VERSION 5.8 ;
BUSBITCHARS "[]" ;
DIVIDERCHAR "/" ;
UNITS
    DATABASE MICRONS 1000 ;
END UNITS

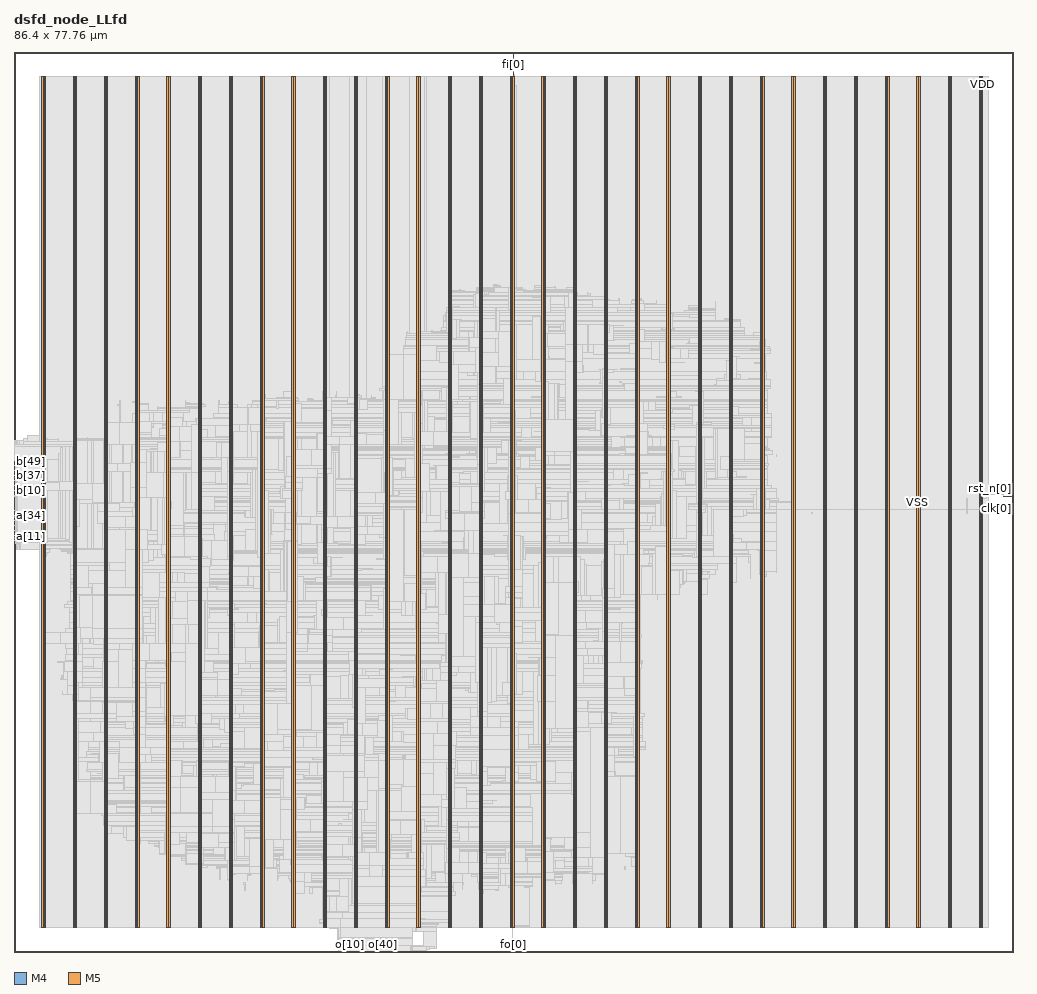
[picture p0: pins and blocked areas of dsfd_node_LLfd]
MACRO dsfd_node_LLfd
  FOREIGN dsfd_node_LLfd 0 0 ;
  CLASS BLOCK ;
  SIZE 86.4 BY 77.76 ;
  PIN a[0]
    DIRECTION INPUT ;
    USE SIGNAL ;
    PORT
      LAYER M4 ;
        RECT  0 35.376 0.084 35.4 ;
    END
  END a[0]
  PIN a[10]
    DIRECTION INPUT ;
    USE SIGNAL ;
    PORT
      LAYER M4 ;
        RECT  0 35.856 0.084 35.88 ;
    END
  END a[10]
  PIN a[11]
    DIRECTION INPUT ;
    USE SIGNAL ;
    PORT
      LAYER M4 ;
        RECT  0 35.904 0.084 35.928 ;
    END
  END a[11]
  PIN a[12]
    DIRECTION INPUT ;
    USE SIGNAL ;
    PORT
      LAYER M4 ;
        RECT  0 35.952 0.084 35.976 ;
    END
  END a[12]
  PIN a[13]
    DIRECTION INPUT ;
    USE SIGNAL ;
    PORT
      LAYER M4 ;
        RECT  0 36 0.084 36.024 ;
    END
  END a[13]
  PIN a[14]
    DIRECTION INPUT ;
    USE SIGNAL ;
    PORT
      LAYER M4 ;
        RECT  0 36.048 0.084 36.072 ;
    END
  END a[14]
  PIN a[15]
    DIRECTION INPUT ;
    USE SIGNAL ;
    PORT
      LAYER M4 ;
        RECT  0 36.096 0.084 36.12 ;
    END
  END a[15]
  PIN a[16]
    DIRECTION INPUT ;
    USE SIGNAL ;
    PORT
      LAYER M4 ;
        RECT  0 36.144 0.084 36.168 ;
    END
  END a[16]
  PIN a[17]
    DIRECTION INPUT ;
    USE SIGNAL ;
    PORT
      LAYER M4 ;
        RECT  0 36.192 0.084 36.216 ;
    END
  END a[17]
  PIN a[18]
    DIRECTION INPUT ;
    USE SIGNAL ;
    PORT
      LAYER M4 ;
        RECT  0 36.24 0.084 36.264 ;
    END
  END a[18]
  PIN a[19]
    DIRECTION INPUT ;
    USE SIGNAL ;
    PORT
      LAYER M4 ;
        RECT  0 36.288 0.084 36.312 ;
    END
  END a[19]
  PIN a[1]
    DIRECTION INPUT ;
    USE SIGNAL ;
    PORT
      LAYER M4 ;
        RECT  0 35.424 0.084 35.448 ;
    END
  END a[1]
  PIN a[20]
    DIRECTION INPUT ;
    USE SIGNAL ;
    PORT
      LAYER M4 ;
        RECT  0 36.336 0.084 36.36 ;
    END
  END a[20]
  PIN a[21]
    DIRECTION INPUT ;
    USE SIGNAL ;
    PORT
      LAYER M4 ;
        RECT  0 36.384 0.084 36.408 ;
    END
  END a[21]
  PIN a[22]
    DIRECTION INPUT ;
    USE SIGNAL ;
    PORT
      LAYER M4 ;
        RECT  0 36.432 0.084 36.456 ;
    END
  END a[22]
  PIN a[23]
    DIRECTION INPUT ;
    USE SIGNAL ;
    PORT
      LAYER M4 ;
        RECT  0 36.48 0.084 36.504 ;
    END
  END a[23]
  PIN a[24]
    DIRECTION INPUT ;
    USE SIGNAL ;
    PORT
      LAYER M4 ;
        RECT  0 36.528 0.084 36.552 ;
    END
  END a[24]
  PIN a[25]
    DIRECTION INPUT ;
    USE SIGNAL ;
    PORT
      LAYER M4 ;
        RECT  0 36.576 0.084 36.6 ;
    END
  END a[25]
  PIN a[26]
    DIRECTION INPUT ;
    USE SIGNAL ;
    PORT
      LAYER M4 ;
        RECT  0 36.624 0.084 36.648 ;
    END
  END a[26]
  PIN a[27]
    DIRECTION INPUT ;
    USE SIGNAL ;
    PORT
      LAYER M4 ;
        RECT  0 36.672 0.084 36.696 ;
    END
  END a[27]
  PIN a[28]
    DIRECTION INPUT ;
    USE SIGNAL ;
    PORT
      LAYER M4 ;
        RECT  0 36.72 0.084 36.744 ;
    END
  END a[28]
  PIN a[29]
    DIRECTION INPUT ;
    USE SIGNAL ;
    PORT
      LAYER M4 ;
        RECT  0 36.768 0.084 36.792 ;
    END
  END a[29]
  PIN a[2]
    DIRECTION INPUT ;
    USE SIGNAL ;
    PORT
      LAYER M4 ;
        RECT  0 35.472 0.084 35.496 ;
    END
  END a[2]
  PIN a[30]
    DIRECTION INPUT ;
    USE SIGNAL ;
    PORT
      LAYER M4 ;
        RECT  0 36.816 0.084 36.84 ;
    END
  END a[30]
  PIN a[31]
    DIRECTION INPUT ;
    USE SIGNAL ;
    PORT
      LAYER M4 ;
        RECT  0 36.864 0.084 36.888 ;
    END
  END a[31]
  PIN a[32]
    DIRECTION INPUT ;
    USE SIGNAL ;
    PORT
      LAYER M4 ;
        RECT  0 36.912 0.084 36.936 ;
    END
  END a[32]
  PIN a[33]
    DIRECTION INPUT ;
    USE SIGNAL ;
    PORT
      LAYER M4 ;
        RECT  0 36.96 0.084 36.984 ;
    END
  END a[33]
  PIN a[34]
    DIRECTION INPUT ;
    USE SIGNAL ;
    PORT
      LAYER M4 ;
        RECT  0 37.008 0.084 37.032 ;
    END
  END a[34]
  PIN a[35]
    DIRECTION INPUT ;
    USE SIGNAL ;
    PORT
      LAYER M4 ;
        RECT  0 37.056 0.084 37.08 ;
    END
  END a[35]
  PIN a[36]
    DIRECTION INPUT ;
    USE SIGNAL ;
    PORT
      LAYER M4 ;
        RECT  0 37.104 0.084 37.128 ;
    END
  END a[36]
  PIN a[37]
    DIRECTION INPUT ;
    USE SIGNAL ;
    PORT
      LAYER M4 ;
        RECT  0 37.152 0.084 37.176 ;
    END
  END a[37]
  PIN a[38]
    DIRECTION INPUT ;
    USE SIGNAL ;
    PORT
      LAYER M4 ;
        RECT  0 37.2 0.084 37.224 ;
    END
  END a[38]
  PIN a[39]
    DIRECTION INPUT ;
    USE SIGNAL ;
    PORT
      LAYER M4 ;
        RECT  0 37.248 0.084 37.272 ;
    END
  END a[39]
  PIN a[3]
    DIRECTION INPUT ;
    USE SIGNAL ;
    PORT
      LAYER M4 ;
        RECT  0 35.52 0.084 35.544 ;
    END
  END a[3]
  PIN a[40]
    DIRECTION INPUT ;
    USE SIGNAL ;
    PORT
      LAYER M4 ;
        RECT  0 37.296 0.084 37.32 ;
    END
  END a[40]
  PIN a[41]
    DIRECTION INPUT ;
    USE SIGNAL ;
    PORT
      LAYER M4 ;
        RECT  0 37.344 0.084 37.368 ;
    END
  END a[41]
  PIN a[42]
    DIRECTION INPUT ;
    USE SIGNAL ;
    PORT
      LAYER M4 ;
        RECT  0 37.392 0.084 37.416 ;
    END
  END a[42]
  PIN a[43]
    DIRECTION INPUT ;
    USE SIGNAL ;
    PORT
      LAYER M4 ;
        RECT  0 37.44 0.084 37.464 ;
    END
  END a[43]
  PIN a[44]
    DIRECTION INPUT ;
    USE SIGNAL ;
    PORT
      LAYER M4 ;
        RECT  0 37.488 0.084 37.512 ;
    END
  END a[44]
  PIN a[45]
    DIRECTION INPUT ;
    USE SIGNAL ;
    PORT
      LAYER M4 ;
        RECT  0 37.536 0.084 37.56 ;
    END
  END a[45]
  PIN a[46]
    DIRECTION INPUT ;
    USE SIGNAL ;
    PORT
      LAYER M4 ;
        RECT  0 37.584 0.084 37.608 ;
    END
  END a[46]
  PIN a[47]
    DIRECTION INPUT ;
    USE SIGNAL ;
    PORT
      LAYER M4 ;
        RECT  0 37.632 0.084 37.656 ;
    END
  END a[47]
  PIN a[48]
    DIRECTION INPUT ;
    USE SIGNAL ;
    PORT
      LAYER M4 ;
        RECT  0 37.68 0.084 37.704 ;
    END
  END a[48]
  PIN a[49]
    DIRECTION INPUT ;
    USE SIGNAL ;
    PORT
      LAYER M4 ;
        RECT  0 37.728 0.084 37.752 ;
    END
  END a[49]
  PIN a[4]
    DIRECTION INPUT ;
    USE SIGNAL ;
    PORT
      LAYER M4 ;
        RECT  0 35.568 0.084 35.592 ;
    END
  END a[4]
  PIN a[50]
    DIRECTION INPUT ;
    USE SIGNAL ;
    PORT
      LAYER M4 ;
        RECT  0 37.776 0.084 37.8 ;
    END
  END a[50]
  PIN a[51]
    DIRECTION INPUT ;
    USE SIGNAL ;
    PORT
      LAYER M4 ;
        RECT  0 37.824 0.084 37.848 ;
    END
  END a[51]
  PIN a[52]
    DIRECTION INPUT ;
    USE SIGNAL ;
    PORT
      LAYER M4 ;
        RECT  0 37.872 0.084 37.896 ;
    END
  END a[52]
  PIN a[53]
    DIRECTION INPUT ;
    USE SIGNAL ;
    PORT
      LAYER M4 ;
        RECT  0 37.92 0.084 37.944 ;
    END
  END a[53]
  PIN a[54]
    DIRECTION INPUT ;
    USE SIGNAL ;
    PORT
      LAYER M4 ;
        RECT  0 37.968 0.084 37.992 ;
    END
  END a[54]
  PIN a[55]
    DIRECTION INPUT ;
    USE SIGNAL ;
    PORT
      LAYER M4 ;
        RECT  0 38.016 0.084 38.04 ;
    END
  END a[55]
  PIN a[56]
    DIRECTION INPUT ;
    USE SIGNAL ;
    PORT
      LAYER M4 ;
        RECT  0 38.064 0.084 38.088 ;
    END
  END a[56]
  PIN a[57]
    DIRECTION INPUT ;
    USE SIGNAL ;
    PORT
      LAYER M4 ;
        RECT  0 38.112 0.084 38.136 ;
    END
  END a[57]
  PIN a[58]
    DIRECTION INPUT ;
    USE SIGNAL ;
    PORT
      LAYER M4 ;
        RECT  0 38.16 0.084 38.184 ;
    END
  END a[58]
  PIN a[59]
    DIRECTION INPUT ;
    USE SIGNAL ;
    PORT
      LAYER M4 ;
        RECT  0 38.208 0.084 38.232 ;
    END
  END a[59]
  PIN a[5]
    DIRECTION INPUT ;
    USE SIGNAL ;
    PORT
      LAYER M4 ;
        RECT  0 35.616 0.084 35.64 ;
    END
  END a[5]
  PIN a[60]
    DIRECTION INPUT ;
    USE SIGNAL ;
    PORT
      LAYER M4 ;
        RECT  0 38.256 0.084 38.28 ;
    END
  END a[60]
  PIN a[61]
    DIRECTION INPUT ;
    USE SIGNAL ;
    PORT
      LAYER M4 ;
        RECT  0 38.304 0.084 38.328 ;
    END
  END a[61]
  PIN a[62]
    DIRECTION INPUT ;
    USE SIGNAL ;
    PORT
      LAYER M4 ;
        RECT  0 38.352 0.084 38.376 ;
    END
  END a[62]
  PIN a[6]
    DIRECTION INPUT ;
    USE SIGNAL ;
    PORT
      LAYER M4 ;
        RECT  0 35.664 0.084 35.688 ;
    END
  END a[6]
  PIN a[7]
    DIRECTION INPUT ;
    USE SIGNAL ;
    PORT
      LAYER M4 ;
        RECT  0 35.712 0.084 35.736 ;
    END
  END a[7]
  PIN a[8]
    DIRECTION INPUT ;
    USE SIGNAL ;
    PORT
      LAYER M4 ;
        RECT  0 35.76 0.084 35.784 ;
    END
  END a[8]
  PIN a[9]
    DIRECTION INPUT ;
    USE SIGNAL ;
    PORT
      LAYER M4 ;
        RECT  0 35.808 0.084 35.832 ;
    END
  END a[9]
  PIN b[0]
    DIRECTION INPUT ;
    USE SIGNAL ;
    PORT
      LAYER M4 ;
        RECT  0 39.36 0.084 39.384 ;
    END
  END b[0]
  PIN b[10]
    DIRECTION INPUT ;
    USE SIGNAL ;
    PORT
      LAYER M4 ;
        RECT  0 39.84 0.084 39.864 ;
    END
  END b[10]
  PIN b[11]
    DIRECTION INPUT ;
    USE SIGNAL ;
    PORT
      LAYER M4 ;
        RECT  0 39.888 0.084 39.912 ;
    END
  END b[11]
  PIN b[12]
    DIRECTION INPUT ;
    USE SIGNAL ;
    PORT
      LAYER M4 ;
        RECT  0 39.936 0.084 39.96 ;
    END
  END b[12]
  PIN b[13]
    DIRECTION INPUT ;
    USE SIGNAL ;
    PORT
      LAYER M4 ;
        RECT  0 39.984 0.084 40.008 ;
    END
  END b[13]
  PIN b[14]
    DIRECTION INPUT ;
    USE SIGNAL ;
    PORT
      LAYER M4 ;
        RECT  0 40.032 0.084 40.056 ;
    END
  END b[14]
  PIN b[15]
    DIRECTION INPUT ;
    USE SIGNAL ;
    PORT
      LAYER M4 ;
        RECT  0 40.08 0.084 40.104 ;
    END
  END b[15]
  PIN b[16]
    DIRECTION INPUT ;
    USE SIGNAL ;
    PORT
      LAYER M4 ;
        RECT  0 40.128 0.084 40.152 ;
    END
  END b[16]
  PIN b[17]
    DIRECTION INPUT ;
    USE SIGNAL ;
    PORT
      LAYER M4 ;
        RECT  0 40.176 0.084 40.2 ;
    END
  END b[17]
  PIN b[18]
    DIRECTION INPUT ;
    USE SIGNAL ;
    PORT
      LAYER M4 ;
        RECT  0 40.224 0.084 40.248 ;
    END
  END b[18]
  PIN b[19]
    DIRECTION INPUT ;
    USE SIGNAL ;
    PORT
      LAYER M4 ;
        RECT  0 40.272 0.084 40.296 ;
    END
  END b[19]
  PIN b[1]
    DIRECTION INPUT ;
    USE SIGNAL ;
    PORT
      LAYER M4 ;
        RECT  0 39.408 0.084 39.432 ;
    END
  END b[1]
  PIN b[20]
    DIRECTION INPUT ;
    USE SIGNAL ;
    PORT
      LAYER M4 ;
        RECT  0 40.32 0.084 40.344 ;
    END
  END b[20]
  PIN b[21]
    DIRECTION INPUT ;
    USE SIGNAL ;
    PORT
      LAYER M4 ;
        RECT  0 40.368 0.084 40.392 ;
    END
  END b[21]
  PIN b[22]
    DIRECTION INPUT ;
    USE SIGNAL ;
    PORT
      LAYER M4 ;
        RECT  0 40.416 0.084 40.44 ;
    END
  END b[22]
  PIN b[23]
    DIRECTION INPUT ;
    USE SIGNAL ;
    PORT
      LAYER M4 ;
        RECT  0 40.464 0.084 40.488 ;
    END
  END b[23]
  PIN b[24]
    DIRECTION INPUT ;
    USE SIGNAL ;
    PORT
      LAYER M4 ;
        RECT  0 40.512 0.084 40.536 ;
    END
  END b[24]
  PIN b[25]
    DIRECTION INPUT ;
    USE SIGNAL ;
    PORT
      LAYER M4 ;
        RECT  0 40.56 0.084 40.584 ;
    END
  END b[25]
  PIN b[26]
    DIRECTION INPUT ;
    USE SIGNAL ;
    PORT
      LAYER M4 ;
        RECT  0 40.608 0.084 40.632 ;
    END
  END b[26]
  PIN b[27]
    DIRECTION INPUT ;
    USE SIGNAL ;
    PORT
      LAYER M4 ;
        RECT  0 40.656 0.084 40.68 ;
    END
  END b[27]
  PIN b[28]
    DIRECTION INPUT ;
    USE SIGNAL ;
    PORT
      LAYER M4 ;
        RECT  0 40.704 0.084 40.728 ;
    END
  END b[28]
  PIN b[29]
    DIRECTION INPUT ;
    USE SIGNAL ;
    PORT
      LAYER M4 ;
        RECT  0 40.752 0.084 40.776 ;
    END
  END b[29]
  PIN b[2]
    DIRECTION INPUT ;
    USE SIGNAL ;
    PORT
      LAYER M4 ;
        RECT  0 39.456 0.084 39.48 ;
    END
  END b[2]
  PIN b[30]
    DIRECTION INPUT ;
    USE SIGNAL ;
    PORT
      LAYER M4 ;
        RECT  0 40.8 0.084 40.824 ;
    END
  END b[30]
  PIN b[31]
    DIRECTION INPUT ;
    USE SIGNAL ;
    PORT
      LAYER M4 ;
        RECT  0 40.848 0.084 40.872 ;
    END
  END b[31]
  PIN b[32]
    DIRECTION INPUT ;
    USE SIGNAL ;
    PORT
      LAYER M4 ;
        RECT  0 40.896 0.084 40.92 ;
    END
  END b[32]
  PIN b[33]
    DIRECTION INPUT ;
    USE SIGNAL ;
    PORT
      LAYER M4 ;
        RECT  0 40.944 0.084 40.968 ;
    END
  END b[33]
  PIN b[34]
    DIRECTION INPUT ;
    USE SIGNAL ;
    PORT
      LAYER M4 ;
        RECT  0 40.992 0.084 41.016 ;
    END
  END b[34]
  PIN b[35]
    DIRECTION INPUT ;
    USE SIGNAL ;
    PORT
      LAYER M4 ;
        RECT  0 41.04 0.084 41.064 ;
    END
  END b[35]
  PIN b[36]
    DIRECTION INPUT ;
    USE SIGNAL ;
    PORT
      LAYER M4 ;
        RECT  0 41.088 0.084 41.112 ;
    END
  END b[36]
  PIN b[37]
    DIRECTION INPUT ;
    USE SIGNAL ;
    PORT
      LAYER M4 ;
        RECT  0 41.136 0.084 41.16 ;
    END
  END b[37]
  PIN b[38]
    DIRECTION INPUT ;
    USE SIGNAL ;
    PORT
      LAYER M4 ;
        RECT  0 41.184 0.084 41.208 ;
    END
  END b[38]
  PIN b[39]
    DIRECTION INPUT ;
    USE SIGNAL ;
    PORT
      LAYER M4 ;
        RECT  0 41.232 0.084 41.256 ;
    END
  END b[39]
  PIN b[3]
    DIRECTION INPUT ;
    USE SIGNAL ;
    PORT
      LAYER M4 ;
        RECT  0 39.504 0.084 39.528 ;
    END
  END b[3]
  PIN b[40]
    DIRECTION INPUT ;
    USE SIGNAL ;
    PORT
      LAYER M4 ;
        RECT  0 41.28 0.084 41.304 ;
    END
  END b[40]
  PIN b[41]
    DIRECTION INPUT ;
    USE SIGNAL ;
    PORT
      LAYER M4 ;
        RECT  0 41.328 0.084 41.352 ;
    END
  END b[41]
  PIN b[42]
    DIRECTION INPUT ;
    USE SIGNAL ;
    PORT
      LAYER M4 ;
        RECT  0 41.376 0.084 41.4 ;
    END
  END b[42]
  PIN b[43]
    DIRECTION INPUT ;
    USE SIGNAL ;
    PORT
      LAYER M4 ;
        RECT  0 41.424 0.084 41.448 ;
    END
  END b[43]
  PIN b[44]
    DIRECTION INPUT ;
    USE SIGNAL ;
    PORT
      LAYER M4 ;
        RECT  0 41.472 0.084 41.496 ;
    END
  END b[44]
  PIN b[45]
    DIRECTION INPUT ;
    USE SIGNAL ;
    PORT
      LAYER M4 ;
        RECT  0 41.52 0.084 41.544 ;
    END
  END b[45]
  PIN b[46]
    DIRECTION INPUT ;
    USE SIGNAL ;
    PORT
      LAYER M4 ;
        RECT  0 41.568 0.084 41.592 ;
    END
  END b[46]
  PIN b[47]
    DIRECTION INPUT ;
    USE SIGNAL ;
    PORT
      LAYER M4 ;
        RECT  0 41.616 0.084 41.64 ;
    END
  END b[47]
  PIN b[48]
    DIRECTION INPUT ;
    USE SIGNAL ;
    PORT
      LAYER M4 ;
        RECT  0 41.664 0.084 41.688 ;
    END
  END b[48]
  PIN b[49]
    DIRECTION INPUT ;
    USE SIGNAL ;
    PORT
      LAYER M4 ;
        RECT  0 41.712 0.084 41.736 ;
    END
  END b[49]
  PIN b[4]
    DIRECTION INPUT ;
    USE SIGNAL ;
    PORT
      LAYER M4 ;
        RECT  0 39.552 0.084 39.576 ;
    END
  END b[4]
  PIN b[50]
    DIRECTION INPUT ;
    USE SIGNAL ;
    PORT
      LAYER M4 ;
        RECT  0 41.76 0.084 41.784 ;
    END
  END b[50]
  PIN b[51]
    DIRECTION INPUT ;
    USE SIGNAL ;
    PORT
      LAYER M4 ;
        RECT  0 41.808 0.084 41.832 ;
    END
  END b[51]
  PIN b[52]
    DIRECTION INPUT ;
    USE SIGNAL ;
    PORT
      LAYER M4 ;
        RECT  0 41.856 0.084 41.88 ;
    END
  END b[52]
  PIN b[53]
    DIRECTION INPUT ;
    USE SIGNAL ;
    PORT
      LAYER M4 ;
        RECT  0 41.904 0.084 41.928 ;
    END
  END b[53]
  PIN b[54]
    DIRECTION INPUT ;
    USE SIGNAL ;
    PORT
      LAYER M4 ;
        RECT  0 41.952 0.084 41.976 ;
    END
  END b[54]
  PIN b[55]
    DIRECTION INPUT ;
    USE SIGNAL ;
    PORT
      LAYER M4 ;
        RECT  0 42 0.084 42.024 ;
    END
  END b[55]
  PIN b[56]
    DIRECTION INPUT ;
    USE SIGNAL ;
    PORT
      LAYER M4 ;
        RECT  0 42.048 0.084 42.072 ;
    END
  END b[56]
  PIN b[57]
    DIRECTION INPUT ;
    USE SIGNAL ;
    PORT
      LAYER M4 ;
        RECT  0 42.096 0.084 42.12 ;
    END
  END b[57]
  PIN b[58]
    DIRECTION INPUT ;
    USE SIGNAL ;
    PORT
      LAYER M4 ;
        RECT  0 42.144 0.084 42.168 ;
    END
  END b[58]
  PIN b[59]
    DIRECTION INPUT ;
    USE SIGNAL ;
    PORT
      LAYER M4 ;
        RECT  0 42.192 0.084 42.216 ;
    END
  END b[59]
  PIN b[5]
    DIRECTION INPUT ;
    USE SIGNAL ;
    PORT
      LAYER M4 ;
        RECT  0 39.6 0.084 39.624 ;
    END
  END b[5]
  PIN b[60]
    DIRECTION INPUT ;
    USE SIGNAL ;
    PORT
      LAYER M4 ;
        RECT  0 42.24 0.084 42.264 ;
    END
  END b[60]
  PIN b[61]
    DIRECTION INPUT ;
    USE SIGNAL ;
    PORT
      LAYER M4 ;
        RECT  0 42.288 0.084 42.312 ;
    END
  END b[61]
  PIN b[62]
    DIRECTION INPUT ;
    USE SIGNAL ;
    PORT
      LAYER M4 ;
        RECT  0 42.336 0.084 42.36 ;
    END
  END b[62]
  PIN b[6]
    DIRECTION INPUT ;
    USE SIGNAL ;
    PORT
      LAYER M4 ;
        RECT  0 39.648 0.084 39.672 ;
    END
  END b[6]
  PIN b[7]
    DIRECTION INPUT ;
    USE SIGNAL ;
    PORT
      LAYER M4 ;
        RECT  0 39.696 0.084 39.72 ;
    END
  END b[7]
  PIN b[8]
    DIRECTION INPUT ;
    USE SIGNAL ;
    PORT
      LAYER M4 ;
        RECT  0 39.744 0.084 39.768 ;
    END
  END b[8]
  PIN b[9]
    DIRECTION INPUT ;
    USE SIGNAL ;
    PORT
      LAYER M4 ;
        RECT  0 39.792 0.084 39.816 ;
    END
  END b[9]
  PIN clk[0]
    DIRECTION INPUT ;
    USE SIGNAL ;
    PORT
      LAYER M4 ;
        RECT  86.316 38.352 86.4 38.376 ;
    END
    PORT
      LAYER M4 ;
        RECT  86.281 38.208 86.321 38.376 ;
    END
    PORT
      LAYER M4 ;
        RECT  86.321 38.352 86.364 38.376 ;
    END
  END clk[0]
  PIN fi[0]
    DIRECTION INPUT ;
    USE SIGNAL ;
    PORT
      LAYER M5 ;
        RECT  43.152 77.676 43.176 77.76 ;
    END
    PORT
      LAYER M5 ;
        RECT  43.152 75.623 43.176 77.712 ;
    END
  END fi[0]
  PIN fo[0]
    DIRECTION OUTPUT ;
    USE SIGNAL ;
    PORT
      LAYER M5 ;
        RECT  43.152 0 43.176 0.084 ;
    END
    PORT
      LAYER M5 ;
        RECT  43.152 0.016 43.176 0.131 ;
    END
  END fo[0]
  PIN o[0]
    DIRECTION OUTPUT ;
    USE SIGNAL ;
    PORT
      LAYER M5 ;
        RECT  28.032 0 28.056 0.084 ;
    END
  END o[0]
  PIN o[10]
    DIRECTION OUTPUT ;
    USE SIGNAL ;
    PORT
      LAYER M5 ;
        RECT  28.992 0 29.016 0.084 ;
    END
  END o[10]
  PIN o[11]
    DIRECTION OUTPUT ;
    USE SIGNAL ;
    PORT
      LAYER M5 ;
        RECT  29.088 0 29.112 0.084 ;
    END
  END o[11]
  PIN o[12]
    DIRECTION OUTPUT ;
    USE SIGNAL ;
    PORT
      LAYER M5 ;
        RECT  29.184 0 29.208 0.084 ;
    END
  END o[12]
  PIN o[13]
    DIRECTION OUTPUT ;
    USE SIGNAL ;
    PORT
      LAYER M5 ;
        RECT  29.28 0 29.304 0.084 ;
    END
  END o[13]
  PIN o[14]
    DIRECTION OUTPUT ;
    USE SIGNAL ;
    PORT
      LAYER M5 ;
        RECT  29.376 0 29.4 0.084 ;
    END
  END o[14]
  PIN o[15]
    DIRECTION OUTPUT ;
    USE SIGNAL ;
    PORT
      LAYER M5 ;
        RECT  29.472 0 29.496 0.084 ;
    END
  END o[15]
  PIN o[16]
    DIRECTION OUTPUT ;
    USE SIGNAL ;
    PORT
      LAYER M5 ;
        RECT  29.568 0 29.592 0.084 ;
    END
  END o[16]
  PIN o[17]
    DIRECTION OUTPUT ;
    USE SIGNAL ;
    PORT
      LAYER M5 ;
        RECT  29.664 0 29.688 0.084 ;
    END
  END o[17]
  PIN o[18]
    DIRECTION OUTPUT ;
    USE SIGNAL ;
    PORT
      LAYER M5 ;
        RECT  29.76 0 29.784 0.084 ;
    END
  END o[18]
  PIN o[19]
    DIRECTION OUTPUT ;
    USE SIGNAL ;
    PORT
      LAYER M5 ;
        RECT  29.856 0 29.88 0.084 ;
    END
  END o[19]
  PIN o[1]
    DIRECTION OUTPUT ;
    USE SIGNAL ;
    PORT
      LAYER M5 ;
        RECT  28.128 0 28.152 0.084 ;
    END
  END o[1]
  PIN o[20]
    DIRECTION OUTPUT ;
    USE SIGNAL ;
    PORT
      LAYER M5 ;
        RECT  29.952 0 29.976 0.084 ;
    END
  END o[20]
  PIN o[21]
    DIRECTION OUTPUT ;
    USE SIGNAL ;
    PORT
      LAYER M5 ;
        RECT  30.048 0 30.072 0.084 ;
    END
  END o[21]
  PIN o[22]
    DIRECTION OUTPUT ;
    USE SIGNAL ;
    PORT
      LAYER M5 ;
        RECT  30.144 0 30.168 0.084 ;
    END
  END o[22]
  PIN o[23]
    DIRECTION OUTPUT ;
    USE SIGNAL ;
    PORT
      LAYER M5 ;
        RECT  30.24 0 30.264 0.084 ;
    END
  END o[23]
  PIN o[24]
    DIRECTION OUTPUT ;
    USE SIGNAL ;
    PORT
      LAYER M5 ;
        RECT  30.336 0 30.36 0.084 ;
    END
  END o[24]
  PIN o[25]
    DIRECTION OUTPUT ;
    USE SIGNAL ;
    PORT
      LAYER M5 ;
        RECT  30.432 0 30.456 0.084 ;
    END
  END o[25]
  PIN o[26]
    DIRECTION OUTPUT ;
    USE SIGNAL ;
    PORT
      LAYER M5 ;
        RECT  30.528 0 30.552 0.084 ;
    END
  END o[26]
  PIN o[27]
    DIRECTION OUTPUT ;
    USE SIGNAL ;
    PORT
      LAYER M5 ;
        RECT  30.624 0 30.648 0.084 ;
    END
  END o[27]
  PIN o[28]
    DIRECTION OUTPUT ;
    USE SIGNAL ;
    PORT
      LAYER M5 ;
        RECT  30.72 0 30.744 0.084 ;
    END
  END o[28]
  PIN o[29]
    DIRECTION OUTPUT ;
    USE SIGNAL ;
    PORT
      LAYER M5 ;
        RECT  30.816 0 30.84 0.084 ;
    END
  END o[29]
  PIN o[2]
    DIRECTION OUTPUT ;
    USE SIGNAL ;
    PORT
      LAYER M5 ;
        RECT  28.224 0 28.248 0.084 ;
    END
  END o[2]
  PIN o[30]
    DIRECTION OUTPUT ;
    USE SIGNAL ;
    PORT
      LAYER M5 ;
        RECT  30.912 0 30.936 0.084 ;
    END
  END o[30]
  PIN o[31]
    DIRECTION OUTPUT ;
    USE SIGNAL ;
    PORT
      LAYER M5 ;
        RECT  31.008 0 31.032 0.084 ;
    END
  END o[31]
  PIN o[32]
    DIRECTION OUTPUT ;
    USE SIGNAL ;
    PORT
      LAYER M5 ;
        RECT  31.104 0 31.128 0.084 ;
    END
  END o[32]
  PIN o[33]
    DIRECTION OUTPUT ;
    USE SIGNAL ;
    PORT
      LAYER M5 ;
        RECT  31.2 0 31.224 0.084 ;
    END
  END o[33]
  PIN o[34]
    DIRECTION OUTPUT ;
    USE SIGNAL ;
    PORT
      LAYER M5 ;
        RECT  31.296 0 31.32 0.084 ;
    END
  END o[34]
  PIN o[35]
    DIRECTION OUTPUT ;
    USE SIGNAL ;
    PORT
      LAYER M5 ;
        RECT  31.392 0 31.416 0.084 ;
    END
  END o[35]
  PIN o[36]
    DIRECTION OUTPUT ;
    USE SIGNAL ;
    PORT
      LAYER M5 ;
        RECT  31.488 0 31.512 0.084 ;
    END
  END o[36]
  PIN o[37]
    DIRECTION OUTPUT ;
    USE SIGNAL ;
    PORT
      LAYER M5 ;
        RECT  31.584 0 31.608 0.084 ;
    END
  END o[37]
  PIN o[38]
    DIRECTION OUTPUT ;
    USE SIGNAL ;
    PORT
      LAYER M5 ;
        RECT  31.68 0 31.704 0.084 ;
    END
  END o[38]
  PIN o[39]
    DIRECTION OUTPUT ;
    USE SIGNAL ;
    PORT
      LAYER M5 ;
        RECT  31.776 0 31.8 0.084 ;
    END
  END o[39]
  PIN o[3]
    DIRECTION OUTPUT ;
    USE SIGNAL ;
    PORT
      LAYER M5 ;
        RECT  28.32 0 28.344 0.084 ;
    END
  END o[3]
  PIN o[40]
    DIRECTION OUTPUT ;
    USE SIGNAL ;
    PORT
      LAYER M5 ;
        RECT  31.872 0 31.896 0.084 ;
    END
  END o[40]
  PIN o[41]
    DIRECTION OUTPUT ;
    USE SIGNAL ;
    PORT
      LAYER M5 ;
        RECT  31.968 0 31.992 0.084 ;
    END
  END o[41]
  PIN o[42]
    DIRECTION OUTPUT ;
    USE SIGNAL ;
    PORT
      LAYER M5 ;
        RECT  32.064 0 32.088 0.084 ;
    END
  END o[42]
  PIN o[43]
    DIRECTION OUTPUT ;
    USE SIGNAL ;
    PORT
      LAYER M5 ;
        RECT  32.16 0 32.184 0.084 ;
    END
  END o[43]
  PIN o[44]
    DIRECTION OUTPUT ;
    USE SIGNAL ;
    PORT
      LAYER M5 ;
        RECT  32.256 0 32.28 0.084 ;
    END
  END o[44]
  PIN o[45]
    DIRECTION OUTPUT ;
    USE SIGNAL ;
    PORT
      LAYER M5 ;
        RECT  32.352 0 32.376 0.084 ;
    END
  END o[45]
  PIN o[46]
    DIRECTION OUTPUT ;
    USE SIGNAL ;
    PORT
      LAYER M5 ;
        RECT  32.448 0 32.472 0.084 ;
    END
  END o[46]
  PIN o[47]
    DIRECTION OUTPUT ;
    USE SIGNAL ;
    PORT
      LAYER M5 ;
        RECT  32.544 0 32.568 0.084 ;
    END
  END o[47]
  PIN o[48]
    DIRECTION OUTPUT ;
    USE SIGNAL ;
    PORT
      LAYER M5 ;
        RECT  32.64 0 32.664 0.084 ;
    END
  END o[48]
  PIN o[49]
    DIRECTION OUTPUT ;
    USE SIGNAL ;
    PORT
      LAYER M5 ;
        RECT  32.736 0 32.76 0.084 ;
    END
  END o[49]
  PIN o[4]
    DIRECTION OUTPUT ;
    USE SIGNAL ;
    PORT
      LAYER M5 ;
        RECT  28.416 0 28.44 0.084 ;
    END
  END o[4]
  PIN o[50]
    DIRECTION OUTPUT ;
    USE SIGNAL ;
    PORT
      LAYER M5 ;
        RECT  32.832 0 32.856 0.084 ;
    END
  END o[50]
  PIN o[51]
    DIRECTION OUTPUT ;
    USE SIGNAL ;
    PORT
      LAYER M5 ;
        RECT  32.928 0 32.952 0.084 ;
    END
  END o[51]
  PIN o[52]
    DIRECTION OUTPUT ;
    USE SIGNAL ;
    PORT
      LAYER M5 ;
        RECT  33.024 0 33.048 0.084 ;
    END
  END o[52]
  PIN o[53]
    DIRECTION OUTPUT ;
    USE SIGNAL ;
    PORT
      LAYER M5 ;
        RECT  33.12 0 33.144 0.084 ;
    END
  END o[53]
  PIN o[54]
    DIRECTION OUTPUT ;
    USE SIGNAL ;
    PORT
      LAYER M5 ;
        RECT  33.216 0 33.24 0.084 ;
    END
  END o[54]
  PIN o[55]
    DIRECTION OUTPUT ;
    USE SIGNAL ;
    PORT
      LAYER M5 ;
        RECT  33.312 0 33.336 0.084 ;
    END
  END o[55]
  PIN o[56]
    DIRECTION OUTPUT ;
    USE SIGNAL ;
    PORT
      LAYER M5 ;
        RECT  33.408 0 33.432 0.084 ;
    END
  END o[56]
  PIN o[57]
    DIRECTION OUTPUT ;
    USE SIGNAL ;
    PORT
      LAYER M5 ;
        RECT  33.504 0 33.528 0.084 ;
    END
  END o[57]
  PIN o[58]
    DIRECTION OUTPUT ;
    USE SIGNAL ;
    PORT
      LAYER M5 ;
        RECT  33.6 0 33.624 0.084 ;
    END
  END o[58]
  PIN o[59]
    DIRECTION OUTPUT ;
    USE SIGNAL ;
    PORT
      LAYER M5 ;
        RECT  33.696 0 33.72 0.084 ;
    END
  END o[59]
  PIN o[5]
    DIRECTION OUTPUT ;
    USE SIGNAL ;
    PORT
      LAYER M5 ;
        RECT  28.512 0 28.536 0.084 ;
    END
  END o[5]
  PIN o[60]
    DIRECTION OUTPUT ;
    USE SIGNAL ;
    PORT
      LAYER M5 ;
        RECT  33.792 0 33.816 0.084 ;
    END
  END o[60]
  PIN o[61]
    DIRECTION OUTPUT ;
    USE SIGNAL ;
    PORT
      LAYER M5 ;
        RECT  33.888 0 33.912 0.084 ;
    END
  END o[61]
  PIN o[62]
    DIRECTION OUTPUT ;
    USE SIGNAL ;
    PORT
      LAYER M5 ;
        RECT  33.984 0 34.008 0.084 ;
    END
  END o[62]
  PIN o[63]
    DIRECTION OUTPUT ;
    USE SIGNAL ;
    PORT
      LAYER M5 ;
        RECT  34.08 0 34.104 0.084 ;
    END
  END o[63]
  PIN o[64]
    DIRECTION OUTPUT ;
    USE SIGNAL ;
    PORT
      LAYER M5 ;
        RECT  34.176 0 34.2 0.084 ;
    END
  END o[64]
  PIN o[65]
    DIRECTION OUTPUT ;
    USE SIGNAL ;
    PORT
      LAYER M5 ;
        RECT  34.272 0 34.296 0.084 ;
    END
  END o[65]
  PIN o[6]
    DIRECTION OUTPUT ;
    USE SIGNAL ;
    PORT
      LAYER M5 ;
        RECT  28.608 0 28.632 0.084 ;
    END
  END o[6]
  PIN o[7]
    DIRECTION OUTPUT ;
    USE SIGNAL ;
    PORT
      LAYER M5 ;
        RECT  28.704 0 28.728 0.084 ;
    END
  END o[7]
  PIN o[8]
    DIRECTION OUTPUT ;
    USE SIGNAL ;
    PORT
      LAYER M5 ;
        RECT  28.8 0 28.824 0.084 ;
    END
  END o[8]
  PIN o[9]
    DIRECTION OUTPUT ;
    USE SIGNAL ;
    PORT
      LAYER M5 ;
        RECT  28.896 0 28.92 0.084 ;
    END
  END o[9]
  PIN rst_n[0]
    DIRECTION INPUT ;
    USE SIGNAL ;
    PORT
      LAYER M4 ;
        RECT  86.316 39.36 86.4 39.384 ;
    END
    PORT
      LAYER M4 ;
        RECT  85.453 39.36 86.364 39.384 ;
    END
  END rst_n[0]
  PIN VDD
    DIRECTION INOUT ;
    USE POWER ;
    PORT
      LAYER M5 ;
        RECT  83.592 2.151 83.712 75.609 ;
        RECT  80.892 2.151 81.012 75.609 ;
        RECT  78.192 2.151 78.312 75.609 ;
        RECT  75.492 2.151 75.612 75.609 ;
        RECT  72.792 2.151 72.912 75.609 ;
        RECT  70.092 2.151 70.212 75.609 ;
        RECT  67.392 2.151 67.512 75.609 ;
        RECT  64.692 2.151 64.812 75.609 ;
        RECT  61.992 2.151 62.112 75.609 ;
        RECT  59.292 2.151 59.412 75.609 ;
        RECT  56.592 2.151 56.712 75.609 ;
        RECT  53.892 2.151 54.012 75.609 ;
        RECT  51.192 2.151 51.312 75.609 ;
        RECT  48.492 2.151 48.612 75.609 ;
        RECT  45.792 2.151 45.912 75.609 ;
        RECT  43.092 2.151 43.212 75.609 ;
        RECT  40.392 2.151 40.512 75.609 ;
        RECT  37.692 2.151 37.812 75.609 ;
        RECT  34.992 2.151 35.112 75.609 ;
        RECT  32.292 2.151 32.412 75.609 ;
        RECT  29.592 2.151 29.712 75.609 ;
        RECT  26.892 2.151 27.012 75.609 ;
        RECT  24.192 2.151 24.312 75.609 ;
        RECT  21.492 2.151 21.612 75.609 ;
        RECT  18.792 2.151 18.912 75.609 ;
        RECT  16.092 2.151 16.212 75.609 ;
        RECT  13.392 2.151 13.512 75.609 ;
        RECT  10.692 2.151 10.812 75.609 ;
        RECT  7.992 2.151 8.112 75.609 ;
        RECT  5.292 2.151 5.412 75.609 ;
        RECT  2.592 2.151 2.712 75.609 ;
    END
  END VDD
  PIN VSS
    DIRECTION INOUT ;
    USE GROUND ;
    PORT
      LAYER M5 ;
        RECT  83.4 2.137 83.52 75.623 ;
        RECT  80.7 2.137 80.82 75.623 ;
        RECT  78 2.137 78.12 75.623 ;
        RECT  75.3 2.137 75.42 75.623 ;
        RECT  72.6 2.137 72.72 75.623 ;
        RECT  69.9 2.137 70.02 75.623 ;
        RECT  67.2 2.137 67.32 75.623 ;
        RECT  64.5 2.137 64.62 75.623 ;
        RECT  61.8 2.137 61.92 75.623 ;
        RECT  59.1 2.137 59.22 75.623 ;
        RECT  56.4 2.137 56.52 75.623 ;
        RECT  53.7 2.137 53.82 75.623 ;
        RECT  51 2.137 51.12 75.623 ;
        RECT  48.3 2.137 48.42 75.623 ;
        RECT  45.6 2.137 45.72 75.623 ;
        RECT  42.9 2.137 43.02 75.623 ;
        RECT  40.2 2.137 40.32 75.623 ;
        RECT  37.5 2.137 37.62 75.623 ;
        RECT  34.8 2.137 34.92 75.623 ;
        RECT  32.1 2.137 32.22 75.623 ;
        RECT  29.4 2.137 29.52 75.623 ;
        RECT  26.7 2.137 26.82 75.623 ;
        RECT  24 2.137 24.12 75.623 ;
        RECT  21.3 2.137 21.42 75.623 ;
        RECT  18.6 2.137 18.72 75.623 ;
        RECT  15.9 2.137 16.02 75.623 ;
        RECT  13.2 2.137 13.32 75.623 ;
        RECT  10.5 2.137 10.62 75.623 ;
        RECT  7.8 2.137 7.92 75.623 ;
        RECT  5.1 2.137 5.22 75.623 ;
        RECT  2.4 2.137 2.52 75.623 ;
    END
  END VSS
  # OT_OBS_CLOSED layer=M5 d_um=1.536 added=240
  OBS
    LAYER RVTN ;
     RECT  2.16 2.16 84.24 2.295 ;
     RECT  2.16 2.565 84.24 2.835 ;
     RECT  2.16 3.105 84.24 3.375 ;
     RECT  2.16 3.645 84.24 3.915 ;
     RECT  2.16 4.185 84.24 4.455 ;
     RECT  2.16 4.725 84.24 4.995 ;
     RECT  2.16 5.265 84.24 5.535 ;
     RECT  2.16 5.805 84.24 6.075 ;
     RECT  2.16 6.345 84.24 6.615 ;
     RECT  2.16 6.885 84.24 7.155 ;
     RECT  2.16 7.425 84.24 7.695 ;
     RECT  2.16 7.965 84.24 8.235 ;
     RECT  2.16 8.505 84.24 8.775 ;
     RECT  2.16 9.045 84.24 9.315 ;
     RECT  2.16 9.585 84.24 9.855 ;
     RECT  2.16 10.125 84.24 10.395 ;
     RECT  2.16 10.665 84.24 10.935 ;
     RECT  2.16 11.205 84.24 11.475 ;
     RECT  2.16 11.745 84.24 12.015 ;
     RECT  2.16 12.285 84.24 12.555 ;
     RECT  2.16 12.825 84.24 13.095 ;
     RECT  2.16 13.365 84.24 13.635 ;
     RECT  2.16 13.905 84.24 14.175 ;
     RECT  2.16 14.445 84.24 14.715 ;
     RECT  2.16 14.985 84.24 15.255 ;
     RECT  2.16 15.525 84.24 15.795 ;
     RECT  2.16 16.065 84.24 16.335 ;
     RECT  2.16 16.605 84.24 16.875 ;
     RECT  2.16 17.145 84.24 17.415 ;
     RECT  2.16 17.685 84.24 17.955 ;
     RECT  2.16 18.225 84.24 18.495 ;
     RECT  2.16 18.765 84.24 19.035 ;
     RECT  2.16 19.305 84.24 19.575 ;
     RECT  2.16 19.845 84.24 20.115 ;
     RECT  2.16 20.385 84.24 20.655 ;
     RECT  2.16 20.925 84.24 21.195 ;
     RECT  2.16 21.465 84.24 21.735 ;
     RECT  2.16 22.005 84.24 22.275 ;
     RECT  2.16 22.545 84.24 22.815 ;
     RECT  2.16 23.085 84.24 23.355 ;
     RECT  2.16 23.625 84.24 23.895 ;
     RECT  2.16 24.165 84.24 24.435 ;
     RECT  2.16 24.705 84.24 24.975 ;
     RECT  2.16 25.245 84.24 25.515 ;
     RECT  2.16 25.785 84.24 26.055 ;
     RECT  2.16 26.325 84.24 26.595 ;
     RECT  2.16 26.865 84.24 27.135 ;
     RECT  2.16 27.405 84.24 27.675 ;
     RECT  2.16 27.945 84.24 28.215 ;
     RECT  2.16 28.485 84.24 28.755 ;
     RECT  2.16 29.025 84.24 29.295 ;
     RECT  2.16 29.565 84.24 29.835 ;
     RECT  2.16 30.105 84.24 30.375 ;
     RECT  2.16 30.645 84.24 30.915 ;
     RECT  2.16 31.185 84.24 31.455 ;
     RECT  2.16 31.725 84.24 31.995 ;
     RECT  2.16 32.265 84.24 32.535 ;
     RECT  2.16 32.805 84.24 33.075 ;
     RECT  2.16 33.345 84.24 33.615 ;
     RECT  2.16 33.885 84.24 34.155 ;
     RECT  2.16 34.425 84.24 34.695 ;
     RECT  2.16 34.965 84.24 35.235 ;
     RECT  2.16 35.505 84.24 35.775 ;
     RECT  2.16 36.045 84.24 36.315 ;
     RECT  2.16 36.585 84.24 36.855 ;
     RECT  2.16 37.125 84.24 37.395 ;
     RECT  2.16 37.665 84.24 37.935 ;
     RECT  2.16 38.205 84.24 38.475 ;
     RECT  2.16 38.745 84.24 39.015 ;
     RECT  2.16 39.285 84.24 39.555 ;
     RECT  2.16 39.825 84.24 40.095 ;
     RECT  2.16 40.365 84.24 40.635 ;
     RECT  2.16 40.905 84.24 41.175 ;
     RECT  2.16 41.445 84.24 41.715 ;
     RECT  2.16 41.985 84.24 42.255 ;
     RECT  2.16 42.525 84.24 42.795 ;
     RECT  2.16 43.065 84.24 43.335 ;
     RECT  2.16 43.605 84.24 43.875 ;
     RECT  2.16 44.145 84.24 44.415 ;
     RECT  2.16 44.685 84.24 44.955 ;
     RECT  2.16 45.225 84.24 45.495 ;
     RECT  2.16 45.765 84.24 46.035 ;
     RECT  2.16 46.305 84.24 46.575 ;
     RECT  2.16 46.845 84.24 47.115 ;
     RECT  2.16 47.385 84.24 47.655 ;
     RECT  2.16 47.925 84.24 48.195 ;
     RECT  2.16 48.465 84.24 48.735 ;
     RECT  2.16 49.005 84.24 49.275 ;
     RECT  2.16 49.545 84.24 49.815 ;
     RECT  2.16 50.085 84.24 50.355 ;
     RECT  2.16 50.625 84.24 50.895 ;
     RECT  2.16 51.165 84.24 51.435 ;
     RECT  2.16 51.705 84.24 51.975 ;
     RECT  2.16 52.245 84.24 52.515 ;
     RECT  2.16 52.785 84.24 53.055 ;
     RECT  2.16 53.325 84.24 53.595 ;
     RECT  2.16 53.865 84.24 54.135 ;
     RECT  2.16 54.405 84.24 54.675 ;
     RECT  2.16 54.945 84.24 55.215 ;
     RECT  2.16 55.485 84.24 55.755 ;
     RECT  2.16 56.025 84.24 56.295 ;
     RECT  2.16 56.565 84.24 56.835 ;
     RECT  2.16 57.105 84.24 57.375 ;
     RECT  2.16 57.645 84.24 57.915 ;
     RECT  2.16 58.185 84.24 58.455 ;
     RECT  2.16 58.725 84.24 58.995 ;
     RECT  2.16 59.265 84.24 59.535 ;
     RECT  2.16 59.805 84.24 60.075 ;
     RECT  2.16 60.345 84.24 60.615 ;
     RECT  2.16 60.885 84.24 61.155 ;
     RECT  2.16 61.425 84.24 61.695 ;
     RECT  2.16 61.965 84.24 62.235 ;
     RECT  2.16 62.505 84.24 62.775 ;
     RECT  2.16 63.045 84.24 63.315 ;
     RECT  2.16 63.585 84.24 63.855 ;
     RECT  2.16 64.125 84.24 64.395 ;
     RECT  2.16 64.665 84.24 64.935 ;
     RECT  2.16 65.205 84.24 65.475 ;
     RECT  2.16 65.745 84.24 66.015 ;
     RECT  2.16 66.285 84.24 66.555 ;
     RECT  2.16 66.825 84.24 67.095 ;
     RECT  2.16 67.365 84.24 67.635 ;
     RECT  2.16 67.905 84.24 68.175 ;
     RECT  2.16 68.445 84.24 68.715 ;
     RECT  2.16 68.985 84.24 69.255 ;
     RECT  2.16 69.525 84.24 69.795 ;
     RECT  2.16 70.065 84.24 70.335 ;
     RECT  2.16 70.605 84.24 70.875 ;
     RECT  2.16 71.145 84.24 71.415 ;
     RECT  2.16 71.685 84.24 71.955 ;
     RECT  2.16 72.225 84.24 72.495 ;
     RECT  2.16 72.765 84.24 73.035 ;
     RECT  2.16 73.305 84.24 73.575 ;
     RECT  2.16 73.845 84.24 74.115 ;
     RECT  2.16 74.385 84.24 74.655 ;
     RECT  2.16 74.925 84.24 75.195 ;
     RECT  2.16 75.465 84.24 75.6 ;
    LAYER RVTP ;
     RECT  2.16 2.295 84.24 2.565 ;
     RECT  2.16 2.835 84.24 3.105 ;
     RECT  2.16 3.375 84.24 3.645 ;
     RECT  2.16 3.915 84.24 4.185 ;
     RECT  2.16 4.455 84.24 4.725 ;
     RECT  2.16 4.995 84.24 5.265 ;
     RECT  2.16 5.535 84.24 5.805 ;
     RECT  2.16 6.075 84.24 6.345 ;
     RECT  2.16 6.615 84.24 6.885 ;
     RECT  2.16 7.155 84.24 7.425 ;
     RECT  2.16 7.695 84.24 7.965 ;
     RECT  2.16 8.235 84.24 8.505 ;
     RECT  2.16 8.775 84.24 9.045 ;
     RECT  2.16 9.315 84.24 9.585 ;
     RECT  2.16 9.855 84.24 10.125 ;
     RECT  2.16 10.395 84.24 10.665 ;
     RECT  2.16 10.935 84.24 11.205 ;
     RECT  2.16 11.475 84.24 11.745 ;
     RECT  2.16 12.015 84.24 12.285 ;
     RECT  2.16 12.555 84.24 12.825 ;
     RECT  2.16 13.095 84.24 13.365 ;
     RECT  2.16 13.635 84.24 13.905 ;
     RECT  2.16 14.175 84.24 14.445 ;
     RECT  2.16 14.715 84.24 14.985 ;
     RECT  2.16 15.255 84.24 15.525 ;
     RECT  2.16 15.795 84.24 16.065 ;
     RECT  2.16 16.335 84.24 16.605 ;
     RECT  2.16 16.875 84.24 17.145 ;
     RECT  2.16 17.415 84.24 17.685 ;
     RECT  2.16 17.955 84.24 18.225 ;
     RECT  2.16 18.495 84.24 18.765 ;
     RECT  2.16 19.035 84.24 19.305 ;
     RECT  2.16 19.575 84.24 19.845 ;
     RECT  2.16 20.115 84.24 20.385 ;
     RECT  2.16 20.655 84.24 20.925 ;
     RECT  2.16 21.195 84.24 21.465 ;
     RECT  2.16 21.735 84.24 22.005 ;
     RECT  2.16 22.275 84.24 22.545 ;
     RECT  2.16 22.815 84.24 23.085 ;
     RECT  2.16 23.355 84.24 23.625 ;
     RECT  2.16 23.895 84.24 24.165 ;
     RECT  2.16 24.435 84.24 24.705 ;
     RECT  2.16 24.975 84.24 25.245 ;
     RECT  2.16 25.515 84.24 25.785 ;
     RECT  2.16 26.055 84.24 26.325 ;
     RECT  2.16 26.595 84.24 26.865 ;
     RECT  2.16 27.135 84.24 27.405 ;
     RECT  2.16 27.675 84.24 27.945 ;
     RECT  2.16 28.215 84.24 28.485 ;
     RECT  2.16 28.755 84.24 29.025 ;
     RECT  2.16 29.295 84.24 29.565 ;
     RECT  2.16 29.835 84.24 30.105 ;
     RECT  2.16 30.375 84.24 30.645 ;
     RECT  2.16 30.915 84.24 31.185 ;
     RECT  2.16 31.455 84.24 31.725 ;
     RECT  2.16 31.995 84.24 32.265 ;
     RECT  2.16 32.535 84.24 32.805 ;
     RECT  2.16 33.075 84.24 33.345 ;
     RECT  2.16 33.615 84.24 33.885 ;
     RECT  2.16 34.155 84.24 34.425 ;
     RECT  2.16 34.695 84.24 34.965 ;
     RECT  2.16 35.235 84.24 35.505 ;
     RECT  2.16 35.775 84.24 36.045 ;
     RECT  2.16 36.315 84.24 36.585 ;
     RECT  2.16 36.855 84.24 37.125 ;
     RECT  2.16 37.395 84.24 37.665 ;
     RECT  2.16 37.935 84.24 38.205 ;
     RECT  2.16 38.475 84.24 38.745 ;
     RECT  2.16 39.015 84.24 39.285 ;
     RECT  2.16 39.555 84.24 39.825 ;
     RECT  2.16 40.095 84.24 40.365 ;
     RECT  2.16 40.635 84.24 40.905 ;
     RECT  2.16 41.175 84.24 41.445 ;
     RECT  2.16 41.715 84.24 41.985 ;
     RECT  2.16 42.255 84.24 42.525 ;
     RECT  2.16 42.795 84.24 43.065 ;
     RECT  2.16 43.335 84.24 43.605 ;
     RECT  2.16 43.875 84.24 44.145 ;
     RECT  2.16 44.415 84.24 44.685 ;
     RECT  2.16 44.955 84.24 45.225 ;
     RECT  2.16 45.495 84.24 45.765 ;
     RECT  2.16 46.035 84.24 46.305 ;
     RECT  2.16 46.575 84.24 46.845 ;
     RECT  2.16 47.115 84.24 47.385 ;
     RECT  2.16 47.655 84.24 47.925 ;
     RECT  2.16 48.195 84.24 48.465 ;
     RECT  2.16 48.735 84.24 49.005 ;
     RECT  2.16 49.275 84.24 49.545 ;
     RECT  2.16 49.815 84.24 50.085 ;
     RECT  2.16 50.355 84.24 50.625 ;
     RECT  2.16 50.895 84.24 51.165 ;
     RECT  2.16 51.435 84.24 51.705 ;
     RECT  2.16 51.975 84.24 52.245 ;
     RECT  2.16 52.515 84.24 52.785 ;
     RECT  2.16 53.055 84.24 53.325 ;
     RECT  2.16 53.595 84.24 53.865 ;
     RECT  2.16 54.135 84.24 54.405 ;
     RECT  2.16 54.675 84.24 54.945 ;
     RECT  2.16 55.215 84.24 55.485 ;
     RECT  2.16 55.755 84.24 56.025 ;
     RECT  2.16 56.295 84.24 56.565 ;
     RECT  2.16 56.835 84.24 57.105 ;
     RECT  2.16 57.375 84.24 57.645 ;
     RECT  2.16 57.915 84.24 58.185 ;
     RECT  2.16 58.455 84.24 58.725 ;
     RECT  2.16 58.995 84.24 59.265 ;
     RECT  2.16 59.535 84.24 59.805 ;
     RECT  2.16 60.075 84.24 60.345 ;
     RECT  2.16 60.615 84.24 60.885 ;
     RECT  2.16 61.155 84.24 61.425 ;
     RECT  2.16 61.695 84.24 61.965 ;
     RECT  2.16 62.235 84.24 62.505 ;
     RECT  2.16 62.775 84.24 63.045 ;
     RECT  2.16 63.315 84.24 63.585 ;
     RECT  2.16 63.855 84.24 64.125 ;
     RECT  2.16 64.395 84.24 64.665 ;
     RECT  2.16 64.935 84.24 65.205 ;
     RECT  2.16 65.475 84.24 65.745 ;
     RECT  2.16 66.015 84.24 66.285 ;
     RECT  2.16 66.555 84.24 66.825 ;
     RECT  2.16 67.095 84.24 67.365 ;
     RECT  2.16 67.635 84.24 67.905 ;
     RECT  2.16 68.175 84.24 68.445 ;
     RECT  2.16 68.715 84.24 68.985 ;
     RECT  2.16 69.255 84.24 69.525 ;
     RECT  2.16 69.795 84.24 70.065 ;
     RECT  2.16 70.335 84.24 70.605 ;
     RECT  2.16 70.875 84.24 71.145 ;
     RECT  2.16 71.415 84.24 71.685 ;
     RECT  2.16 71.955 84.24 72.225 ;
     RECT  2.16 72.495 84.24 72.765 ;
     RECT  2.16 73.035 84.24 73.305 ;
     RECT  2.16 73.575 84.24 73.845 ;
     RECT  2.16 74.115 84.24 74.385 ;
     RECT  2.16 74.655 84.24 74.925 ;
     RECT  2.16 75.195 84.24 75.465 ;
    LAYER M1 ;
     RECT  2.16 2.151 84.24 75.609 ;
    LAYER M2 ;
     RECT  0.067 41.886 0.103 41.904 ;
     RECT  0.103 39.681 0.139 39.699 ;
     RECT  0.103 41.346 0.139 41.904 ;
     RECT  0.139 35.28 0.175 35.802 ;
     RECT  0.139 38.016 0.175 38.16 ;
     RECT  0.139 39.681 0.175 42.624 ;
     RECT  0.175 39.681 0.211 42.786 ;
     RECT  0.211 39.096 0.239 42.786 ;
     RECT  0.175 35.01 0.247 35.802 ;
     RECT  0.239 39.096 0.247 41.436 ;
     RECT  0.067 44.154 0.247 44.172 ;
     RECT  0.175 36.936 0.283 38.16 ;
     RECT  0.247 39.024 0.283 41.436 ;
     RECT  0.247 43.812 0.283 44.172 ;
     RECT  0.283 36.936 0.455 41.436 ;
     RECT  0.247 34.74 0.463 35.802 ;
     RECT  0.239 42.228 0.499 42.786 ;
     RECT  0.283 43.542 0.499 44.172 ;
     RECT  0.463 34.74 0.535 36.108 ;
     RECT  0.455 36.936 0.535 38.034 ;
     RECT  0.535 34.74 0.599 38.034 ;
     RECT  0.499 42.228 0.823 44.172 ;
     RECT  0.823 42.228 1.147 44.37 ;
     RECT  0.599 34.74 2.16 36.954 ;
     RECT  0.599 38.016 2.16 38.034 ;
     RECT  0.455 38.79 2.16 41.436 ;
     RECT  1.147 42.228 2.16 44.64 ;
     RECT  2.16 2.151 27.283 75.609 ;
     RECT  27.283 1.998 28.967 75.609 ;
     RECT  28.967 2.106 29.003 75.609 ;
     RECT  29.003 2.151 30.451 75.609 ;
     RECT  30.451 2.106 31.811 75.609 ;
     RECT  32.071 1.152 32.279 1.17 ;
     RECT  33.583 0.531 33.907 0.549 ;
     RECT  31.811 2.151 34.195 75.609 ;
     RECT  33.907 0.306 35.411 0.549 ;
     RECT  34.195 2.034 35.447 75.609 ;
     RECT  35.411 0.306 35.519 0.324 ;
     RECT  35.447 2.106 35.663 75.609 ;
     RECT  35.663 2.151 84.24 75.609 ;
     RECT  84.24 39.528 85.487 39.546 ;
    LAYER M3 ;
     RECT  30.78 0.091 30.798 0.139 ;
     RECT  35.604 0.091 35.622 0.139 ;
     RECT  35.352 0.139 35.622 0.187 ;
     RECT  33.48 0.091 33.498 0.283 ;
     RECT  35.352 0.187 35.91 0.283 ;
     RECT  28.548 0.091 28.566 0.523 ;
     RECT  33.48 0.283 33.93 0.523 ;
     RECT  27.936 0.523 28.602 0.571 ;
     RECT  29.736 0.523 30.042 0.571 ;
     RECT  33.48 0.523 34.038 0.619 ;
     RECT  33.48 0.619 34.182 1.099 ;
     RECT  32.076 0.139 32.526 1.175 ;
     RECT  27.936 0.571 30.042 1.723 ;
     RECT  30.78 0.139 31.014 1.723 ;
     RECT  32.256 1.175 32.526 1.723 ;
     RECT  33.48 1.099 34.29 1.723 ;
     RECT  32.256 1.723 34.29 1.771 ;
     RECT  35.352 0.283 36.522 1.771 ;
     RECT  27.936 1.723 31.05 1.993 ;
     RECT  32.256 1.771 36.522 2.101 ;
     RECT  27.288 1.993 31.05 2.143 ;
     RECT  43.056 0.091 43.074 2.143 ;
     RECT  26.715 2.143 31.05 2.191 ;
     RECT  31.788 2.101 36.522 2.191 ;
     RECT  42.915 2.143 43.074 2.191 ;
     RECT  42.915 2.191 43.794 2.227 ;
     RECT  42.915 2.227 44.514 2.291 ;
     RECT  26.715 2.191 36.522 2.371 ;
     RECT  42.915 2.291 43.197 2.371 ;
     RECT  2.415 2.143 2.505 2.413 ;
     RECT  5.115 2.143 5.205 2.413 ;
     RECT  7.815 2.143 7.905 2.413 ;
     RECT  10.515 2.143 10.605 2.413 ;
     RECT  13.215 2.143 13.305 2.413 ;
     RECT  15.915 2.143 16.005 2.413 ;
     RECT  18.615 2.143 18.705 2.413 ;
     RECT  21.315 2.143 21.405 2.413 ;
     RECT  24.015 2.143 24.105 2.413 ;
     RECT  37.515 2.143 37.605 2.413 ;
     RECT  40.215 2.143 40.305 2.413 ;
     RECT  45.615 2.143 45.705 2.413 ;
     RECT  48.315 2.143 48.405 2.413 ;
     RECT  51.015 2.143 51.105 2.413 ;
     RECT  53.715 2.143 53.805 2.413 ;
     RECT  56.415 2.143 56.505 2.413 ;
     RECT  59.115 2.143 59.205 2.413 ;
     RECT  61.815 2.143 61.905 2.413 ;
     RECT  64.515 2.143 64.605 2.413 ;
     RECT  67.215 2.143 67.305 2.413 ;
     RECT  69.915 2.143 70.005 2.413 ;
     RECT  72.615 2.143 72.705 2.413 ;
     RECT  75.315 2.143 75.405 2.413 ;
     RECT  78.015 2.143 78.105 2.413 ;
     RECT  80.715 2.143 80.805 2.413 ;
     RECT  83.415 2.143 83.505 2.413 ;
     RECT  26.715 2.371 36.666 2.461 ;
     RECT  42.912 2.371 43.197 2.525 ;
     RECT  26.388 2.461 36.666 2.569 ;
     RECT  37.515 2.413 37.797 2.569 ;
     RECT  26.388 2.569 37.797 2.795 ;
     RECT  26.64 2.795 37.797 3.479 ;
     RECT  26.64 3.479 26.997 4.801 ;
     RECT  27.828 3.479 37.797 4.801 ;
     RECT  26.64 4.801 37.797 4.891 ;
     RECT  24.015 2.413 24.297 5.071 ;
     RECT  40.215 2.413 40.497 5.071 ;
     RECT  26.64 4.891 38.178 5.225 ;
     RECT  24.015 5.071 24.678 5.269 ;
     RECT  40.215 5.071 40.59 5.431 ;
     RECT  41.58 5.341 41.886 5.431 ;
     RECT  25.56 5.071 25.83 5.575 ;
     RECT  26.64 5.225 37.962 5.575 ;
     RECT  42.915 2.525 43.197 5.575 ;
     RECT  44.496 2.291 44.514 5.611 ;
     RECT  24.015 5.269 24.75 5.701 ;
     RECT  25.56 5.575 37.962 5.701 ;
     RECT  44.064 5.611 44.514 5.701 ;
     RECT  40.104 5.431 41.886 5.737 ;
     RECT  42.732 5.575 43.197 5.737 ;
     RECT  40.104 5.737 43.254 5.773 ;
     RECT  44.064 5.701 44.802 5.773 ;
     RECT  19.944 5.341 19.962 5.845 ;
     RECT  38.736 5.431 38.754 5.845 ;
     RECT  46.764 5.809 46.782 5.881 ;
     RECT  48.315 2.413 48.597 5.881 ;
     RECT  24.015 5.701 37.962 5.971 ;
     RECT  19.872 5.845 19.962 5.999 ;
     RECT  23.904 5.971 37.962 5.999 ;
     RECT  38.736 5.845 38.862 6.035 ;
     RECT  37.26 5.999 37.962 6.043 ;
     RECT  38.736 6.035 38.79 6.043 ;
     RECT  40.104 5.773 44.802 6.043 ;
     RECT  40.068 6.043 44.802 6.079 ;
     RECT  50.004 5.881 50.022 6.115 ;
     RECT  18.615 2.413 18.897 6.151 ;
     RECT  23.904 5.999 36.45 6.151 ;
     RECT  45.615 2.413 45.897 6.151 ;
     RECT  46.764 5.881 47.322 6.151 ;
     RECT  49.968 6.115 50.022 6.151 ;
     RECT  22.752 6.151 22.77 6.385 ;
     RECT  23.832 6.151 36.45 6.385 ;
     RECT  40.068 6.079 44.838 6.421 ;
     RECT  45.615 6.151 47.394 6.421 ;
     RECT  40.068 6.421 47.43 6.511 ;
     RECT  39.636 6.511 47.43 6.547 ;
     RECT  20.16 6.151 20.178 6.619 ;
     RECT  22.752 6.385 22.878 6.619 ;
     RECT  23.688 6.385 36.45 6.619 ;
     RECT  49.968 6.151 50.274 6.655 ;
     RECT  51.015 2.413 51.297 6.655 ;
     RECT  39.564 6.547 47.43 6.683 ;
     RECT  18.576 6.151 18.897 6.691 ;
     RECT  20.16 6.619 20.43 6.691 ;
     RECT  49.968 6.655 51.297 6.781 ;
     RECT  49.896 6.781 51.297 6.808 ;
     RECT  22.752 6.619 36.45 6.809 ;
     RECT  49.608 6.808 51.297 6.809 ;
     RECT  23.688 6.809 36.45 6.845 ;
     RECT  23.976 6.845 36.45 6.889 ;
     RECT  37.26 6.043 38.79 6.889 ;
     RECT  39.564 6.683 44.622 6.889 ;
     RECT  20.16 6.691 20.502 6.925 ;
     RECT  48.24 5.881 48.597 6.925 ;
     RECT  49.608 6.809 50.022 6.925 ;
     RECT  45.615 6.683 47.43 6.961 ;
     RECT  48.24 6.925 50.022 6.961 ;
     RECT  45.615 6.961 50.022 7.187 ;
     RECT  17.784 6.241 17.802 7.231 ;
     RECT  21.315 2.413 21.597 7.231 ;
     RECT  22.752 6.809 22.914 7.231 ;
     RECT  15.915 2.413 16.197 7.321 ;
     RECT  17.496 7.231 17.802 7.321 ;
     RECT  18.576 6.691 19.098 7.321 ;
     RECT  52.776 7.087 52.794 7.349 ;
     RECT  47.52 7.187 50.022 7.385 ;
     RECT  53.715 2.413 53.997 7.393 ;
     RECT  17.496 7.321 19.098 7.429 ;
     RECT  19.98 6.925 20.502 7.429 ;
     RECT  21.315 7.231 22.914 7.429 ;
     RECT  15.915 7.321 16.686 7.501 ;
     RECT  17.496 7.429 22.914 7.501 ;
     RECT  15.915 7.501 22.914 7.591 ;
     RECT  23.976 6.889 44.622 7.591 ;
     RECT  45.615 7.187 46.782 7.771 ;
     RECT  47.52 7.385 48.597 7.799 ;
     RECT  14.796 7.591 22.914 7.933 ;
     RECT  45.432 7.771 46.782 7.933 ;
     RECT  47.52 7.799 47.574 7.933 ;
     RECT  23.904 7.591 44.622 8.005 ;
     RECT  14.472 7.933 22.914 8.041 ;
     RECT  23.652 8.005 44.622 8.155 ;
     RECT  45.432 7.933 47.574 8.155 ;
     RECT  53.352 7.393 53.997 8.203 ;
     RECT  13.215 2.413 13.497 8.275 ;
     RECT  14.436 8.041 22.914 8.275 ;
     RECT  53.28 8.203 53.997 8.275 ;
     RECT  13.215 8.275 22.914 8.311 ;
     RECT  23.652 8.155 47.574 8.311 ;
     RECT  13.215 8.311 47.574 8.401 ;
     RECT  12.564 8.401 47.574 8.545 ;
     RECT  48.315 7.799 48.597 8.545 ;
     RECT  12.564 8.545 48.597 8.779 ;
     RECT  12.564 8.779 48.798 8.813 ;
     RECT  51.015 6.809 51.297 8.851 ;
     RECT  48.315 8.813 48.798 8.941 ;
     RECT  49.608 7.385 50.022 8.941 ;
     RECT  48.315 8.941 50.022 8.977 ;
     RECT  12.564 8.813 47.538 9.067 ;
     RECT  12.492 9.067 47.538 9.085 ;
     RECT  48.315 8.977 50.058 9.085 ;
     RECT  51.015 8.851 51.426 9.085 ;
     RECT  52.848 8.275 53.997 9.163 ;
     RECT  12.168 9.085 47.538 9.239 ;
     RECT  52.38 9.163 53.997 9.239 ;
     RECT  10.515 2.413 10.797 9.355 ;
     RECT  12.168 9.239 44.802 9.355 ;
     RECT  10.515 9.355 10.926 9.391 ;
     RECT  11.916 9.355 44.802 9.391 ;
     RECT  11.664 9.391 44.802 9.581 ;
     RECT  10.476 9.391 10.926 9.643 ;
     RECT  11.664 9.581 38.502 9.643 ;
     RECT  9.72 9.643 9.738 9.661 ;
     RECT  10.476 9.643 38.502 9.661 ;
     RECT  9.72 9.661 38.502 9.883 ;
     RECT  45.615 9.239 47.538 9.931 ;
     RECT  48.315 9.085 51.426 9.931 ;
     RECT  7.815 2.413 8.097 10.219 ;
     RECT  9.432 9.883 38.502 10.319 ;
     RECT  9.432 10.319 38.394 10.355 ;
     RECT  7.815 10.219 8.37 10.471 ;
     RECT  9.432 10.355 38.322 10.471 ;
     RECT  7.815 10.471 38.322 10.939 ;
     RECT  7.704 10.939 38.322 11.281 ;
     RECT  39.24 9.581 44.802 11.281 ;
     RECT  7.704 11.281 44.802 11.821 ;
     RECT  6.768 11.941 6.786 11.981 ;
     RECT  7.524 11.821 44.802 12.091 ;
     RECT  53.1 9.239 53.997 12.361 ;
     RECT  52.38 12.361 53.997 12.413 ;
     RECT  6.84 12.091 44.802 12.479 ;
     RECT  6.84 12.479 44.622 12.587 ;
     RECT  6.84 12.587 14.346 12.845 ;
     RECT  6.84 12.845 14.274 12.901 ;
     RECT  6.804 12.901 14.274 13.027 ;
     RECT  6.408 13.027 14.274 13.085 ;
     RECT  15.156 12.587 44.622 13.567 ;
     RECT  6.48 13.085 14.274 13.711 ;
     RECT  15.084 13.567 44.622 13.711 ;
     RECT  45.615 9.931 51.426 13.711 ;
     RECT  6.48 13.711 14.31 13.945 ;
     RECT  15.084 13.711 51.426 13.945 ;
     RECT  5.115 2.413 5.397 14.251 ;
     RECT  5.115 14.251 5.706 14.477 ;
     RECT  6.48 13.945 51.426 14.521 ;
     RECT  6.336 14.521 51.426 14.675 ;
     RECT  5.115 14.477 5.562 14.813 ;
     RECT  6.624 14.675 51.426 15.025 ;
     RECT  6.624 15.025 51.75 15.115 ;
     RECT  52.668 12.413 53.997 15.115 ;
     RECT  6.624 15.115 53.997 15.287 ;
     RECT  6.624 15.287 25.506 15.601 ;
     RECT  6.3 15.601 25.506 15.755 ;
     RECT  5.115 14.813 5.397 16.405 ;
     RECT  6.336 15.755 25.506 16.411 ;
     RECT  26.244 15.287 53.997 16.411 ;
     RECT  5.115 16.405 5.49 16.501 ;
     RECT  6.336 16.411 53.997 16.501 ;
     RECT  5.115 16.501 53.997 16.835 ;
     RECT  6.228 16.835 53.997 17.077 ;
     RECT  6.228 17.077 54.054 17.339 ;
     RECT  6.444 17.339 54.054 17.455 ;
     RECT  6.444 17.455 54.558 17.645 ;
     RECT  17.136 17.645 54.558 17.753 ;
     RECT  22.32 17.753 54.558 18.149 ;
     RECT  6.444 17.645 16.362 18.391 ;
     RECT  17.136 17.753 21.597 18.391 ;
     RECT  6.444 18.391 21.597 18.535 ;
     RECT  22.32 18.149 54.27 18.535 ;
     RECT  5.115 16.835 5.397 18.571 ;
     RECT  6.444 18.535 54.27 18.571 ;
     RECT  5.115 18.571 54.27 18.725 ;
     RECT  5.115 18.725 5.634 18.833 ;
     RECT  6.588 18.725 54.27 19.381 ;
     RECT  6.588 19.381 54.342 19.643 ;
     RECT  6.588 19.643 54.306 19.813 ;
     RECT  5.115 18.833 5.526 20.149 ;
     RECT  6.3 19.813 54.306 20.149 ;
     RECT  5.115 20.149 54.306 20.389 ;
     RECT  5.115 20.389 54.45 20.579 ;
     RECT  5.115 20.579 54.306 20.615 ;
     RECT  5.115 20.615 54.09 20.621 ;
     RECT  5.115 20.621 19.098 21.397 ;
     RECT  19.872 20.621 54.09 21.397 ;
     RECT  5.115 21.397 54.09 21.691 ;
     RECT  5.076 21.691 54.09 21.965 ;
     RECT  4.212 22.219 4.23 22.469 ;
     RECT  5.076 21.965 32.922 22.549 ;
     RECT  5.004 22.549 32.922 22.711 ;
     RECT  33.804 21.965 54.09 22.819 ;
     RECT  4.68 22.711 32.922 23.017 ;
     RECT  33.804 22.819 54.126 23.017 ;
     RECT  4.68 23.017 54.126 23.045 ;
     RECT  4.896 23.045 54.126 23.279 ;
     RECT  3.996 23.521 4.158 23.597 ;
     RECT  4.896 23.279 35.334 23.693 ;
     RECT  4.14 23.597 4.158 23.927 ;
     RECT  4.896 23.693 35.262 24.205 ;
     RECT  4.356 24.205 35.262 24.269 ;
     RECT  4.68 24.269 35.262 24.475 ;
     RECT  36.144 23.279 54.126 24.475 ;
     RECT  4.68 24.475 54.198 24.943 ;
     RECT  3.78 25.045 3.798 25.051 ;
     RECT  4.68 24.943 54.342 25.051 ;
     RECT  3.78 25.051 54.342 25.085 ;
     RECT  4.464 25.085 54.342 25.169 ;
     RECT  4.464 25.169 54.198 25.205 ;
     RECT  4.464 25.205 54.126 25.709 ;
     RECT  4.5 25.709 54.126 26.249 ;
     RECT  4.5 26.249 54.09 26.669 ;
     RECT  4.644 26.669 54.09 27.175 ;
     RECT  4.644 27.175 54.234 27.329 ;
     RECT  3.6 27.307 3.618 27.365 ;
     RECT  4.644 27.329 54.09 27.595 ;
     RECT  4.464 27.595 54.09 27.965 ;
     RECT  4.788 27.965 54.09 28.481 ;
     RECT  4.788 28.481 20.214 29.335 ;
     RECT  20.952 28.481 54.09 29.335 ;
     RECT  4.788 29.335 54.09 29.731 ;
     RECT  4.356 29.731 54.09 30.065 ;
     RECT  4.644 30.065 54.09 30.299 ;
     RECT  4.896 30.299 54.09 30.407 ;
     RECT  49.788 30.407 54.09 30.847 ;
     RECT  55.62 30.415 55.638 30.847 ;
     RECT  49.788 30.847 54.522 30.883 ;
     RECT  55.44 30.847 55.638 30.883 ;
     RECT  56.415 2.413 56.697 30.883 ;
     RECT  59.115 2.413 59.397 30.919 ;
     RECT  4.896 30.407 49.05 31.153 ;
     RECT  49.788 30.883 56.697 31.153 ;
     RECT  57.456 30.859 57.474 31.153 ;
     RECT  4.896 31.153 57.474 31.495 ;
     RECT  4.896 31.495 57.546 31.723 ;
     RECT  4.896 31.723 57.834 31.801 ;
     RECT  4.896 31.801 57.906 31.927 ;
     RECT  61.815 2.413 62.097 31.927 ;
     RECT  4.896 31.927 57.978 32.011 ;
     RECT  4.896 32.011 58.266 32.161 ;
     RECT  59.115 30.919 59.922 32.161 ;
     RECT  4.896 32.161 59.922 32.233 ;
     RECT  64.515 2.413 64.797 32.431 ;
     RECT  64.515 32.431 65.034 32.575 ;
     RECT  4.896 32.233 60.066 32.611 ;
     RECT  64.44 32.575 65.034 32.845 ;
     RECT  65.844 32.809 65.862 32.845 ;
     RECT  4.896 32.611 60.606 33.043 ;
     RECT  4.896 33.043 60.678 33.079 ;
     RECT  4.896 33.079 60.75 33.389 ;
     RECT  54.72 33.389 60.75 33.413 ;
     RECT  54.792 33.413 60.75 33.539 ;
     RECT  54.936 33.539 60.75 33.547 ;
     RECT  61.815 31.927 62.442 33.547 ;
     RECT  63.612 32.269 63.63 33.691 ;
     RECT  54.936 33.547 62.442 34.159 ;
     RECT  63.432 33.691 63.63 34.159 ;
     RECT  2.415 2.413 2.697 34.195 ;
     RECT  54.936 34.159 63.63 34.349 ;
     RECT  4.896 33.389 53.997 34.393 ;
     RECT  2.415 34.195 2.79 34.465 ;
     RECT  4.644 34.393 53.997 34.465 ;
     RECT  54.936 34.349 63.45 34.465 ;
     RECT  2.415 34.465 2.898 34.501 ;
     RECT  4.608 34.465 53.997 34.501 ;
     RECT  4.608 34.501 54.054 34.591 ;
     RECT  4.104 34.591 54.054 34.699 ;
     RECT  54.828 34.465 63.45 34.699 ;
     RECT  64.44 32.845 65.862 34.699 ;
     RECT  4.104 34.699 63.45 34.735 ;
     RECT  2.415 34.501 3.042 34.771 ;
     RECT  2.415 34.771 3.114 34.861 ;
     RECT  3.924 34.735 63.45 34.861 ;
     RECT  0.252 34.735 0.27 35.005 ;
     RECT  0.18 35.005 0.27 35.041 ;
     RECT  2.415 34.861 63.45 35.159 ;
     RECT  0.18 35.041 0.486 35.167 ;
     RECT  2.415 35.159 17.334 35.167 ;
     RECT  0.18 35.167 0.522 35.239 ;
     RECT  0.18 35.239 0.558 35.275 ;
     RECT  18.108 35.159 63.45 35.323 ;
     RECT  18.108 35.323 63.486 35.437 ;
     RECT  64.224 34.699 65.862 35.437 ;
     RECT  18.108 35.437 65.862 35.501 ;
     RECT  2.376 35.167 17.334 35.509 ;
     RECT  2.34 35.509 17.334 35.581 ;
     RECT  2.304 35.581 17.334 36.113 ;
     RECT  0.144 35.275 0.558 36.173 ;
     RECT  18.18 35.501 65.862 36.311 ;
     RECT  2.304 36.113 17.262 36.625 ;
     RECT  18.252 36.311 65.862 37.085 ;
     RECT  2.232 36.625 17.262 37.093 ;
     RECT  18.252 37.085 53.997 37.093 ;
     RECT  0.18 36.173 0.558 37.147 ;
     RECT  0.144 37.147 0.558 37.597 ;
     RECT  67.215 2.413 67.497 37.705 ;
     RECT  67.176 37.705 67.497 37.859 ;
     RECT  2.232 37.093 53.997 37.903 ;
     RECT  54.72 37.085 65.862 37.903 ;
     RECT  2.232 37.903 65.862 37.967 ;
     RECT  68.94 37.867 68.958 38.003 ;
     RECT  86.292 38.203 86.31 38.381 ;
     RECT  0.144 37.597 0.594 38.429 ;
     RECT  2.304 37.967 65.862 38.471 ;
     RECT  0.18 38.429 0.594 38.683 ;
     RECT  2.34 38.471 65.862 38.821 ;
     RECT  67.215 37.859 67.497 38.821 ;
     RECT  2.34 38.821 67.497 38.939 ;
     RECT  2.34 38.939 66.078 38.975 ;
     RECT  49.356 38.975 66.078 39.209 ;
     RECT  82.332 37.867 82.35 39.209 ;
     RECT  83.415 2.413 83.697 39.217 ;
     RECT  0.18 38.683 0.63 39.317 ;
     RECT  2.34 38.975 48.597 39.355 ;
     RECT  83.415 39.217 84.042 39.479 ;
     RECT  85.464 39.355 85.482 39.551 ;
     RECT  0.18 39.317 0.522 39.595 ;
     RECT  0.108 39.595 0.522 39.704 ;
     RECT  2.304 39.355 48.597 39.757 ;
     RECT  49.356 39.209 65.862 39.757 ;
     RECT  2.304 39.757 65.862 40.019 ;
     RECT  54.936 40.019 65.466 40.289 ;
     RECT  2.304 40.019 54.126 40.369 ;
     RECT  2.268 40.369 54.126 40.801 ;
     RECT  54.936 40.289 65.142 40.801 ;
     RECT  2.268 40.801 65.142 40.865 ;
     RECT  0.144 39.704 0.522 41.323 ;
     RECT  0.144 41.323 0.594 41.341 ;
     RECT  2.268 40.865 51.822 41.419 ;
     RECT  0.108 41.341 0.846 41.659 ;
     RECT  1.728 41.419 51.822 41.683 ;
     RECT  52.704 40.865 65.142 41.683 ;
     RECT  1.728 41.683 65.142 41.783 ;
     RECT  0.108 41.659 0.918 41.881 ;
     RECT  0.072 41.881 0.918 41.899 ;
     RECT  1.728 41.783 43.794 41.899 ;
     RECT  44.532 41.783 65.142 42.061 ;
     RECT  44.532 42.061 65.214 42.179 ;
     RECT  0.072 41.899 43.794 42.593 ;
     RECT  17.82 42.593 43.794 42.871 ;
     RECT  44.532 42.179 65.142 42.871 ;
     RECT  65.88 42.799 65.898 42.989 ;
     RECT  17.82 42.871 65.142 42.997 ;
     RECT  17.82 42.997 65.502 43.295 ;
     RECT  17.82 43.295 65.25 43.411 ;
     RECT  17.784 43.411 65.25 43.529 ;
     RECT  17.784 43.529 65.142 43.601 ;
     RECT  52.38 43.601 65.142 43.673 ;
     RECT  0.072 42.593 17.046 43.681 ;
     RECT  17.784 43.601 51.642 43.681 ;
     RECT  0.072 43.681 51.642 43.835 ;
     RECT  0.828 43.835 51.642 44.105 ;
     RECT  4.572 44.105 51.642 44.141 ;
     RECT  0.072 43.835 0.09 44.177 ;
     RECT  2.34 44.105 3.834 44.249 ;
     RECT  5.115 44.141 51.642 44.249 ;
     RECT  3.816 44.249 3.834 44.339 ;
     RECT  5.115 44.249 14.274 44.339 ;
     RECT  0.828 44.105 1.17 44.375 ;
     RECT  2.34 44.249 2.862 44.375 ;
     RECT  5.115 44.339 5.49 44.375 ;
     RECT  7.668 44.339 14.274 44.375 ;
     RECT  7.776 44.375 8.097 44.381 ;
     RECT  6.336 44.339 6.354 44.411 ;
     RECT  8.856 44.375 14.274 44.411 ;
     RECT  15.048 44.249 51.642 44.411 ;
     RECT  9.144 44.411 14.274 44.447 ;
     RECT  17.424 44.411 51.642 44.483 ;
     RECT  52.74 43.673 55.134 44.491 ;
     RECT  55.872 43.673 65.142 44.491 ;
     RECT  17.424 44.483 43.83 44.519 ;
     RECT  44.748 44.483 51.642 44.581 ;
     RECT  52.38 44.491 65.43 44.581 ;
     RECT  12.6 44.447 14.274 44.609 ;
     RECT  1.152 44.375 1.17 44.645 ;
     RECT  9.144 44.447 11.862 44.717 ;
     RECT  2.34 44.375 2.697 44.789 ;
     RECT  9.144 44.717 9.522 44.879 ;
     RECT  20.196 44.519 43.83 44.879 ;
     RECT  9.144 44.879 9.414 44.909 ;
     RECT  15.408 44.411 16.686 45.149 ;
     RECT  15.408 45.149 16.506 45.185 ;
     RECT  12.6 44.609 14.094 45.221 ;
     RECT  10.26 44.717 11.862 45.301 ;
     RECT  20.34 44.879 43.83 45.301 ;
     RECT  44.748 44.581 65.43 45.301 ;
     RECT  12.852 45.221 14.094 45.355 ;
     RECT  15.408 45.185 16.197 45.355 ;
     RECT  10.26 45.301 12.078 45.419 ;
     RECT  12.852 45.355 16.197 45.455 ;
     RECT  20.34 45.301 65.43 45.455 ;
     RECT  12.852 45.455 14.85 45.563 ;
     RECT  17.424 44.519 19.458 45.661 ;
     RECT  20.34 45.455 62.91 45.661 ;
     RECT  17.424 45.661 62.91 45.841 ;
     RECT  17.352 45.841 62.91 46.075 ;
     RECT  15.66 45.455 16.197 46.109 ;
     RECT  17.208 46.075 62.91 46.201 ;
     RECT  63.72 45.455 65.43 46.201 ;
     RECT  10.26 45.419 10.797 46.499 ;
     RECT  17.208 46.201 65.43 46.499 ;
     RECT  10.515 46.499 10.797 46.651 ;
     RECT  11.736 45.419 12.078 46.651 ;
     RECT  12.852 45.563 14.67 46.651 ;
     RECT  10.515 46.651 15.138 46.769 ;
     RECT  12.384 46.769 15.138 46.921 ;
     RECT  15.915 46.109 16.197 46.921 ;
     RECT  12.384 46.921 16.197 47.039 ;
     RECT  13.215 47.039 16.197 47.075 ;
     RECT  17.64 46.499 65.142 47.075 ;
     RECT  12.384 47.039 12.402 47.111 ;
     RECT  14.832 47.075 16.197 47.119 ;
     RECT  9.144 44.909 9.162 47.191 ;
     RECT  8.928 47.191 9.162 47.309 ;
     RECT  14.832 47.119 16.506 47.309 ;
     RECT  17.64 47.075 19.278 47.309 ;
     RECT  20.16 47.075 65.142 47.309 ;
     RECT  10.515 46.769 11.61 47.357 ;
     RECT  14.832 47.309 16.362 47.381 ;
     RECT  14.832 47.381 16.197 47.417 ;
     RECT  17.64 47.309 17.73 47.417 ;
     RECT  14.832 47.417 15.138 47.453 ;
     RECT  10.515 47.357 10.797 47.461 ;
     RECT  10.26 47.461 10.797 47.579 ;
     RECT  18.54 47.309 18.897 47.579 ;
     RECT  20.592 47.309 65.142 47.579 ;
     RECT  9.144 47.309 9.162 47.615 ;
     RECT  14.832 47.453 14.85 47.615 ;
     RECT  17.712 47.417 17.73 47.615 ;
     RECT  25.344 47.579 65.142 47.651 ;
     RECT  20.592 47.579 24.606 47.687 ;
     RECT  25.344 47.651 25.902 47.723 ;
     RECT  26.676 47.651 65.142 47.741 ;
     RECT  21.276 47.687 24.606 47.849 ;
     RECT  25.344 47.723 25.83 47.849 ;
     RECT  26.676 47.741 31.194 47.849 ;
     RECT  22.68 47.849 24.462 47.885 ;
     RECT  26.676 47.849 27.882 47.885 ;
     RECT  30.852 47.849 31.194 47.885 ;
     RECT  28.872 47.849 30.006 47.891 ;
     RECT  27.792 47.885 27.882 48.119 ;
     RECT  29.415 47.891 30.006 48.119 ;
     RECT  30.852 47.885 30.87 48.119 ;
     RECT  29.415 48.119 29.862 48.155 ;
     RECT  21.315 47.849 21.762 48.191 ;
     RECT  27.864 48.119 27.882 48.389 ;
     RECT  23.292 47.885 24.297 48.425 ;
     RECT  26.676 47.885 26.997 48.425 ;
     RECT  31.968 47.741 65.142 48.541 ;
     RECT  31.608 48.541 65.142 48.695 ;
     RECT  31.824 48.695 65.142 48.703 ;
     RECT  31.824 48.703 65.322 48.839 ;
     RECT  32.076 48.839 65.322 48.929 ;
     RECT  32.115 48.929 65.322 49.505 ;
     RECT  32.115 49.505 64.998 50.189 ;
     RECT  32.115 50.189 64.89 51.269 ;
     RECT  58.284 51.269 64.89 51.709 ;
     RECT  58.284 51.709 64.926 51.745 ;
     RECT  58.284 51.745 65.394 52.007 ;
     RECT  58.284 52.007 65.322 52.169 ;
     RECT  33.624 51.269 57.546 52.177 ;
     RECT  58.284 52.169 65.25 52.177 ;
     RECT  33.624 52.177 65.25 52.349 ;
     RECT  33.624 52.349 64.962 52.439 ;
     RECT  33.84 52.439 64.962 52.889 ;
     RECT  33.84 52.889 64.797 53.051 ;
     RECT  33.948 53.051 64.797 53.249 ;
     RECT  33.948 53.249 63.09 53.429 ;
     RECT  33.948 53.429 34.002 53.519 ;
     RECT  63.864 53.249 64.797 53.519 ;
     RECT  33.984 53.519 34.002 53.591 ;
     RECT  34.74 53.429 63.09 53.627 ;
     RECT  34.74 53.627 35.097 53.663 ;
     RECT  36.108 53.627 36.126 53.663 ;
     RECT  36.864 53.627 63.09 53.663 ;
     RECT  36.936 53.663 63.09 53.933 ;
     RECT  37.08 53.933 63.09 53.969 ;
     RECT  37.08 53.969 62.73 54.509 ;
     RECT  37.116 54.509 62.73 54.599 ;
     RECT  61.38 54.599 62.73 54.671 ;
     RECT  61.38 54.671 62.097 54.743 ;
     RECT  37.116 54.599 60.642 54.977 ;
     RECT  37.224 54.977 60.642 55.013 ;
     RECT  37.26 55.013 60.642 55.247 ;
     RECT  37.26 55.247 56.754 55.277 ;
     RECT  57.564 55.247 60.642 55.283 ;
     RECT  37.404 55.277 56.754 55.445 ;
     RECT  57.96 55.283 60.642 55.445 ;
     RECT  58.248 55.445 60.642 55.481 ;
     RECT  58.248 55.481 60.606 55.589 ;
     RECT  37.404 55.445 56.697 55.715 ;
     RECT  58.248 55.589 59.397 55.715 ;
     RECT  58.284 55.715 59.397 55.823 ;
     RECT  37.515 55.715 56.697 55.949 ;
     RECT  53.316 55.949 55.494 56.045 ;
     RECT  60.588 55.589 60.606 56.219 ;
     RECT  55.476 56.045 55.494 56.255 ;
     RECT  37.515 55.949 52.29 56.327 ;
     RECT  53.316 56.045 54.414 56.327 ;
     RECT  37.515 56.327 51.462 56.363 ;
     RECT  53.424 56.327 54.234 56.399 ;
     RECT  52.272 56.327 52.29 56.489 ;
     RECT  53.715 56.399 54.234 56.489 ;
     RECT  37.515 56.363 51.297 56.633 ;
     RECT  37.515 56.633 49.806 56.759 ;
     RECT  49.536 56.759 49.806 56.867 ;
     RECT  37.515 56.759 48.654 56.939 ;
     RECT  49.536 56.867 49.554 56.939 ;
     RECT  37.515 56.939 48.597 57.029 ;
     RECT  37.515 57.029 39.114 57.101 ;
     RECT  37.515 57.101 38.934 57.137 ;
     RECT  38.52 57.137 38.934 57.173 ;
     RECT  39.924 57.029 48.597 57.173 ;
     RECT  38.52 57.173 38.538 57.209 ;
     RECT  39.924 57.173 44.19 57.209 ;
     RECT  45 57.173 48.597 57.209 ;
     RECT  39.924 57.209 43.974 57.335 ;
     RECT  39.924 57.335 43.938 57.407 ;
     RECT  45 57.209 46.746 57.407 ;
     RECT  47.772 57.209 48.597 57.407 ;
     RECT  41.4 57.407 43.434 57.443 ;
     RECT  41.4 57.443 41.994 57.479 ;
     RECT  46.728 57.407 46.746 57.479 ;
     RECT  41.472 57.479 41.994 57.569 ;
     RECT  45 57.407 45.897 57.569 ;
     RECT  41.472 57.569 41.814 57.677 ;
     RECT  41.508 57.677 41.526 57.713 ;
     RECT  42.915 57.443 43.434 74.849 ;
     RECT  2.415 44.789 2.697 75.347 ;
     RECT  5.115 44.375 5.397 75.347 ;
     RECT  7.815 44.381 8.097 75.347 ;
     RECT  10.515 47.579 10.797 75.347 ;
     RECT  13.215 47.075 13.497 75.347 ;
     RECT  15.915 47.417 16.197 75.347 ;
     RECT  18.615 47.579 18.897 75.347 ;
     RECT  21.315 48.191 21.597 75.347 ;
     RECT  24.015 48.425 24.297 75.347 ;
     RECT  26.715 48.425 26.997 75.347 ;
     RECT  29.415 48.155 29.697 75.347 ;
     RECT  32.115 51.269 32.397 75.347 ;
     RECT  34.815 53.663 35.097 75.347 ;
     RECT  37.515 57.137 37.797 75.347 ;
     RECT  40.215 57.407 40.497 75.347 ;
     RECT  45.615 57.569 45.897 75.347 ;
     RECT  48.315 57.407 48.597 75.347 ;
     RECT  51.015 56.633 51.297 75.347 ;
     RECT  53.715 56.489 53.997 75.347 ;
     RECT  56.415 55.949 56.697 75.347 ;
     RECT  59.115 55.823 59.397 75.347 ;
     RECT  61.815 54.743 62.097 75.347 ;
     RECT  64.515 53.519 64.797 75.347 ;
     RECT  67.215 38.939 67.497 75.347 ;
     RECT  69.915 2.413 70.197 75.347 ;
     RECT  72.615 2.413 72.897 75.347 ;
     RECT  75.315 2.413 75.597 75.347 ;
     RECT  78.015 2.413 78.297 75.347 ;
     RECT  80.715 2.413 80.997 75.347 ;
     RECT  83.415 39.479 83.697 75.347 ;
     RECT  42.915 74.849 43.254 75.389 ;
     RECT  2.415 75.347 2.505 75.617 ;
     RECT  5.115 75.347 5.205 75.617 ;
     RECT  7.815 75.347 7.905 75.617 ;
     RECT  10.515 75.347 10.605 75.617 ;
     RECT  13.215 75.347 13.305 75.617 ;
     RECT  15.915 75.347 16.005 75.617 ;
     RECT  18.615 75.347 18.705 75.617 ;
     RECT  21.315 75.347 21.405 75.617 ;
     RECT  24.015 75.347 24.105 75.617 ;
     RECT  26.715 75.347 26.805 75.617 ;
     RECT  29.415 75.347 29.505 75.617 ;
     RECT  32.115 75.347 32.205 75.617 ;
     RECT  34.815 75.347 34.905 75.617 ;
     RECT  37.515 75.347 37.605 75.617 ;
     RECT  40.215 75.347 40.305 75.617 ;
     RECT  42.915 75.389 43.146 75.617 ;
     RECT  45.615 75.347 45.705 75.617 ;
     RECT  48.315 75.347 48.405 75.617 ;
     RECT  51.015 75.347 51.105 75.617 ;
     RECT  53.715 75.347 53.805 75.617 ;
     RECT  56.415 75.347 56.505 75.617 ;
     RECT  59.115 75.347 59.205 75.617 ;
     RECT  61.815 75.347 61.905 75.617 ;
     RECT  64.515 75.347 64.605 75.617 ;
     RECT  67.215 75.347 67.305 75.617 ;
     RECT  69.915 75.347 70.005 75.617 ;
     RECT  72.615 75.347 72.705 75.617 ;
     RECT  75.315 75.347 75.405 75.617 ;
     RECT  78.015 75.347 78.105 75.617 ;
     RECT  80.715 75.347 80.805 75.617 ;
     RECT  83.415 75.347 83.505 75.617 ;
     RECT  43.128 75.617 43.146 75.821 ;
    LAYER M4 ;
     RECT  0.06 35.376 0.133 38.376 ;
     RECT  0.06 39.36 0.133 42.36 ;
     RECT  0.133 35.376 0.173 42.36 ;
     RECT  0.173 35.424 0.313 42.36 ;
     RECT  0.313 35.424 2.408 42.504 ;
     RECT  2.408 2.148 2.512 75.612 ;
     RECT  2.512 2.418 2.704 75.342 ;
     RECT  2.704 35.424 2.873 42.552 ;
     RECT  2.873 35.712 3.805 42.552 ;
     RECT  2.704 27.312 3.973 27.336 ;
     RECT  3.805 35.712 3.985 43.032 ;
     RECT  3.985 35.712 4.201 43.608 ;
     RECT  3.985 23.568 4.316 23.592 ;
     RECT  3.769 25.056 4.316 25.08 ;
     RECT  3.973 26.64 4.453 27.624 ;
     RECT  4.201 35.712 4.453 43.656 ;
     RECT  4.453 26.64 4.489 27.96 ;
     RECT  4.201 22.224 4.645 22.248 ;
     RECT  4.316 23.568 4.645 25.08 ;
     RECT  4.453 35.664 4.777 43.656 ;
     RECT  4.645 22.224 5.065 25.08 ;
     RECT  4.777 35.376 5.065 43.656 ;
     RECT  5.065 21.696 5.108 25.08 ;
     RECT  4.489 26.208 5.108 27.96 ;
     RECT  4.777 29.76 5.108 29.784 ;
     RECT  5.065 34.896 5.108 43.656 ;
     RECT  5.108 2.148 5.212 75.612 ;
     RECT  5.212 2.418 5.404 75.342 ;
     RECT  5.404 16.416 5.555 16.44 ;
     RECT  5.404 22.752 5.603 28.056 ;
     RECT  5.404 20.16 5.617 21.72 ;
     RECT  5.617 20.16 5.681 20.568 ;
     RECT  5.603 22.752 5.681 25.704 ;
     RECT  5.681 22.8 5.717 25.704 ;
     RECT  5.404 29.76 5.753 29.784 ;
     RECT  5.717 22.8 5.891 23.592 ;
     RECT  5.717 24.672 5.891 25.704 ;
     RECT  5.891 22.8 5.932 23.352 ;
     RECT  5.617 21.696 5.969 21.72 ;
     RECT  5.404 33.408 6.38 44.184 ;
     RECT  5.603 26.688 6.505 28.056 ;
     RECT  5.404 30.816 6.505 31.56 ;
     RECT  5.404 14.256 6.565 14.808 ;
     RECT  5.681 20.16 6.613 20.184 ;
     RECT  6.505 26.688 6.617 28.968 ;
     RECT  6.565 14.256 6.645 14.856 ;
     RECT  6.645 14.832 6.653 14.856 ;
     RECT  6.505 30.816 6.709 31.896 ;
     RECT  6.38 32.88 6.709 44.184 ;
     RECT  6.565 11.952 6.797 11.976 ;
     RECT  5.891 24.672 6.829 25.464 ;
     RECT  6.617 26.688 6.829 27.96 ;
     RECT  6.709 30.816 6.833 44.184 ;
     RECT  5.932 22.8 6.865 22.824 ;
     RECT  5.404 18.24 6.901 18.264 ;
     RECT  6.865 22.56 6.937 22.824 ;
     RECT  6.901 18.24 6.973 18.936 ;
     RECT  6.833 30.816 6.973 30.84 ;
     RECT  6.613 19.92 7.081 20.184 ;
     RECT  6.937 21.696 7.081 22.824 ;
     RECT  6.685 17.088 7.34 17.112 ;
     RECT  7.34 16.416 7.381 17.112 ;
     RECT  6.973 18.192 7.381 18.936 ;
     RECT  6.617 28.944 7.621 28.968 ;
     RECT  7.225 15.408 7.669 15.432 ;
     RECT  7.381 16.416 7.669 18.936 ;
     RECT  6.829 24.528 7.729 25.464 ;
     RECT  6.829 26.592 7.729 27.96 ;
     RECT  7.621 28.944 7.729 29.352 ;
     RECT  6.833 31.872 7.765 44.184 ;
     RECT  7.693 10.944 7.808 10.968 ;
     RECT  6.397 13.056 7.808 13.08 ;
     RECT  7.669 14.784 7.808 18.936 ;
     RECT  7.081 19.92 7.808 22.824 ;
     RECT  7.729 24.528 7.808 29.352 ;
     RECT  6.973 30.336 7.808 30.84 ;
     RECT  7.765 31.872 7.808 44.376 ;
     RECT  7.808 2.148 7.912 75.612 ;
     RECT  7.912 2.418 8.104 75.342 ;
     RECT  8.104 21.984 8.165 29.352 ;
     RECT  8.104 30.336 8.273 44.376 ;
     RECT  8.104 10.224 8.381 10.968 ;
     RECT  8.273 33.264 8.417 44.376 ;
     RECT  8.104 11.952 8.885 12.744 ;
     RECT  8.104 15.024 9.029 17.112 ;
     RECT  9.029 16.368 9.097 17.112 ;
     RECT  8.104 18.192 9.097 18.216 ;
     RECT  8.165 28.512 9.109 29.352 ;
     RECT  8.273 30.336 9.109 32.232 ;
     RECT  9.097 16.368 9.137 18.216 ;
     RECT  9.109 28.512 9.157 32.232 ;
     RECT  8.165 26.112 9.245 27.384 ;
     RECT  8.417 33.408 9.385 44.376 ;
     RECT  9.109 45.744 9.385 45.768 ;
     RECT  8.381 10.224 9.421 10.872 ;
     RECT  9.157 28.464 9.421 32.232 ;
     RECT  9.385 33.408 9.421 45.768 ;
     RECT  8.104 19.92 9.452 20.952 ;
     RECT  8.165 21.984 9.452 24.504 ;
     RECT  8.104 13.968 9.493 13.992 ;
     RECT  9.029 15.024 9.493 15.24 ;
     RECT  9.452 19.92 9.497 24.504 ;
     RECT  9.493 13.968 9.533 15.24 ;
     RECT  9.497 19.92 9.637 24.12 ;
     RECT  9.421 9.888 9.692 10.872 ;
     RECT  9.421 28.464 10.172 45.768 ;
     RECT  9.245 26.592 10.213 27.24 ;
     RECT  10.172 28.272 10.213 45.768 ;
     RECT  10.213 26.592 10.261 45.768 ;
     RECT  9.637 19.344 10.309 24.12 ;
     RECT  9.692 9.648 10.508 10.872 ;
     RECT  8.885 11.952 10.508 11.976 ;
     RECT  9.533 14.208 10.508 15.24 ;
     RECT  9.137 16.368 10.508 17.64 ;
     RECT  10.309 18.816 10.508 24.12 ;
     RECT  10.261 26.208 10.508 45.768 ;
     RECT  10.508 2.148 10.612 75.612 ;
     RECT  10.612 2.418 10.804 75.342 ;
     RECT  10.804 31.392 10.829 43.368 ;
     RECT  10.804 15.216 10.865 15.24 ;
     RECT  10.829 33.648 10.865 43.368 ;
     RECT  10.804 11.952 10.931 14.232 ;
     RECT  10.804 9.36 10.937 9.912 ;
     RECT  10.804 30.048 10.973 30.072 ;
     RECT  10.865 33.648 11.123 35.448 ;
     RECT  10.804 24.48 11.161 29.016 ;
     RECT  10.804 19.776 11.411 23.256 ;
     RECT  11.161 24.48 11.449 27.336 ;
     RECT  11.123 33.696 11.621 35.448 ;
     RECT  10.804 47.328 11.621 47.352 ;
     RECT  11.161 28.368 11.797 29.016 ;
     RECT  10.865 36.432 11.833 43.368 ;
     RECT  10.931 11.952 11.837 12.552 ;
     RECT  10.804 16.368 11.843 17.688 ;
     RECT  10.829 31.392 11.869 32.328 ;
     RECT  11.833 36.432 11.873 43.464 ;
     RECT  10.804 44.88 11.873 45.864 ;
     RECT  11.621 33.792 12.017 35.448 ;
     RECT  11.873 40.848 12.017 43.464 ;
     RECT  11.449 25.056 12.193 27.336 ;
     RECT  11.797 28.368 12.193 29.784 ;
     RECT  12.017 34.08 12.373 35.448 ;
     RECT  11.873 36.432 12.373 39.768 ;
     RECT  12.017 41.136 12.38 43.464 ;
     RECT  10.937 9.648 12.481 9.672 ;
     RECT  12.193 25.056 12.517 29.784 ;
     RECT  11.869 31.392 12.517 32.472 ;
     RECT  12.481 9.072 12.553 9.672 ;
     RECT  11.411 21.12 12.625 22.824 ;
     RECT  12.373 34.08 12.841 39.768 ;
     RECT  12.841 34.08 12.985 40.056 ;
     RECT  12.38 41.136 12.985 44.04 ;
     RECT  12.553 8.496 13.045 9.672 ;
     RECT  11.411 19.776 13.045 19.944 ;
     RECT  12.625 21.12 13.045 23.16 ;
     RECT  13.045 8.496 13.057 10.344 ;
     RECT  12.517 25.056 13.093 32.76 ;
     RECT  13.057 8.496 13.208 10.392 ;
     RECT  11.837 11.952 13.208 11.976 ;
     RECT  12.661 13.104 13.208 13.128 ;
     RECT  10.931 14.208 13.208 14.232 ;
     RECT  11.843 16.368 13.208 16.584 ;
     RECT  13.045 19.776 13.208 23.16 ;
     RECT  13.093 24.72 13.208 32.76 ;
     RECT  12.985 34.08 13.208 44.04 ;
     RECT  11.873 45.696 13.208 45.864 ;
     RECT  13.208 2.148 13.312 75.612 ;
     RECT  13.312 2.418 13.504 75.342 ;
     RECT  13.504 24.144 13.715 32.76 ;
     RECT  13.504 19.584 13.781 23.16 ;
     RECT  13.504 10.32 13.859 11.448 ;
     RECT  13.781 20.928 14.033 23.16 ;
     RECT  13.715 30.24 14.147 32.76 ;
     RECT  13.504 34.08 14.177 35.784 ;
     RECT  13.504 42.768 14.291 44.376 ;
     RECT  14.291 42.768 14.357 44.136 ;
     RECT  13.859 10.32 14.387 11.208 ;
     RECT  13.504 12.816 14.387 12.84 ;
     RECT  13.504 14.256 14.435 16.536 ;
     RECT  13.781 19.584 14.533 19.8 ;
     RECT  14.435 15.408 14.537 16.536 ;
     RECT  13.504 45.36 14.537 46.152 ;
     RECT  13.504 18.192 14.629 18.216 ;
     RECT  13.504 36.864 14.645 41.4 ;
     RECT  14.177 35.712 14.684 35.784 ;
     RECT  14.645 36.864 14.684 37.032 ;
     RECT  14.629 17.616 14.716 18.216 ;
     RECT  14.147 31.92 14.717 32.76 ;
     RECT  14.684 35.712 14.771 37.032 ;
     RECT  13.504 8.448 14.785 9.336 ;
     RECT  13.715 24.144 14.785 28.872 ;
     RECT  14.147 30.24 14.785 30.648 ;
     RECT  14.645 38.16 14.789 41.4 ;
     RECT  14.533 19.392 14.821 19.8 ;
     RECT  14.033 20.928 14.821 22.776 ;
     RECT  14.821 19.392 14.825 22.776 ;
     RECT  14.785 24.144 14.825 30.648 ;
     RECT  14.785 7.632 14.893 9.336 ;
     RECT  14.387 10.32 14.893 10.488 ;
     RECT  14.893 7.632 14.933 10.488 ;
     RECT  14.789 38.208 14.933 41.4 ;
     RECT  14.537 45.36 14.933 45.864 ;
     RECT  14.177 34.08 15.253 34.2 ;
     RECT  14.933 38.256 15.297 41.4 ;
     RECT  14.435 14.256 15.469 14.28 ;
     RECT  14.537 15.408 15.469 16.104 ;
     RECT  14.825 24.336 15.685 30.648 ;
     RECT  15.469 14.256 15.793 16.104 ;
     RECT  14.933 45.408 15.793 45.864 ;
     RECT  15.685 24.336 15.829 30.744 ;
     RECT  14.716 18.192 15.865 18.216 ;
     RECT  14.825 19.392 15.865 22.248 ;
     RECT  14.933 7.632 15.908 8.472 ;
     RECT  14.933 9.504 15.908 10.488 ;
     RECT  15.073 11.952 15.908 12.024 ;
     RECT  15.793 14.256 15.908 16.584 ;
     RECT  15.865 18.192 15.908 22.248 ;
     RECT  15.829 24.144 15.908 30.744 ;
     RECT  14.717 31.92 15.908 32.664 ;
     RECT  15.253 33.936 15.908 34.2 ;
     RECT  14.771 35.712 15.908 35.784 ;
     RECT  14.771 36.768 15.908 37.032 ;
     RECT  15.297 38.256 15.908 41.496 ;
     RECT  14.357 43.296 15.908 44.136 ;
     RECT  15.793 45.408 15.908 46.104 ;
     RECT  15.908 2.148 16.012 75.612 ;
     RECT  16.012 2.418 16.204 75.342 ;
     RECT  16.204 33.36 16.265 35.736 ;
     RECT  16.204 7.632 16.365 8.472 ;
     RECT  16.204 17.664 16.409 18.504 ;
     RECT  16.204 24.144 16.481 32.088 ;
     RECT  16.481 26.208 16.553 32.088 ;
     RECT  16.553 26.208 16.733 30.408 ;
     RECT  16.733 28.944 16.739 30.408 ;
     RECT  16.553 31.536 16.883 32.088 ;
     RECT  16.739 28.944 16.913 29.784 ;
     RECT  16.265 33.36 17.027 35.544 ;
     RECT  16.204 19.776 17.093 20.616 ;
     RECT  16.204 11.952 17.123 15.336 ;
     RECT  16.204 9.504 17.209 10.872 ;
     RECT  16.365 8.4 17.233 8.472 ;
     RECT  17.209 9.504 17.233 10.776 ;
     RECT  17.123 12.24 17.237 15.336 ;
     RECT  16.481 24.144 17.273 25.128 ;
     RECT  16.204 38.112 17.345 39.336 ;
     RECT  16.204 40.56 17.377 41.496 ;
     RECT  17.237 12.24 17.381 12.456 ;
     RECT  16.204 21.984 17.449 22.248 ;
     RECT  17.237 13.824 17.459 15.336 ;
     RECT  16.204 42.72 17.489 44.136 ;
     RECT  16.883 31.536 17.521 31.56 ;
     RECT  17.521 31.296 17.561 31.56 ;
     RECT  17.449 21.984 17.605 22.776 ;
     RECT  17.273 24.144 17.605 24.216 ;
     RECT  16.733 26.208 17.701 27.624 ;
     RECT  17.093 19.776 17.773 20.184 ;
     RECT  16.409 17.664 17.845 17.688 ;
     RECT  17.377 40.464 17.953 41.496 ;
     RECT  17.489 42.72 17.953 44.04 ;
     RECT  17.773 19.248 18.169 20.184 ;
     RECT  17.233 8.4 18.229 10.776 ;
     RECT  17.027 33.936 18.421 35.544 ;
     RECT  16.913 29.616 18.457 29.64 ;
     RECT  17.953 40.464 18.457 44.04 ;
     RECT  18.229 7.92 18.469 10.776 ;
     RECT  17.459 14.112 18.493 15.336 ;
     RECT  16.204 16.56 18.493 16.584 ;
     RECT  18.565 32.736 18.601 32.76 ;
     RECT  18.421 33.936 18.601 35.736 ;
     RECT  18.469 6.24 18.608 10.776 ;
     RECT  17.381 12.24 18.608 12.264 ;
     RECT  18.493 14.112 18.608 16.584 ;
     RECT  17.845 17.664 18.608 18.024 ;
     RECT  18.169 19.008 18.608 20.184 ;
     RECT  17.605 21.984 18.608 24.216 ;
     RECT  17.701 25.728 18.608 27.624 ;
     RECT  18.457 29.04 18.608 29.64 ;
     RECT  17.561 31.296 18.608 31.32 ;
     RECT  18.601 32.736 18.608 35.736 ;
     RECT  16.204 36.912 18.608 36.936 ;
     RECT  17.345 38.112 18.608 38.136 ;
     RECT  17.345 39.312 18.608 39.336 ;
     RECT  18.457 40.464 18.608 44.136 ;
     RECT  16.204 45.504 18.608 46.104 ;
     RECT  18.608 2.148 18.712 75.612 ;
     RECT  18.712 2.418 18.904 75.342 ;
     RECT  18.904 33.84 18.929 35.976 ;
     RECT  18.904 40.464 19.001 45 ;
     RECT  18.904 29.616 19.037 30.12 ;
     RECT  18.904 26.256 19.043 28.44 ;
     RECT  18.904 7.92 19.081 16.056 ;
     RECT  19.081 11.952 19.187 16.056 ;
     RECT  19.081 7.92 19.217 10.872 ;
     RECT  19.187 11.952 19.217 13.08 ;
     RECT  18.904 23.952 19.361 24.936 ;
     RECT  19.037 29.616 19.361 29.64 ;
     RECT  18.904 20.16 19.469 20.616 ;
     RECT  19.187 14.16 19.649 14.52 ;
     RECT  18.904 22.128 19.685 22.776 ;
     RECT  19.649 14.352 19.865 14.52 ;
     RECT  19.187 15.936 19.897 16.056 ;
     RECT  18.904 17.616 19.897 19.032 ;
     RECT  18.904 38.112 19.897 38.184 ;
     RECT  19.217 8.256 19.937 10.872 ;
     RECT  18.929 34.656 20.005 35.976 ;
     RECT  19.897 37.632 20.041 38.184 ;
     RECT  19.217 11.952 20.045 11.976 ;
     RECT  18.904 46.032 20.149 46.056 ;
     RECT  18.904 47.04 20.149 47.064 ;
     RECT  19.001 40.464 20.185 41.4 ;
     RECT  19.001 42.72 20.197 45 ;
     RECT  20.149 46.032 20.197 47.064 ;
     RECT  18.904 31.68 20.204 32.76 ;
     RECT  20.204 31.68 20.291 33.288 ;
     RECT  20.329 6.816 20.341 6.84 ;
     RECT  19.937 8.256 20.341 9.816 ;
     RECT  18.904 39.168 20.401 39.384 ;
     RECT  20.185 40.416 20.401 41.4 ;
     RECT  19.361 24.912 20.437 24.936 ;
     RECT  20.041 37.584 20.437 38.184 ;
     RECT  20.401 39.168 20.437 41.4 ;
     RECT  19.865 14.496 20.473 14.52 ;
     RECT  20.197 42.72 20.509 47.064 ;
     RECT  20.437 37.584 20.581 41.4 ;
     RECT  20.473 14.496 20.617 14.664 ;
     RECT  20.617 14.496 20.653 14.712 ;
     RECT  20.653 14.496 20.725 14.808 ;
     RECT  19.897 15.936 20.725 16.296 ;
     RECT  20.291 31.68 20.725 32.472 ;
     RECT  20.005 34.656 20.869 36.504 ;
     RECT  20.581 37.584 20.869 41.688 ;
     RECT  20.869 34.656 21.013 41.688 ;
     RECT  20.509 42.72 21.013 47.304 ;
     RECT  21.013 34.656 21.049 47.304 ;
     RECT  19.043 26.256 21.157 27.624 ;
     RECT  21.157 26.256 21.193 27.72 ;
     RECT  19.217 13.056 21.265 13.08 ;
     RECT  20.341 6.816 21.308 9.816 ;
     RECT  19.937 10.848 21.308 10.872 ;
     RECT  21.265 12.336 21.308 13.08 ;
     RECT  20.725 14.496 21.308 16.296 ;
     RECT  19.897 17.616 21.308 19.368 ;
     RECT  19.469 20.592 21.308 20.616 ;
     RECT  19.685 22.128 21.308 22.2 ;
     RECT  20.041 23.28 21.308 23.304 ;
     RECT  20.437 24.48 21.308 25.128 ;
     RECT  21.193 26.256 21.308 28.2 ;
     RECT  20.725 31.392 21.308 32.472 ;
     RECT  21.049 34.08 21.308 47.304 ;
     RECT  21.308 2.148 21.412 75.612 ;
     RECT  21.412 2.418 21.604 75.342 ;
     RECT  21.604 41.664 21.665 44.472 ;
     RECT  21.604 30.096 21.773 30.12 ;
     RECT  21.604 45.84 21.809 46.008 ;
     RECT  21.604 31.152 21.953 33.048 ;
     RECT  21.604 34.416 21.953 39.864 ;
     RECT  21.953 34.416 21.989 39.816 ;
     RECT  21.953 31.152 22.025 32.952 ;
     RECT  22.025 31.152 22.097 32.904 ;
     RECT  21.989 34.416 22.169 38.232 ;
     RECT  22.169 36.048 22.205 38.232 ;
     RECT  21.604 11.952 22.313 12.36 ;
     RECT  22.205 36.048 22.313 36.072 ;
     RECT  21.604 7.344 22.421 10.152 ;
     RECT  22.205 37.056 22.421 38.232 ;
     RECT  21.604 22.56 22.493 22.776 ;
     RECT  21.604 16.032 22.7 19.032 ;
     RECT  21.604 20.496 22.7 21.432 ;
     RECT  21.604 47.136 22.705 47.688 ;
     RECT  22.421 7.344 22.709 7.992 ;
     RECT  21.604 26.784 22.741 28.248 ;
     RECT  22.7 16.032 22.787 21.432 ;
     RECT  22.787 16.032 22.789 20.184 ;
     RECT  22.705 46.944 22.817 47.688 ;
     RECT  21.665 41.664 22.885 44.376 ;
     RECT  22.741 26.784 22.921 28.728 ;
     RECT  21.989 39.6 22.957 39.816 ;
     RECT  22.957 39.6 22.993 39.912 ;
     RECT  21.604 14.064 23.029 14.952 ;
     RECT  22.097 31.152 23.065 32.808 ;
     RECT  22.169 34.416 23.065 34.776 ;
     RECT  22.421 9.072 23.245 10.152 ;
     RECT  23.065 31.152 23.245 34.776 ;
     RECT  22.885 41.616 23.245 44.376 ;
     RECT  21.809 45.84 23.245 45.864 ;
     RECT  23.245 9.072 23.317 10.344 ;
     RECT  23.317 9.072 23.353 10.92 ;
     RECT  22.313 11.952 23.353 11.976 ;
     RECT  23.245 31.152 23.365 35.544 ;
     RECT  22.421 37.056 23.365 37.944 ;
     RECT  22.993 39.216 23.413 40.248 ;
     RECT  23.245 41.616 23.413 45.864 ;
     RECT  23.353 9.072 23.42 11.976 ;
     RECT  23.365 31.152 23.509 37.944 ;
     RECT  23.42 9.072 23.605 12.216 ;
     RECT  23.029 13.296 23.605 14.952 ;
     RECT  23.317 24.336 23.713 24.36 ;
     RECT  22.789 15.936 23.749 20.184 ;
     RECT  22.787 21.408 23.749 21.432 ;
     RECT  22.849 6.816 24.008 6.84 ;
     RECT  22.709 7.968 24.008 7.992 ;
     RECT  23.605 9.072 24.008 14.952 ;
     RECT  23.749 15.936 24.008 21.432 ;
     RECT  22.493 22.752 24.008 22.776 ;
     RECT  23.713 24.336 24.008 25.128 ;
     RECT  22.921 26.784 24.008 29.016 ;
     RECT  23.509 30.24 24.008 37.944 ;
     RECT  23.413 39.216 24.008 45.864 ;
     RECT  22.817 47.28 24.008 47.688 ;
     RECT  24.008 2.148 24.112 75.612 ;
     RECT  24.112 2.418 24.304 75.342 ;
     RECT  24.304 9.072 24.401 11.064 ;
     RECT  24.304 16.8 24.473 21.96 ;
     RECT  24.304 30.336 24.515 33 ;
     RECT  24.304 34.08 24.515 44.328 ;
     RECT  24.401 9.072 24.617 9.384 ;
     RECT  24.515 35.184 24.797 44.328 ;
     RECT  24.304 45.792 24.797 47.352 ;
     RECT  24.304 14.928 24.977 15.336 ;
     RECT  24.473 16.8 25.043 21.048 ;
     RECT  24.515 30.336 25.049 32.472 ;
     RECT  24.401 10.368 25.085 11.064 ;
     RECT  24.304 12.336 25.085 13.32 ;
     RECT  24.977 14.928 25.121 15.288 ;
     RECT  24.304 5.088 25.139 6.84 ;
     RECT  25.049 30.336 25.157 31.944 ;
     RECT  25.085 12.48 25.193 13.32 ;
     RECT  25.043 18.912 25.193 21.048 ;
     RECT  25.085 10.464 25.297 11.064 ;
     RECT  25.193 12.864 25.297 13.32 ;
     RECT  24.304 25.968 25.34 25.992 ;
     RECT  24.304 27.36 25.34 27.912 ;
     RECT  25.34 25.968 25.373 27.912 ;
     RECT  25.373 26.64 25.427 27.912 ;
     RECT  25.121 14.928 25.445 15 ;
     RECT  24.304 23.952 25.513 23.976 ;
     RECT  24.304 7.968 25.553 7.992 ;
     RECT  25.427 26.784 25.553 27.912 ;
     RECT  25.513 23.328 25.621 23.976 ;
     RECT  25.139 6.048 25.661 6.84 ;
     RECT  25.297 10.464 25.667 11.448 ;
     RECT  25.193 18.912 25.715 20.568 ;
     RECT  25.043 16.8 25.82 17.928 ;
     RECT  24.304 28.944 25.837 28.968 ;
     RECT  24.515 34.08 25.873 34.104 ;
     RECT  25.553 27.888 25.945 27.912 ;
     RECT  25.837 28.944 25.945 29.112 ;
     RECT  25.157 31.92 26.089 31.944 ;
     RECT  25.945 27.888 26.125 29.112 ;
     RECT  25.157 30.336 26.125 30.36 ;
     RECT  24.797 35.328 26.125 44.328 ;
     RECT  25.873 33.6 26.197 34.104 ;
     RECT  26.125 35.328 26.197 44.76 ;
     RECT  25.445 14.928 26.581 14.952 ;
     RECT  25.297 12.864 26.593 13.512 ;
     RECT  26.581 14.736 26.593 14.952 ;
     RECT  26.557 8.256 26.665 8.28 ;
     RECT  25.661 6.048 26.708 6.072 ;
     RECT  26.665 7.92 26.708 8.28 ;
     RECT  24.617 9.36 26.708 9.384 ;
     RECT  25.667 10.464 26.708 10.488 ;
     RECT  26.593 12.864 26.708 14.952 ;
     RECT  25.82 16.656 26.708 17.928 ;
     RECT  25.715 18.912 26.708 19.8 ;
     RECT  26.341 21.072 26.708 21.096 ;
     RECT  25.621 22.56 26.708 23.976 ;
     RECT  25.553 26.784 26.708 26.808 ;
     RECT  26.125 27.888 26.708 30.36 ;
     RECT  26.089 31.92 26.708 32.328 ;
     RECT  26.197 33.6 26.708 44.76 ;
     RECT  24.797 45.792 26.708 46.92 ;
     RECT  26.708 2.148 26.812 75.612 ;
     RECT  26.812 2.418 27.004 75.342 ;
     RECT  27.004 35.28 27.065 44.568 ;
     RECT  27.004 25.968 27.101 30.456 ;
     RECT  27.004 32.304 27.101 34.152 ;
     RECT  27.101 32.448 27.353 34.152 ;
     RECT  27.004 2.784 27.389 3.336 ;
     RECT  27.004 13.056 27.389 15.576 ;
     RECT  27.353 32.448 27.395 34.104 ;
     RECT  27.395 33.312 27.425 34.104 ;
     RECT  27.004 45.6 27.469 47.88 ;
     RECT  27.389 13.056 27.497 15.528 ;
     RECT  27.469 45.6 27.497 46.2 ;
     RECT  27.101 25.968 27.539 28.872 ;
     RECT  27.065 35.28 27.641 43.128 ;
     RECT  27.641 36.576 27.749 43.128 ;
     RECT  27.641 35.28 27.965 35.352 ;
     RECT  27.925 0.528 27.997 0.552 ;
     RECT  27.997 0.528 28.069 1.176 ;
     RECT  27.004 10.944 28.069 10.968 ;
     RECT  27.749 40.896 28.069 43.128 ;
     RECT  27.065 44.16 28.069 44.568 ;
     RECT  27.004 5.328 28.105 6.312 ;
     RECT  28.069 40.896 28.115 44.568 ;
     RECT  27.004 19.776 28.141 19.8 ;
     RECT  28.069 0.528 28.163 1.224 ;
     RECT  27.389 2.88 28.177 3.336 ;
     RECT  27.004 21.936 28.177 23.832 ;
     RECT  27.004 16.656 28.211 18.792 ;
     RECT  28.069 10.944 28.325 11.064 ;
     RECT  27.425 34.08 28.361 34.104 ;
     RECT  28.163 0.528 28.493 1.128 ;
     RECT  28.177 2.88 28.501 3.432 ;
     RECT  27.497 15.504 28.501 15.528 ;
     RECT  28.211 18.768 28.501 18.792 ;
     RECT  28.141 19.776 28.501 19.848 ;
     RECT  28.493 0.096 28.577 1.128 ;
     RECT  28.501 15.504 28.645 15.576 ;
     RECT  28.501 18.768 28.789 19.848 ;
     RECT  27.469 47.616 28.825 47.88 ;
     RECT  28.577 0.144 28.835 1.128 ;
     RECT  27.004 8.256 28.861 9.96 ;
     RECT  28.429 11.424 28.861 11.448 ;
     RECT  27.497 13.056 28.861 14.28 ;
     RECT  28.501 2.256 28.885 3.432 ;
     RECT  28.105 4.8 28.885 6.312 ;
     RECT  28.861 13.056 28.933 14.424 ;
     RECT  27.539 25.968 28.94 25.992 ;
     RECT  28.177 21.936 28.941 23.88 ;
     RECT  28.861 7.968 29.041 9.96 ;
     RECT  27.997 35.184 29.041 35.256 ;
     RECT  27.749 36.576 29.041 39.912 ;
     RECT  28.115 40.896 29.113 44.184 ;
     RECT  27.497 45.6 29.113 45.912 ;
     RECT  28.885 2.256 29.149 6.312 ;
     RECT  29.149 1.728 29.221 6.312 ;
     RECT  29.041 7.92 29.221 9.96 ;
     RECT  28.941 21.936 29.257 23.976 ;
     RECT  29.221 1.728 29.269 9.96 ;
     RECT  28.861 11.424 29.269 11.976 ;
     RECT  28.933 13.056 29.269 14.472 ;
     RECT  29.269 1.728 29.408 10.152 ;
     RECT  29.269 11.424 29.408 14.472 ;
     RECT  28.645 15.456 29.408 15.576 ;
     RECT  28.211 16.656 29.408 17.64 ;
     RECT  28.789 18.768 29.408 20.088 ;
     RECT  29.257 21.12 29.408 23.976 ;
     RECT  28.94 25.152 29.408 25.992 ;
     RECT  27.539 27.264 29.408 28.872 ;
     RECT  27.101 30.336 29.408 30.456 ;
     RECT  29.293 31.68 29.408 31.704 ;
     RECT  28.861 33.024 29.408 33.048 ;
     RECT  29.041 35.184 29.408 39.912 ;
     RECT  29.113 40.896 29.408 45.912 ;
     RECT  28.825 47.376 29.408 47.88 ;
     RECT  29.408 1.728 29.512 75.612 ;
     RECT  29.512 1.728 29.704 75.342 ;
     RECT  29.704 31.392 29.765 31.752 ;
     RECT  29.704 46.896 29.873 47.88 ;
     RECT  28.835 0.144 29.941 0.648 ;
     RECT  29.704 1.728 29.941 10.248 ;
     RECT  29.704 27.648 30.017 27.912 ;
     RECT  29.704 32.928 30.017 33.096 ;
     RECT  29.941 0.144 30.025 10.248 ;
     RECT  30.025 0.144 30.083 0.552 ;
     RECT  30.025 1.728 30.089 10.248 ;
     RECT  29.704 17.088 30.125 24.504 ;
     RECT  29.704 11.232 30.275 15.48 ;
     RECT  30.089 1.728 30.305 9.048 ;
     RECT  30.305 1.728 30.323 7.464 ;
     RECT  30.125 17.088 30.341 20.568 ;
     RECT  30.125 22.464 30.377 24.504 ;
     RECT  29.704 29.088 30.377 30.36 ;
     RECT  29.704 35.232 30.377 37.704 ;
     RECT  30.083 0.144 30.421 0.168 ;
     RECT  29.704 43.872 30.449 44.76 ;
     RECT  30.377 22.464 30.457 23.88 ;
     RECT  29.873 46.896 30.557 47.736 ;
     RECT  30.377 36.096 30.563 37.704 ;
     RECT  29.704 25.776 30.769 25.8 ;
     RECT  30.377 30.336 30.769 30.36 ;
     RECT  29.765 31.68 30.769 31.752 ;
     RECT  30.769 25.68 30.809 25.8 ;
     RECT  30.769 30.336 30.845 31.752 ;
     RECT  30.017 27.84 30.953 27.912 ;
     RECT  30.377 29.088 30.953 29.112 ;
     RECT  30.017 33.072 30.953 33.096 ;
     RECT  30.563 36.24 30.953 37.704 ;
     RECT  30.341 17.088 31.097 20.088 ;
     RECT  30.421 0.096 31.237 0.168 ;
     RECT  30.305 8.448 31.309 9.048 ;
     RECT  30.089 10.224 31.309 10.248 ;
     RECT  31.309 8.448 31.345 10.248 ;
     RECT  30.275 11.232 31.345 15.048 ;
     RECT  31.097 18.576 31.453 20.088 ;
     RECT  31.345 8.448 31.484 15.048 ;
     RECT  31.097 17.088 31.525 17.112 ;
     RECT  30.845 30.336 31.525 30.84 ;
     RECT  30.457 22.464 31.532 22.872 ;
     RECT  30.457 23.856 31.532 23.88 ;
     RECT  31.532 22.464 31.561 23.88 ;
     RECT  31.561 22.464 31.573 24.408 ;
     RECT  30.953 36.24 31.597 36.264 ;
     RECT  29.704 38.784 31.741 42.6 ;
     RECT  30.323 1.728 31.765 2.28 ;
     RECT  30.323 3.456 31.765 6.984 ;
     RECT  31.765 1.728 31.849 6.984 ;
     RECT  30.953 37.44 31.885 37.704 ;
     RECT  31.741 38.784 31.885 42.744 ;
     RECT  31.345 33.936 31.921 33.96 ;
     RECT  31.597 35.856 31.921 36.264 ;
     RECT  30.769 46.176 31.921 46.2 ;
     RECT  30.557 47.712 31.921 47.736 ;
     RECT  31.237 0.096 31.957 0.216 ;
     RECT  31.525 29.616 31.957 30.84 ;
     RECT  30.449 43.872 31.957 44.712 ;
     RECT  31.921 46.176 31.957 47.736 ;
     RECT  31.885 37.44 32.029 42.744 ;
     RECT  31.849 1.728 32.108 7.464 ;
     RECT  31.484 8.448 32.108 15.096 ;
     RECT  31.525 16.512 32.108 17.112 ;
     RECT  31.453 18.576 32.108 20.424 ;
     RECT  31.573 22.176 32.108 24.408 ;
     RECT  30.809 25.68 32.108 25.752 ;
     RECT  30.953 27.888 32.108 27.912 ;
     RECT  31.957 29.616 32.108 31.416 ;
     RECT  31.921 33.936 32.108 36.264 ;
     RECT  32.029 37.44 32.108 42.792 ;
     RECT  31.957 43.872 32.108 47.736 ;
     RECT  32.108 1.728 32.212 75.612 ;
     RECT  32.212 1.728 32.404 75.342 ;
     RECT  31.957 0.096 32.533 0.6 ;
     RECT  32.404 48.768 32.537 48.984 ;
     RECT  32.404 9.696 32.627 14.952 ;
     RECT  32.627 10.128 32.645 14.952 ;
     RECT  32.645 11.616 32.668 14.952 ;
     RECT  32.668 14.064 32.681 14.952 ;
     RECT  32.404 18.192 32.681 20.424 ;
     RECT  32.404 24.384 32.681 24.408 ;
     RECT  32.404 39.456 32.717 42.744 ;
     RECT  32.537 48.96 32.717 48.984 ;
     RECT  32.717 39.456 32.825 41.592 ;
     RECT  32.404 21.648 32.969 21.672 ;
     RECT  32.825 39.456 33.185 39.864 ;
     RECT  32.404 43.872 33.257 47.736 ;
     RECT  32.645 10.128 33.293 10.632 ;
     RECT  33.185 39.504 33.329 39.864 ;
     RECT  32.681 18.192 33.437 19.08 ;
     RECT  32.404 33.936 33.437 34.92 ;
     RECT  32.825 40.848 33.437 41.592 ;
     RECT  33.293 10.128 33.443 10.152 ;
     RECT  32.404 29.616 33.469 30.36 ;
     RECT  32.404 37.584 33.469 38.424 ;
     RECT  33.257 43.872 33.473 46.632 ;
     RECT  32.681 14.352 33.596 14.952 ;
     RECT  32.404 17.04 33.596 17.064 ;
     RECT  33.437 18.192 33.613 19.032 ;
     RECT  33.596 14.352 33.637 15.48 ;
     RECT  33.596 16.56 33.637 17.064 ;
     RECT  33.613 18.096 33.653 19.032 ;
     RECT  33.257 47.664 33.683 47.736 ;
     RECT  33.596 51.6 33.683 51.624 ;
     RECT  33.637 14.352 33.757 17.064 ;
     RECT  33.437 41.04 33.793 41.592 ;
     RECT  32.717 42.624 33.793 42.648 ;
     RECT  33.757 14.304 33.797 17.064 ;
     RECT  33.469 29.04 33.829 30.456 ;
     RECT  32.681 20.16 33.865 20.424 ;
     RECT  32.404 1.728 33.901 8.52 ;
     RECT  32.533 0.096 33.973 0.648 ;
     RECT  33.901 1.728 33.973 8.568 ;
     RECT  33.865 20.16 34.009 21.048 ;
     RECT  32.404 32.496 34.076 32.52 ;
     RECT  33.973 0.096 34.162 8.568 ;
     RECT  32.668 11.616 34.213 12.552 ;
     RECT  34.162 0.096 34.301 8.616 ;
     RECT  33.829 29.04 34.405 30.6 ;
     RECT  33.473 44.448 34.441 46.632 ;
     RECT  34.301 0.096 34.451 0.6 ;
     RECT  34.297 10.368 34.549 10.392 ;
     RECT  34.213 11.376 34.549 12.552 ;
     RECT  33.577 23.808 34.549 23.832 ;
     RECT  33.793 41.04 34.621 42.648 ;
     RECT  34.441 44.352 34.621 46.632 ;
     RECT  34.549 22.944 34.657 23.832 ;
     RECT  33.433 25.632 34.657 25.656 ;
     RECT  34.301 1.776 34.729 8.616 ;
     RECT  32.404 27.888 34.729 27.912 ;
     RECT  34.405 29.04 34.729 30.696 ;
     RECT  34.729 1.776 34.805 9 ;
     RECT  34.805 2.148 34.808 9 ;
     RECT  34.549 10.368 34.808 12.552 ;
     RECT  33.797 14.304 34.808 14.712 ;
     RECT  33.797 15.84 34.808 17.064 ;
     RECT  33.653 18.096 34.808 18.792 ;
     RECT  34.009 20.112 34.808 21.048 ;
     RECT  34.657 22.896 34.808 23.832 ;
     RECT  34.657 25.056 34.808 25.656 ;
     RECT  32.404 26.688 34.808 26.712 ;
     RECT  34.729 27.888 34.808 30.696 ;
     RECT  34.076 31.872 34.808 32.52 ;
     RECT  33.437 34.896 34.808 34.92 ;
     RECT  33.469 37.008 34.808 38.424 ;
     RECT  33.329 39.6 34.808 39.864 ;
     RECT  34.621 41.04 34.808 46.632 ;
     RECT  33.683 47.664 34.808 47.688 ;
     RECT  34.808 2.148 34.912 75.612 ;
     RECT  34.912 2.418 35.104 75.342 ;
     RECT  35.104 5.184 35.201 11.448 ;
     RECT  35.104 14.208 35.201 17.16 ;
     RECT  35.104 41.04 35.201 41.16 ;
     RECT  35.201 5.664 35.219 11.448 ;
     RECT  35.104 34.176 35.245 35.352 ;
     RECT  35.104 42.192 35.267 42.552 ;
     RECT  35.104 19.92 35.273 23.16 ;
     RECT  35.104 43.536 35.309 48.504 ;
     RECT  35.201 41.04 35.345 41.064 ;
     RECT  35.201 14.208 35.381 16.968 ;
     RECT  35.245 34.176 35.381 34.632 ;
     RECT  35.219 10.368 35.453 11.448 ;
     RECT  35.309 43.536 35.453 47.688 ;
     RECT  35.104 2.88 35.561 2.904 ;
     RECT  35.273 19.92 35.561 22.632 ;
     RECT  34.451 0.096 35.633 0.456 ;
     RECT  35.219 5.664 35.633 9.288 ;
     RECT  35.104 29.616 35.644 31.32 ;
     RECT  35.453 10.368 35.669 10.872 ;
     RECT  35.104 37.104 35.669 39.864 ;
     RECT  35.453 44.928 35.741 47.688 ;
     RECT  35.741 47.616 35.849 47.688 ;
     RECT  35.267 42.192 35.891 42.216 ;
     RECT  35.633 0.192 35.921 0.456 ;
     RECT  35.669 37.68 35.957 39.864 ;
     RECT  35.633 6.336 36.029 9.288 ;
     RECT  35.381 15.408 36.065 16.968 ;
     RECT  36.065 15.84 36.188 16.968 ;
     RECT  35.104 18.144 36.188 18.84 ;
     RECT  35.381 14.208 36.229 14.424 ;
     RECT  35.453 43.536 36.268 43.8 ;
     RECT  36.229 13.584 36.275 14.424 ;
     RECT  36.188 15.84 36.275 18.84 ;
     RECT  35.741 44.928 36.317 46.248 ;
     RECT  35.921 0.288 36.353 0.456 ;
     RECT  35.644 29.856 36.421 31.32 ;
     RECT  35.104 32.304 36.421 32.808 ;
     RECT  36.385 40.944 36.421 40.968 ;
     RECT  36.205 42 36.421 42.024 ;
     RECT  35.561 20.928 36.469 22.632 ;
     RECT  36.421 40.848 36.493 42.024 ;
     RECT  36.275 18.24 36.524 18.84 ;
     RECT  35.561 19.92 36.524 19.944 ;
     RECT  36.353 0.288 36.533 0.312 ;
     RECT  36.268 43.536 36.533 43.56 ;
     RECT  35.104 51.072 36.533 52.44 ;
     RECT  36.524 18.24 36.565 19.944 ;
     RECT  36.469 20.928 36.565 23.448 ;
     RECT  35.104 26.736 36.668 26.76 ;
     RECT  36.493 28.416 36.668 28.44 ;
     RECT  35.669 10.848 36.709 10.872 ;
     RECT  35.104 12.528 36.709 12.552 ;
     RECT  36.668 26.736 36.709 28.44 ;
     RECT  36.421 29.856 36.709 32.808 ;
     RECT  35.849 47.664 36.745 47.688 ;
     RECT  36.533 51.072 36.745 51.912 ;
     RECT  36.745 24.96 36.805 24.984 ;
     RECT  36.313 36.432 36.853 36.456 ;
     RECT  35.957 37.68 36.853 39.816 ;
     RECT  36.709 10.848 36.917 12.552 ;
     RECT  36.275 13.584 36.917 13.944 ;
     RECT  36.805 24.624 36.961 24.984 ;
     RECT  36.745 47.664 36.961 48.456 ;
     RECT  36.029 6.96 37.237 9.288 ;
     RECT  36.961 24.624 37.249 25.656 ;
     RECT  36.709 26.736 37.249 32.808 ;
     RECT  37.237 6.816 37.333 9.288 ;
     RECT  36.917 10.848 37.333 13.944 ;
     RECT  36.275 15.84 37.357 16.968 ;
     RECT  36.961 47.664 37.357 48.792 ;
     RECT  36.097 53.568 37.357 53.592 ;
     RECT  37.249 54.672 37.357 55.272 ;
     RECT  37.249 24.624 37.393 32.808 ;
     RECT  35.381 34.176 37.393 34.2 ;
     RECT  36.317 44.928 37.393 46.008 ;
     RECT  37.357 47.088 37.393 48.792 ;
     RECT  37.333 6.816 37.465 13.944 ;
     RECT  37.465 6.816 37.508 14.184 ;
     RECT  37.357 15.216 37.508 16.968 ;
     RECT  36.565 18.24 37.508 23.448 ;
     RECT  37.393 24.624 37.508 34.2 ;
     RECT  37.033 35.424 37.508 35.448 ;
     RECT  36.853 36.432 37.508 39.816 ;
     RECT  36.493 40.8 37.508 42.024 ;
     RECT  37.249 43.008 37.508 43.08 ;
     RECT  37.393 44.928 37.508 48.792 ;
     RECT  36.745 50.928 37.508 51.912 ;
     RECT  37.357 53.568 37.508 55.272 ;
     RECT  37.508 2.148 37.612 75.612 ;
     RECT  37.612 2.418 37.804 75.342 ;
     RECT  37.804 37.392 37.829 41.448 ;
     RECT  37.804 44.928 37.865 48.792 ;
     RECT  37.865 44.928 37.901 48.264 ;
     RECT  37.804 52.992 37.901 55.8 ;
     RECT  37.804 27.36 37.937 27.384 ;
     RECT  37.804 50.4 37.955 51.912 ;
     RECT  37.804 12.384 38.045 16.536 ;
     RECT  37.804 23.856 38.189 26.136 ;
     RECT  37.804 17.808 38.195 19.032 ;
     RECT  37.901 52.992 38.225 54.648 ;
     RECT  37.804 28.416 38.261 28.44 ;
     RECT  38.045 15.216 38.297 16.536 ;
     RECT  37.901 47.328 38.297 48.264 ;
     RECT  37.804 10.8 38.333 10.92 ;
     RECT  37.955 50.4 38.449 51.528 ;
     RECT  37.829 37.824 38.483 41.448 ;
     RECT  37.804 7.68 38.513 9 ;
     RECT  37.804 42.768 38.513 42.792 ;
     RECT  38.225 53.136 38.513 54.648 ;
     RECT  37.901 55.776 38.513 55.8 ;
     RECT  37.804 33.648 38.621 33.672 ;
     RECT  38.513 54.624 38.621 54.648 ;
     RECT  37.804 34.752 38.797 35.448 ;
     RECT  38.483 41.376 38.869 41.448 ;
     RECT  38.797 34.752 38.917 35.832 ;
     RECT  38.483 37.824 38.945 40.392 ;
     RECT  37.804 22.752 39.049 22.776 ;
     RECT  38.045 12.384 39.053 14.184 ;
     RECT  38.449 50.4 39.157 50.424 ;
     RECT  38.189 24.192 39.229 26.136 ;
     RECT  38.513 53.136 39.229 53.592 ;
     RECT  39.049 22.608 39.265 22.776 ;
     RECT  38.513 7.68 39.301 8.664 ;
     RECT  38.917 34.752 39.301 36.456 ;
     RECT  38.449 51.504 39.308 51.528 ;
     RECT  39.229 52.896 39.308 53.592 ;
     RECT  39.121 43.056 39.373 43.08 ;
     RECT  37.901 44.928 39.373 46.296 ;
     RECT  38.297 47.328 39.373 47.976 ;
     RECT  39.373 44.928 39.409 47.976 ;
     RECT  38.195 18.72 39.445 19.032 ;
     RECT  37.804 20.112 39.445 21.144 ;
     RECT  38.945 39.792 39.445 40.392 ;
     RECT  38.869 41.376 39.445 41.496 ;
     RECT  39.265 22.464 39.481 22.776 ;
     RECT  39.229 24.192 39.481 26.28 ;
     RECT  38.297 15.456 39.553 16.536 ;
     RECT  37.804 29.616 39.637 32.328 ;
     RECT  39.157 49.824 39.661 50.424 ;
     RECT  39.308 51.504 39.661 53.592 ;
     RECT  39.637 28.992 39.685 32.328 ;
     RECT  39.301 34.368 39.697 36.456 ;
     RECT  39.373 55.68 39.697 55.704 ;
     RECT  39.697 55.68 39.733 56.568 ;
     RECT  39.661 49.824 39.805 53.592 ;
     RECT  39.373 43.056 39.877 43.32 ;
     RECT  39.733 55.68 39.913 56.808 ;
     RECT  39.553 15.36 39.949 16.536 ;
     RECT  39.877 42.864 39.985 43.32 ;
     RECT  39.805 49.824 40.013 54.456 ;
     RECT  39.445 39.792 40.021 41.496 ;
     RECT  39.985 42.768 40.021 43.32 ;
     RECT  39.301 6.816 40.057 8.664 ;
     RECT  40.021 39.792 40.057 43.32 ;
     RECT  39.409 44.352 40.057 47.976 ;
     RECT  39.481 22.464 40.069 26.28 ;
     RECT  40.057 6.048 40.208 8.664 ;
     RECT  38.333 10.8 40.208 10.824 ;
     RECT  39.053 12.384 40.208 13.032 ;
     RECT  39.949 15.264 40.208 16.536 ;
     RECT  39.445 18.72 40.208 21.144 ;
     RECT  40.069 22.464 40.208 26.328 ;
     RECT  39.685 28.992 40.208 32.76 ;
     RECT  39.697 34.368 40.208 36.648 ;
     RECT  38.945 37.824 40.208 38.52 ;
     RECT  40.057 39.744 40.208 47.976 ;
     RECT  40.013 49.008 40.208 54.456 ;
     RECT  39.913 55.68 40.208 56.856 ;
     RECT  40.208 2.148 40.312 75.612 ;
     RECT  40.312 2.418 40.504 75.342 ;
     RECT  40.504 44.928 40.529 47.352 ;
     RECT  40.504 35.808 40.601 35.832 ;
     RECT  40.504 29.856 40.637 32.472 ;
     RECT  40.504 56.736 40.637 57.096 ;
     RECT  40.504 39.792 40.673 43.608 ;
     RECT  40.504 7.632 40.817 8.568 ;
     RECT  40.637 56.784 40.817 57.096 ;
     RECT  40.673 41.424 40.889 43.608 ;
     RECT  40.504 14.352 40.931 26.328 ;
     RECT  40.817 56.832 41.033 57.096 ;
     RECT  40.931 14.352 41.141 14.76 ;
     RECT  40.529 44.928 41.141 46.104 ;
     RECT  41.141 44.928 41.177 45.816 ;
     RECT  40.931 21.6 41.213 26.328 ;
     RECT  40.504 34.368 41.285 34.44 ;
     RECT  40.504 12.864 41.357 13.128 ;
     RECT  40.931 16.08 41.459 20.328 ;
     RECT  41.459 17.136 41.465 20.328 ;
     RECT  41.285 34.368 41.497 34.392 ;
     RECT  41.033 57.024 41.497 57.096 ;
     RECT  40.637 30 41.507 32.472 ;
     RECT  41.357 13.056 41.537 13.128 ;
     RECT  40.504 49.152 41.564 51.816 ;
     RECT  40.504 28.464 41.605 28.488 ;
     RECT  40.504 53.328 41.605 54.696 ;
     RECT  41.605 52.992 41.641 54.696 ;
     RECT  40.504 55.68 41.641 55.704 ;
     RECT  41.537 13.104 41.645 13.128 ;
     RECT  41.213 21.648 41.645 26.328 ;
     RECT  41.564 49.152 41.645 51.864 ;
     RECT  41.645 50.64 41.651 51.864 ;
     RECT  40.889 42.24 41.681 43.608 ;
     RECT  41.641 52.992 41.681 55.704 ;
     RECT  41.605 28.464 41.713 29.064 ;
     RECT  41.507 30.096 41.825 32.472 ;
     RECT  40.504 6.048 41.845 6.312 ;
     RECT  40.817 7.632 41.845 8.184 ;
     RECT  41.177 45.696 41.897 45.816 ;
     RECT  41.681 52.992 41.933 55.464 ;
     RECT  41.713 28.272 41.965 29.064 ;
     RECT  40.504 37.008 41.965 38.808 ;
     RECT  40.673 39.792 41.965 40.44 ;
     RECT  41.845 6.048 42.001 8.184 ;
     RECT  40.529 47.328 42.001 47.352 ;
     RECT  42.001 5.856 42.073 8.184 ;
     RECT  41.459 16.08 42.133 16.104 ;
     RECT  41.681 43.056 42.145 43.608 ;
     RECT  41.141 14.736 42.181 14.76 ;
     RECT  42.181 14.688 42.217 14.76 ;
     RECT  42.001 47.328 42.325 47.688 ;
     RECT  41.645 49.152 42.325 49.512 ;
     RECT  42.073 5.76 42.433 8.184 ;
     RECT  42.217 14.688 42.433 14.808 ;
     RECT  42.133 15.936 42.433 16.104 ;
     RECT  41.645 22.176 42.613 26.328 ;
     RECT  41.497 34.176 42.613 34.392 ;
     RECT  42.253 36 42.613 36.024 ;
     RECT  41.965 37.008 42.613 40.488 ;
     RECT  42.613 34.176 42.649 36.024 ;
     RECT  41.933 55.392 42.685 55.464 ;
     RECT  41.497 57.024 42.685 57.432 ;
     RECT  41.465 17.136 42.721 19.176 ;
     RECT  41.465 20.304 42.721 20.328 ;
     RECT  42.721 17.136 42.757 20.328 ;
     RECT  42.145 43.056 42.757 44.184 ;
     RECT  42.433 5.76 42.908 9.048 ;
     RECT  42.433 14.688 42.908 16.104 ;
     RECT  42.757 17.136 42.908 20.376 ;
     RECT  42.613 21.456 42.908 26.328 ;
     RECT  41.965 27.648 42.908 29.064 ;
     RECT  41.825 30.096 42.908 32.28 ;
     RECT  42.649 33.936 42.908 36.024 ;
     RECT  42.613 37.008 42.908 41.16 ;
     RECT  42.757 42.72 42.908 44.184 ;
     RECT  41.897 45.744 42.908 45.816 ;
     RECT  42.325 47.328 42.908 49.512 ;
     RECT  41.651 50.64 42.908 51.816 ;
     RECT  41.933 52.992 42.908 54.216 ;
     RECT  42.685 55.392 42.908 57.432 ;
     RECT  42.908 2.148 43.012 75.612 ;
     RECT  43.012 2.418 43.117 75.612 ;
     RECT  43.045 0.096 43.187 0.12 ;
     RECT  43.117 2.418 43.201 75.816 ;
     RECT  43.201 2.418 43.204 75.342 ;
     RECT  43.204 5.76 43.265 5.784 ;
     RECT  43.204 37.872 43.331 41.16 ;
     RECT  43.204 42.672 43.372 44.232 ;
     RECT  43.204 49.488 43.373 54.216 ;
     RECT  43.204 56.976 43.373 57.336 ;
     RECT  43.204 22.224 43.409 25.752 ;
     RECT  43.372 42.816 43.409 44.232 ;
     RECT  43.409 25.68 43.445 25.752 ;
     RECT  43.331 38.016 43.517 41.16 ;
     RECT  43.204 14.784 43.571 16.104 ;
     RECT  43.409 42.816 43.589 43.08 ;
     RECT  43.445 25.68 43.733 25.704 ;
     RECT  43.204 29.808 43.733 36.024 ;
     RECT  43.409 44.208 43.877 44.232 ;
     RECT  43.204 26.736 43.907 28.68 ;
     RECT  43.409 22.224 43.913 24.216 ;
     RECT  43.733 29.808 43.955 35.88 ;
     RECT  43.204 55.392 43.985 55.416 ;
     RECT  43.955 33.936 44.021 35.88 ;
     RECT  43.373 49.488 44.021 50.184 ;
     RECT  43.373 56.976 44.057 57.144 ;
     RECT  44.057 56.976 44.129 57 ;
     RECT  43.204 7.2 44.165 9.048 ;
     RECT  44.021 33.936 44.165 34.92 ;
     RECT  44.165 7.2 44.305 8.184 ;
     RECT  44.305 6.816 44.387 8.184 ;
     RECT  44.387 6.816 44.389 6.84 ;
     RECT  43.204 17.472 44.453 18.792 ;
     RECT  43.589 42.816 44.521 42.84 ;
     RECT  43.204 46.08 44.597 47.064 ;
     RECT  43.571 15.408 44.629 16.104 ;
     RECT  43.373 51.216 44.809 54.216 ;
     RECT  44.453 17.952 44.881 18.792 ;
     RECT  43.204 19.92 44.881 20.904 ;
     RECT  44.881 17.952 44.917 20.904 ;
     RECT  43.913 22.512 44.917 24.216 ;
     RECT  43.955 29.808 44.917 32.712 ;
     RECT  43.907 26.832 45.025 27.624 ;
     RECT  43.907 28.656 45.025 28.68 ;
     RECT  43.517 38.016 45.025 40.44 ;
     RECT  44.021 50.16 45.061 50.184 ;
     RECT  44.521 42.48 45.097 42.84 ;
     RECT  44.629 14.88 45.116 16.104 ;
     RECT  45.116 14.88 45.157 16.488 ;
     RECT  44.917 29.808 45.313 33.384 ;
     RECT  44.917 17.952 45.359 24.216 ;
     RECT  44.485 25.44 45.359 25.464 ;
     RECT  45.061 49.296 45.529 50.184 ;
     RECT  44.809 51.216 45.529 54.888 ;
     RECT  44.387 7.824 45.608 8.184 ;
     RECT  45.157 14.784 45.608 16.488 ;
     RECT  45.359 17.952 45.608 25.464 ;
     RECT  45.025 26.832 45.608 28.68 ;
     RECT  45.313 29.808 45.608 33.672 ;
     RECT  44.165 34.896 45.608 34.92 ;
     RECT  45.025 37.968 45.608 40.44 ;
     RECT  45.097 42.48 45.608 43.56 ;
     RECT  44.953 44.976 45.608 45 ;
     RECT  44.597 46.08 45.608 46.104 ;
     RECT  44.701 47.952 45.608 47.976 ;
     RECT  45.529 49.296 45.608 54.888 ;
     RECT  44.773 56.544 45.608 56.568 ;
     RECT  45.608 2.148 45.712 75.612 ;
     RECT  45.712 2.418 45.904 75.342 ;
     RECT  45.904 35.712 46.001 36.024 ;
     RECT  45.904 51.216 46.156 54.216 ;
     RECT  45.904 20.88 46.181 21.72 ;
     RECT  46.156 53.04 46.181 54.216 ;
     RECT  45.904 42.144 46.217 49.32 ;
     RECT  45.904 17.952 46.289 19.416 ;
     RECT  46.156 51.216 46.289 51.48 ;
     RECT  46.181 21.072 46.325 21.72 ;
     RECT  45.904 40.128 46.361 40.152 ;
     RECT  45.904 55.296 46.361 56.616 ;
     RECT  45.904 9.744 46.397 9.768 ;
     RECT  46.289 18.192 46.397 19.416 ;
     RECT  45.904 29.808 46.577 34.2 ;
     RECT  46.181 53.04 46.685 53.064 ;
     RECT  45.904 6.24 46.739 6.84 ;
     RECT  46.217 42.144 46.739 49.128 ;
     RECT  46.325 21.12 46.757 21.72 ;
     RECT  46.757 21.648 46.765 21.72 ;
     RECT  45.904 14.544 46.787 16.536 ;
     RECT  45.904 22.704 46.787 24.648 ;
     RECT  46.787 14.544 46.901 15.096 ;
     RECT  46.739 44.448 46.924 49.128 ;
     RECT  46.397 18.96 46.937 19.416 ;
     RECT  46.577 30.144 47.009 34.2 ;
     RECT  46.924 45.984 47.045 49.128 ;
     RECT  47.009 30.528 47.075 34.2 ;
     RECT  46.001 36 47.149 36.024 ;
     RECT  47.045 47.904 47.153 49.128 ;
     RECT  46.181 54.048 47.185 54.216 ;
     RECT  46.787 23.76 47.261 24.648 ;
     RECT  45.904 37.392 47.297 38.952 ;
     RECT  45.904 27.12 47.333 28.488 ;
     RECT  47.185 53.664 47.473 54.216 ;
     RECT  46.361 55.92 47.605 56.616 ;
     RECT  47.261 24.192 47.653 24.648 ;
     RECT  47.333 27.12 47.689 27.912 ;
     RECT  47.297 37.44 47.855 38.952 ;
     RECT  47.605 55.68 47.905 56.616 ;
     RECT  47.855 37.44 48.049 39.672 ;
     RECT  47.689 26.784 48.121 27.912 ;
     RECT  46.739 42.144 48.121 43.32 ;
     RECT  46.924 44.448 48.121 44.472 ;
     RECT  46.901 14.976 48.181 15.096 ;
     RECT  46.787 16.08 48.181 16.536 ;
     RECT  45.904 8.16 48.193 8.712 ;
     RECT  46.765 21.696 48.265 21.72 ;
     RECT  46.739 6.816 48.308 6.84 ;
     RECT  48.193 8.16 48.308 8.808 ;
     RECT  48.181 13.632 48.308 16.536 ;
     RECT  48.265 17.712 48.308 17.736 ;
     RECT  46.937 18.96 48.308 19.368 ;
     RECT  48.265 21.216 48.308 21.72 ;
     RECT  46.787 22.704 48.308 22.728 ;
     RECT  47.653 24.192 48.308 25.512 ;
     RECT  48.121 26.64 48.308 27.912 ;
     RECT  47.075 30.864 48.308 34.2 ;
     RECT  47.149 35.424 48.308 36.024 ;
     RECT  48.049 37.44 48.308 39.864 ;
     RECT  48.121 42.144 48.308 44.472 ;
     RECT  47.045 45.984 48.308 46.824 ;
     RECT  47.153 47.904 48.308 49.032 ;
     RECT  46.289 51.216 48.308 51.24 ;
     RECT  47.473 53.664 48.308 54.504 ;
     RECT  47.905 55.68 48.308 57 ;
     RECT  48.308 2.148 48.412 75.612 ;
     RECT  48.412 2.418 48.604 75.342 ;
     RECT  48.604 23.184 48.629 26.856 ;
     RECT  48.604 30.768 48.917 34.2 ;
     RECT  48.604 8.16 48.947 9.096 ;
     RECT  48.604 10.32 48.989 10.344 ;
     RECT  48.604 36.48 49.061 38.232 ;
     RECT  48.604 50.112 49.091 53.88 ;
     RECT  48.629 23.184 49.205 26.808 ;
     RECT  49.091 50.112 49.205 50.712 ;
     RECT  48.604 15.552 49.277 19.944 ;
     RECT  48.917 30.768 49.277 33.912 ;
     RECT  48.604 13.632 49.349 13.656 ;
     RECT  48.604 27.888 49.427 29.496 ;
     RECT  49.277 30.768 49.457 33.48 ;
     RECT  49.427 28.944 49.529 29.496 ;
     RECT  49.277 19.104 49.571 19.944 ;
     RECT  49.571 19.344 49.573 19.944 ;
     RECT  48.604 20.976 49.573 21.72 ;
     RECT  49.091 51.84 49.573 53.88 ;
     RECT  49.205 24.96 49.597 26.808 ;
     RECT  49.573 51.84 49.619 54.168 ;
     RECT  48.604 6.816 49.637 6.84 ;
     RECT  48.604 40.656 49.637 40.68 ;
     RECT  49.573 19.344 49.66 21.72 ;
     RECT  49.277 15.552 49.673 17.736 ;
     RECT  49.66 21.696 49.673 21.72 ;
     RECT  48.604 43.536 49.709 43.608 ;
     RECT  48.604 45.168 49.741 45.192 ;
     RECT  49.673 15.552 49.813 16.872 ;
     RECT  49.619 54.144 49.853 54.168 ;
     RECT  48.947 8.16 49.859 8.184 ;
     RECT  49.66 19.344 49.859 20.328 ;
     RECT  48.604 55.68 49.993 55.704 ;
     RECT  49.597 24.96 50.101 26.856 ;
     RECT  49.619 51.84 50.101 52.824 ;
     RECT  49.741 45.024 50.281 45.192 ;
     RECT  48.604 46.8 50.281 46.824 ;
     RECT  50.101 24.96 50.461 26.904 ;
     RECT  49.427 27.888 50.461 27.912 ;
     RECT  50.281 45.024 50.713 46.824 ;
     RECT  50.605 49.152 50.713 49.176 ;
     RECT  50.461 50.304 50.713 50.328 ;
     RECT  49.859 19.776 50.725 20.328 ;
     RECT  49.061 38.208 50.749 38.232 ;
     RECT  49.457 30.768 50.785 33.384 ;
     RECT  50.713 44.64 50.785 46.824 ;
     RECT  50.713 49.152 50.821 50.328 ;
     RECT  50.461 24.96 50.869 27.912 ;
     RECT  49.529 28.944 50.869 28.968 ;
     RECT  50.785 30.768 50.893 33.72 ;
     RECT  49.813 15.312 50.929 16.872 ;
     RECT  50.029 9.024 51.008 9.048 ;
     RECT  50.929 15.312 51.008 16.92 ;
     RECT  50.965 18.768 51.008 18.792 ;
     RECT  50.725 19.776 51.008 20.712 ;
     RECT  49.205 23.184 51.008 23.928 ;
     RECT  50.869 24.96 51.008 29.64 ;
     RECT  50.893 30.768 51.008 33.912 ;
     RECT  48.604 35.28 51.008 35.448 ;
     RECT  49.061 36.48 51.008 36.504 ;
     RECT  50.749 38.208 51.008 39.192 ;
     RECT  49.709 43.536 51.008 43.56 ;
     RECT  50.785 44.64 51.008 47.064 ;
     RECT  50.821 49.152 51.008 50.424 ;
     RECT  50.101 51.648 51.008 52.824 ;
     RECT  49.993 55.68 51.008 56.376 ;
     RECT  51.008 2.148 51.112 75.612 ;
     RECT  51.112 2.418 51.304 75.342 ;
     RECT  51.304 26.64 51.473 26.664 ;
     RECT  51.304 40.32 51.509 40.344 ;
     RECT  51.304 45.552 51.509 47.064 ;
     RECT  51.304 19.776 51.617 20.712 ;
     RECT  51.304 24.768 51.725 25.656 ;
     RECT  51.304 50.112 51.833 50.328 ;
     RECT  51.304 52.8 51.833 54.168 ;
     RECT  51.833 52.8 51.869 52.824 ;
     RECT  51.304 16.752 51.923 17.688 ;
     RECT  51.304 15.312 51.969 15.624 ;
     RECT  51.617 20.688 52.049 20.712 ;
     RECT  51.833 50.304 52.121 50.328 ;
     RECT  51.304 55.296 52.157 55.704 ;
     RECT  51.923 16.944 52.193 17.688 ;
     RECT  51.304 38.208 52.297 39.048 ;
     RECT  51.304 42.912 52.297 42.984 ;
     RECT  51.304 27.888 52.333 28.44 ;
     RECT  51.304 9.024 52.364 9.048 ;
     RECT  51.304 29.616 52.373 29.64 ;
     RECT  51.304 30.672 52.373 35.448 ;
     RECT  52.364 9.024 52.405 9.192 ;
     RECT  51.725 25.056 52.405 25.656 ;
     RECT  52.333 26.784 52.445 28.44 ;
     RECT  52.333 49.248 52.445 49.272 ;
     RECT  52.405 8.496 52.451 9.192 ;
     RECT  52.364 12.384 52.451 12.408 ;
     RECT  52.364 15.12 52.451 15.144 ;
     RECT  52.445 26.784 52.451 27.336 ;
     RECT  52.445 28.416 52.589 28.44 ;
     RECT  52.297 38.208 52.625 39.144 ;
     RECT  51.833 54.144 52.625 54.168 ;
     RECT  51.304 22.8 52.685 23.784 ;
     RECT  52.373 30.864 52.693 35.448 ;
     RECT  51.304 36.528 52.693 36.552 ;
     RECT  51.304 51.744 52.693 51.768 ;
     RECT  52.685 22.752 52.729 23.784 ;
     RECT  52.585 40.416 52.729 40.44 ;
     RECT  52.549 49.056 52.729 49.08 ;
     RECT  52.297 42.912 52.733 43.08 ;
     RECT  52.729 22.176 52.739 23.784 ;
     RECT  52.733 43.056 52.801 43.08 ;
     RECT  52.801 43.056 52.873 43.512 ;
     RECT  52.729 40.32 53.053 40.44 ;
     RECT  52.693 51.696 53.161 51.768 ;
     RECT  52.157 55.68 53.305 55.704 ;
     RECT  51.304 18.768 53.377 18.792 ;
     RECT  53.377 18.768 53.557 19.368 ;
     RECT  52.405 25.056 53.629 25.752 ;
     RECT  52.451 8.496 53.708 8.52 ;
     RECT  52.193 16.944 53.708 16.968 ;
     RECT  53.557 18.192 53.708 20.328 ;
     RECT  52.739 22.176 53.708 22.824 ;
     RECT  53.629 24.192 53.708 25.752 ;
     RECT  52.451 27.312 53.708 27.336 ;
     RECT  52.693 30.864 53.708 36.552 ;
     RECT  52.625 38.208 53.708 38.712 ;
     RECT  53.053 40.32 53.708 41.256 ;
     RECT  52.873 43.056 53.708 43.56 ;
     RECT  52.945 44.64 53.708 44.664 ;
     RECT  51.509 45.696 53.708 47.064 ;
     RECT  52.729 48.48 53.708 49.08 ;
     RECT  52.405 50.352 53.708 50.376 ;
     RECT  53.161 51.696 53.708 52.536 ;
     RECT  53.305 55.44 53.708 55.704 ;
     RECT  53.708 2.148 53.812 75.612 ;
     RECT  53.812 2.418 54.004 75.342 ;
     RECT  54.004 40.416 54.137 41.4 ;
     RECT  54.004 30.864 54.173 33.384 ;
     RECT  54.004 34.368 54.389 34.824 ;
     RECT  54.004 43.008 54.389 47.592 ;
     RECT  54.004 55.44 54.497 56.04 ;
     RECT  54.004 53.76 54.515 53.784 ;
     RECT  54.389 43.008 54.707 45.624 ;
     RECT  54.137 41.376 54.749 41.4 ;
     RECT  54.707 44.592 54.755 45.624 ;
     RECT  54.707 43.008 54.785 43.128 ;
     RECT  54.755 44.592 54.793 45 ;
     RECT  54.389 46.752 54.821 47.592 ;
     RECT  54.785 43.008 54.929 43.08 ;
     RECT  54.004 36.528 54.965 36.84 ;
     RECT  54.497 56.016 55.001 56.04 ;
     RECT  54.793 44.592 55.037 44.616 ;
     RECT  54.004 52.176 55.105 52.776 ;
     RECT  54.173 30.864 55.177 33.336 ;
     RECT  54.389 34.368 55.177 34.392 ;
     RECT  54.965 36.816 55.177 36.84 ;
     RECT  55.177 36.816 55.393 37.608 ;
     RECT  54.004 38.688 55.393 38.712 ;
     RECT  54.821 46.8 55.433 47.592 ;
     RECT  55.177 30.864 55.465 34.392 ;
     RECT  55.105 51.168 55.789 52.776 ;
     RECT  55.393 36.816 55.897 38.712 ;
     RECT  55.897 36.816 55.933 39.336 ;
     RECT  55.861 40.848 55.933 40.872 ;
     RECT  55.969 53.808 56.041 53.832 ;
     RECT  55.933 36.816 56.077 39.576 ;
     RECT  55.933 40.848 56.077 41.496 ;
     RECT  56.005 45.504 56.077 45.528 ;
     RECT  55.789 50.928 56.257 52.776 ;
     RECT  56.041 53.808 56.257 53.928 ;
     RECT  56.077 36.816 56.265 41.496 ;
     RECT  56.077 45.264 56.365 45.528 ;
     RECT  55.465 30.864 56.408 35.016 ;
     RECT  56.265 36.816 56.408 41.688 ;
     RECT  54.929 43.008 56.408 43.032 ;
     RECT  56.365 45.168 56.408 45.528 ;
     RECT  55.433 46.8 56.408 46.872 ;
     RECT  55.501 47.952 56.408 47.976 ;
     RECT  56.257 50.928 56.408 53.928 ;
     RECT  56.185 54.96 56.408 54.984 ;
     RECT  56.408 2.148 56.512 75.612 ;
     RECT  56.512 2.418 56.704 75.342 ;
     RECT  56.704 46.608 56.873 46.92 ;
     RECT  56.704 53.808 56.873 55.176 ;
     RECT  56.704 35.712 56.909 44.184 ;
     RECT  56.873 54.912 56.945 55.176 ;
     RECT  56.704 52.272 56.981 52.296 ;
     RECT  56.704 45.168 57.053 45.576 ;
     RECT  57.053 45.456 57.059 45.576 ;
     RECT  56.873 53.808 57.089 53.832 ;
     RECT  56.704 47.952 57.233 48.456 ;
     RECT  56.909 35.712 57.269 39.864 ;
     RECT  56.909 40.944 57.377 44.184 ;
     RECT  57.377 42.816 57.413 44.184 ;
     RECT  56.704 30.864 57.485 33 ;
     RECT  57.413 42.816 57.485 43.704 ;
     RECT  57.059 45.456 57.629 45.528 ;
     RECT  57.233 47.952 57.665 47.976 ;
     RECT  56.704 34.32 57.701 34.44 ;
     RECT  57.377 40.944 57.701 41.64 ;
     RECT  57.701 34.32 57.733 34.392 ;
     RECT  57.485 31.728 57.769 33 ;
     RECT  57.701 40.944 57.809 41.544 ;
     RECT  57.769 31.728 57.845 33.048 ;
     RECT  56.704 50.928 57.953 50.952 ;
     RECT  57.809 40.944 58.057 41.496 ;
     RECT  57.845 32.016 58.061 33.048 ;
     RECT  57.269 35.712 58.097 39.384 ;
     RECT  58.097 35.712 58.133 35.736 ;
     RECT  58.129 52.56 58.273 52.584 ;
     RECT  58.273 52.56 58.345 52.776 ;
     RECT  56.945 54.912 58.345 55.08 ;
     RECT  56.873 46.848 58.381 46.92 ;
     RECT  57.733 34.224 58.633 34.392 ;
     RECT  57.629 45.504 58.633 45.528 ;
     RECT  58.381 46.848 58.633 47.208 ;
     RECT  58.633 34.128 58.777 34.392 ;
     RECT  58.057 40.368 58.885 41.496 ;
     RECT  58.885 40.368 58.892 41.736 ;
     RECT  57.485 42.816 58.892 43.656 ;
     RECT  58.061 32.016 59.108 32.664 ;
     RECT  58.777 34.128 59.108 34.68 ;
     RECT  58.097 36.864 59.108 39.384 ;
     RECT  58.892 40.368 59.108 43.656 ;
     RECT  58.633 45.504 59.108 47.208 ;
     RECT  58.885 48.432 59.108 48.456 ;
     RECT  56.704 49.776 59.108 49.8 ;
     RECT  58.345 52.56 59.108 53.064 ;
     RECT  58.345 54.864 59.108 55.08 ;
     RECT  59.108 2.148 59.212 75.612 ;
     RECT  59.212 2.418 59.404 75.342 ;
     RECT  59.404 32.592 59.465 33.096 ;
     RECT  59.404 35.952 59.501 44.472 ;
     RECT  59.404 48.432 59.555 48.456 ;
     RECT  59.404 45.552 59.596 46.872 ;
     RECT  59.501 40.08 59.645 44.472 ;
     RECT  59.645 40.08 59.861 41.544 ;
     RECT  59.501 35.952 59.897 38.808 ;
     RECT  59.465 32.592 59.933 32.856 ;
     RECT  59.933 32.832 60.113 32.856 ;
     RECT  59.897 35.952 60.221 38.52 ;
     RECT  59.596 45.552 60.257 45.72 ;
     RECT  59.404 34.176 60.469 34.68 ;
     RECT  60.221 35.952 60.469 38.232 ;
     RECT  59.645 42.528 60.469 44.472 ;
     RECT  59.861 40.944 60.649 41.544 ;
     RECT  60.469 42.528 60.649 45.192 ;
     RECT  60.505 49.008 60.685 49.032 ;
     RECT  60.685 49.008 60.689 49.56 ;
     RECT  60.649 40.944 60.797 45.192 ;
     RECT  60.689 49.392 61.369 49.56 ;
     RECT  61.369 49.392 61.585 49.896 ;
     RECT  61.505 51.072 61.585 51.096 ;
     RECT  60.469 34.176 61.808 38.232 ;
     RECT  60.797 41.04 61.808 45.192 ;
     RECT  59.596 46.848 61.808 46.872 ;
     RECT  61.585 49.392 61.808 51.096 ;
     RECT  61.808 2.148 61.912 75.612 ;
     RECT  61.912 2.418 62.104 75.342 ;
     RECT  62.104 34.752 62.165 36.072 ;
     RECT  62.104 41.04 62.417 41.496 ;
     RECT  62.104 49.536 62.453 51.48 ;
     RECT  62.104 46.368 62.597 47.16 ;
     RECT  62.453 51.456 62.705 51.48 ;
     RECT  62.453 49.536 62.777 49.896 ;
     RECT  62.165 34.752 62.849 35.736 ;
     RECT  62.104 37.632 63.065 38.232 ;
     RECT  62.104 42.48 63.101 45.192 ;
     RECT  63.101 42.48 63.109 43.896 ;
     RECT  62.417 41.04 63.281 41.064 ;
     RECT  62.849 34.752 63.299 35.352 ;
     RECT  63.065 37.68 63.317 38.232 ;
     RECT  63.299 35.328 63.497 35.352 ;
     RECT  63.101 44.976 63.709 45.192 ;
     RECT  63.317 38.208 63.853 38.232 ;
     RECT  63.601 39.504 63.853 39.528 ;
     RECT  63.853 38.208 64.141 39.528 ;
     RECT  63.673 52.08 64.429 52.104 ;
     RECT  64.141 38.208 64.508 40.056 ;
     RECT  63.109 42.432 64.508 43.896 ;
     RECT  63.709 44.976 64.508 45.24 ;
     RECT  62.597 46.368 64.508 46.392 ;
     RECT  63.457 49.488 64.508 49.512 ;
     RECT  63.961 50.88 64.508 50.904 ;
     RECT  64.429 52.08 64.508 52.728 ;
     RECT  64.508 2.148 64.612 75.612 ;
     RECT  64.612 2.418 64.804 75.342 ;
     RECT  64.804 38.208 64.931 40.056 ;
     RECT  64.931 38.208 65.297 39.096 ;
     RECT  64.804 51.936 65.297 51.96 ;
     RECT  65.297 38.208 67.208 38.232 ;
     RECT  67.208 2.148 67.312 75.612 ;
     RECT  67.312 2.418 67.504 75.342 ;
     RECT  67.504 38.208 69.908 38.232 ;
     RECT  69.908 2.148 70.012 75.612 ;
     RECT  70.012 2.418 70.204 75.342 ;
     RECT  70.204 38.208 72.608 38.232 ;
     RECT  72.608 2.148 72.712 75.612 ;
     RECT  72.712 2.418 72.904 75.342 ;
     RECT  72.904 38.208 75.308 38.232 ;
     RECT  75.308 2.148 75.412 75.612 ;
     RECT  75.412 2.418 75.604 75.342 ;
     RECT  75.604 38.208 78.008 38.232 ;
     RECT  78.008 2.148 78.112 75.612 ;
     RECT  78.112 2.418 78.304 75.342 ;
     RECT  78.304 38.208 80.708 38.232 ;
     RECT  80.708 2.148 80.812 75.612 ;
     RECT  80.812 2.418 81.004 75.342 ;
     RECT  81.004 38.208 83.408 38.232 ;
     RECT  83.408 2.148 83.512 75.612 ;
     RECT  83.512 2.418 83.704 75.342 ;
     RECT  83.704 38.208 86.281 38.232 ;
    LAYER M5 ;
     RECT  28.032 0.016 34.296 0.565 ;
     RECT  28.032 0.565 34.44 1.187 ;
     RECT  28.128 1.187 34.44 1.235 ;
     RECT  28.224 1.235 34.44 2.137 ;
     RECT  2.4 2.137 2.52 2.151 ;
     RECT  5.1 2.137 5.22 2.151 ;
     RECT  7.8 2.137 7.92 2.151 ;
     RECT  10.5 2.137 10.62 2.151 ;
     RECT  13.2 2.137 13.32 2.151 ;
     RECT  15.9 2.137 16.02 2.151 ;
     RECT  18.6 2.137 18.72 2.151 ;
     RECT  21.3 2.137 21.42 2.151 ;
     RECT  24 2.137 24.12 2.151 ;
     RECT  26.7 2.137 26.82 2.151 ;
     RECT  28.224 2.137 34.92 2.151 ;
     RECT  37.5 2.137 37.62 2.151 ;
     RECT  40.2 2.137 40.32 2.151 ;
     RECT  42.9 2.137 43.02 2.151 ;
     RECT  45.6 2.137 45.72 2.151 ;
     RECT  48.3 2.137 48.42 2.151 ;
     RECT  51 2.137 51.12 2.151 ;
     RECT  53.7 2.137 53.82 2.151 ;
     RECT  56.4 2.137 56.52 2.151 ;
     RECT  59.1 2.137 59.22 2.151 ;
     RECT  61.8 2.137 61.92 2.151 ;
     RECT  64.5 2.137 64.62 2.151 ;
     RECT  67.2 2.137 67.32 2.151 ;
     RECT  69.9 2.137 70.02 2.151 ;
     RECT  72.6 2.137 72.72 2.151 ;
     RECT  75.3 2.137 75.42 2.151 ;
     RECT  78 2.137 78.12 2.151 ;
     RECT  80.7 2.137 80.82 2.151 ;
     RECT  83.4 2.137 83.52 2.151 ;
     RECT  28.224 2.151 35.112 2.915 ;
     RECT  28.416 2.915 35.112 3.443 ;
     RECT  28.896 3.443 35.112 4.019 ;
     RECT  29.136 4.019 35.112 4.163 ;
     RECT  29.232 4.163 35.112 4.211 ;
     RECT  24 2.151 24.312 5.077 ;
     RECT  29.4 4.211 35.112 5.653 ;
     RECT  24 5.077 25.128 6.083 ;
     RECT  18.6 2.151 18.912 6.229 ;
     RECT  45.6 2.151 45.912 6.229 ;
     RECT  29.4 5.653 35.592 6.563 ;
     RECT  21.3 2.151 21.612 6.805 ;
     RECT  37.5 2.151 37.812 6.805 ;
     RECT  40.2 2.151 40.512 6.805 ;
     RECT  42.9 2.151 43.212 6.805 ;
     RECT  45.6 6.229 46.728 6.851 ;
     RECT  31.872 6.563 35.592 7.091 ;
     RECT  42.048 6.805 43.212 7.189 ;
     RECT  29.4 6.563 30.744 7.237 ;
     RECT  20.352 6.805 21.612 7.379 ;
     RECT  21.3 7.379 21.612 7.381 ;
     RECT  29.232 7.237 30.744 7.475 ;
     RECT  31.872 7.091 35.352 7.475 ;
     RECT  15.9 2.151 16.212 7.621 ;
     RECT  41.856 7.189 43.212 7.667 ;
     RECT  37.248 6.805 37.812 7.715 ;
     RECT  39.312 6.805 40.512 7.715 ;
     RECT  44.352 6.805 44.376 7.859 ;
     RECT  18.48 6.229 18.912 7.909 ;
     RECT  24 6.083 24.312 7.957 ;
     RECT  32.1 7.475 35.352 8.051 ;
     RECT  33.648 8.051 35.352 8.099 ;
     RECT  29.232 7.475 29.712 8.245 ;
     RECT  21.3 7.381 21.72 8.291 ;
     RECT  15.9 7.621 16.344 8.435 ;
     RECT  13.2 2.151 13.512 8.485 ;
     RECT  30.72 7.475 30.744 8.579 ;
     RECT  34.128 8.099 35.352 8.579 ;
     RECT  42.768 7.667 43.212 8.579 ;
     RECT  34.32 8.579 35.112 8.627 ;
     RECT  45.6 6.851 46.584 8.675 ;
     RECT  37.392 7.715 37.812 8.965 ;
     RECT  18.24 7.909 18.912 9.061 ;
     RECT  48.3 2.151 48.612 9.061 ;
     RECT  49.824 8.149 49.848 9.061 ;
     RECT  28.416 8.245 29.712 9.251 ;
     RECT  13.056 8.485 13.512 9.253 ;
     RECT  17.664 9.061 18.912 9.493 ;
     RECT  10.5 2.151 10.812 9.637 ;
     RECT  23.328 7.957 24.312 9.685 ;
     RECT  32.1 8.051 32.52 9.685 ;
     RECT  45.6 8.675 46.344 9.779 ;
     RECT  29.28 9.251 29.712 9.925 ;
     RECT  32.1 9.685 32.616 10.117 ;
     RECT  34.8 8.627 35.112 10.165 ;
     RECT  15.9 8.435 16.212 10.261 ;
     RECT  17.664 9.493 19.032 10.261 ;
     RECT  15.9 10.261 19.032 10.307 ;
     RECT  13.056 9.253 14.328 10.309 ;
     RECT  15.9 10.307 17.16 10.309 ;
     RECT  48.3 9.061 49.848 10.355 ;
     RECT  9.744 9.637 10.812 10.883 ;
     RECT  13.056 10.309 17.16 10.883 ;
     RECT  32.1 10.117 33.432 11.365 ;
     RECT  34.8 10.165 35.208 11.365 ;
     RECT  18.6 10.307 19.032 11.459 ;
     RECT  25.632 10.453 25.656 11.459 ;
     RECT  32.1 11.365 35.208 11.459 ;
     RECT  37.344 8.965 37.812 11.459 ;
     RECT  10.5 10.883 10.812 11.941 ;
     RECT  13.056 10.883 17.112 11.987 ;
     RECT  13.2 11.987 17.112 12.035 ;
     RECT  32.1 11.459 35.112 12.179 ;
     RECT  23.04 9.685 24.312 12.325 ;
     RECT  29.28 9.925 30.024 12.325 ;
     RECT  37.392 11.459 37.812 12.517 ;
     RECT  29.28 12.325 30.504 13.045 ;
     RECT  19.92 11.941 19.944 13.091 ;
     RECT  15.9 12.035 17.112 13.139 ;
     RECT  23.04 12.325 24.408 13.139 ;
     RECT  36.96 12.517 37.812 13.139 ;
     RECT  23.04 13.139 24.312 13.331 ;
     RECT  48.3 10.355 48.612 13.621 ;
     RECT  18.6 11.459 18.912 13.957 ;
     RECT  32.1 12.179 33.48 13.957 ;
     RECT  31.536 13.957 33.48 14.099 ;
     RECT  13.2 12.035 14.376 14.245 ;
     RECT  33.456 14.099 33.48 14.341 ;
     RECT  33.456 14.341 33.672 14.435 ;
     RECT  45.6 9.779 45.912 14.533 ;
     RECT  26.7 2.151 27.012 14.725 ;
     RECT  5.1 2.151 5.412 14.773 ;
     RECT  7.8 2.151 8.112 14.773 ;
     RECT  42.9 8.579 43.212 14.773 ;
     RECT  45.6 14.533 46.776 14.773 ;
     RECT  6.576 11.941 6.6 14.867 ;
     RECT  26.592 14.725 27.012 14.963 ;
     RECT  28.512 13.045 30.504 15.059 ;
     RECT  52.416 8.485 52.44 15.155 ;
     RECT  13.2 14.245 14.424 15.203 ;
     RECT  17.424 13.813 17.448 15.203 ;
     RECT  34.8 12.179 35.112 15.397 ;
     RECT  36.24 13.573 36.264 15.397 ;
     RECT  48.192 13.621 48.612 15.491 ;
     RECT  42.9 14.773 43.56 15.539 ;
     RECT  28.512 15.059 30.264 15.587 ;
     RECT  40.2 7.715 40.512 15.589 ;
     RECT  51 2.151 51.312 15.589 ;
     RECT  37.392 13.139 37.812 15.829 ;
     RECT  23.328 13.331 24.312 15.925 ;
     RECT  42.9 15.539 43.212 15.925 ;
     RECT  18.6 13.957 19.176 16.019 ;
     RECT  21.3 8.291 21.612 16.021 ;
     RECT  22.8 15.925 24.312 16.021 ;
     RECT  40.2 15.589 40.92 16.069 ;
     RECT  42.144 15.925 43.212 16.069 ;
     RECT  10.5 11.941 10.92 16.357 ;
     RECT  7.68 14.773 8.112 16.405 ;
     RECT  34.8 15.397 36.264 16.405 ;
     RECT  37.392 15.829 38.184 16.405 ;
     RECT  45.168 14.773 46.776 16.499 ;
     RECT  31.536 14.099 32.412 16.547 ;
     RECT  45.6 16.499 46.776 16.547 ;
     RECT  33.648 14.435 33.672 16.595 ;
     RECT  34.8 16.405 38.184 16.595 ;
     RECT  26.7 14.963 27.012 16.645 ;
     RECT  21.3 16.021 24.312 16.789 ;
     RECT  25.872 16.645 27.012 16.789 ;
     RECT  53.7 2.151 54.012 16.933 ;
     RECT  51 15.589 51.912 16.979 ;
     RECT  29.4 15.587 30.264 16.981 ;
     RECT  10.5 16.357 11.4 17.077 ;
     RECT  28.512 16.981 30.264 17.123 ;
     RECT  21.3 16.789 27.012 17.411 ;
     RECT  40.2 16.069 43.212 17.461 ;
     RECT  10.5 17.077 11.832 17.699 ;
     RECT  23.328 17.411 27.012 17.699 ;
     RECT  28.176 17.173 28.2 17.843 ;
     RECT  36.24 16.595 38.184 17.843 ;
     RECT  21.3 17.411 21.864 18.179 ;
     RECT  14.64 17.605 14.664 18.227 ;
     RECT  7.392 16.405 8.112 18.229 ;
     RECT  32.1 16.547 32.412 18.565 ;
     RECT  23.328 17.699 25.032 18.659 ;
     RECT  29.4 17.123 30.264 18.707 ;
     RECT  40.2 17.461 43.56 18.709 ;
     RECT  23.328 18.659 24.408 18.757 ;
     RECT  10.5 17.699 11.4 18.805 ;
     RECT  36.24 17.843 37.812 18.851 ;
     RECT  6.912 18.229 8.112 18.947 ;
     RECT  26.112 17.699 27.012 18.947 ;
     RECT  48.3 15.491 48.612 19.093 ;
     RECT  49.824 10.355 49.848 19.093 ;
     RECT  22.752 18.757 24.408 19.187 ;
     RECT  45.6 16.547 45.912 19.333 ;
     RECT  10.32 18.805 11.4 19.379 ;
     RECT  48.3 19.093 49.848 19.379 ;
     RECT  39.456 18.709 43.56 19.427 ;
     RECT  15.9 13.139 16.212 19.765 ;
     RECT  29.4 18.707 30.12 19.765 ;
     RECT  51 16.979 51.312 19.765 ;
     RECT  7.44 18.947 8.112 19.909 ;
     RECT  13.2 15.203 13.512 19.909 ;
     RECT  34.8 16.595 35.112 19.909 ;
     RECT  36.576 18.851 37.812 19.909 ;
     RECT  42 19.427 43.56 19.955 ;
     RECT  31.44 18.565 32.412 20.003 ;
     RECT  34.8 19.909 37.812 20.147 ;
     RECT  5.1 14.773 5.592 20.149 ;
     RECT  6.624 19.909 8.856 20.149 ;
     RECT  13.056 19.909 13.512 20.339 ;
     RECT  39.456 19.427 40.92 20.339 ;
     RECT  42 19.955 43.212 20.339 ;
     RECT  53.568 16.933 54.012 20.339 ;
     RECT  10.5 19.379 11.4 20.389 ;
     RECT  15.648 19.765 16.212 20.437 ;
     RECT  5.1 20.149 8.856 20.579 ;
     RECT  50.736 19.765 51.312 20.723 ;
     RECT  10.272 20.389 11.4 20.819 ;
     RECT  40.08 20.339 40.92 20.819 ;
     RECT  48.3 19.379 49.608 20.819 ;
     RECT  48.3 20.819 49.56 21.011 ;
     RECT  22.752 19.187 24.312 21.443 ;
     RECT  34.8 20.147 36.024 21.445 ;
     RECT  37.008 20.147 37.812 21.445 ;
     RECT  7.68 20.579 8.856 21.541 ;
     RECT  10.272 20.819 10.812 21.541 ;
     RECT  5.1 20.579 6.648 21.637 ;
     RECT  7.68 21.541 10.812 21.637 ;
     RECT  45.6 19.333 46.776 21.637 ;
     RECT  34.8 21.445 37.812 21.683 ;
     RECT  5.1 21.637 10.812 21.731 ;
     RECT  6.624 21.731 10.812 22.021 ;
     RECT  18.6 16.019 18.912 22.165 ;
     RECT  32.1 20.003 32.412 22.165 ;
     RECT  42.9 20.339 43.212 22.165 ;
     RECT  5.1 21.731 5.592 22.213 ;
     RECT  34.8 21.683 35.112 22.741 ;
     RECT  6.624 22.021 11.4 22.835 ;
     RECT  29.4 19.765 30.408 22.837 ;
     RECT  31.584 22.165 32.412 22.837 ;
     RECT  4.656 22.213 5.592 23.027 ;
     RECT  25.68 19.141 25.704 23.027 ;
     RECT  34.8 22.741 35.208 23.171 ;
     RECT  10.272 22.835 11.4 23.267 ;
     RECT  42.192 22.165 43.212 23.267 ;
     RECT  5.1 23.027 5.592 23.317 ;
     RECT  40.08 20.819 40.512 23.317 ;
     RECT  36.48 21.683 37.812 23.459 ;
     RECT  17.616 22.165 18.912 23.555 ;
     RECT  29.4 22.837 32.412 23.603 ;
     RECT  52.704 22.741 52.728 23.795 ;
     RECT  29.4 23.603 30.648 23.891 ;
     RECT  45.264 21.637 46.776 23.891 ;
     RECT  29.4 23.891 29.712 23.941 ;
     RECT  36.816 23.459 37.812 24.181 ;
     RECT  5.1 23.317 5.88 24.229 ;
     RECT  10.272 23.267 10.812 24.469 ;
     RECT  21.3 18.179 21.612 24.469 ;
     RECT  36.816 24.181 38.424 24.659 ;
     RECT  13.2 20.339 13.512 24.709 ;
     RECT  20.448 24.469 21.612 24.901 ;
     RECT  36.816 24.659 37.812 24.995 ;
     RECT  4.368 24.229 5.88 25.091 ;
     RECT  13.104 24.709 13.512 25.091 ;
     RECT  13.2 25.091 13.512 25.093 ;
     RECT  7.68 22.835 9.048 25.139 ;
     RECT  19.968 24.901 21.612 25.139 ;
     RECT  28.992 23.941 29.712 25.187 ;
     RECT  10.272 24.469 11.4 25.189 ;
     RECT  45.408 23.891 46.776 25.475 ;
     RECT  48.3 21.011 48.612 25.621 ;
     RECT  5.1 25.091 5.88 25.715 ;
     RECT  13.2 25.093 13.608 25.907 ;
     RECT  7.8 25.139 9.048 26.101 ;
     RECT  48.3 25.621 49.56 26.243 ;
     RECT  19.968 25.139 19.992 26.291 ;
     RECT  7.8 26.101 9.144 26.629 ;
     RECT  10.272 25.189 11.688 26.629 ;
     RECT  7.8 26.629 11.688 26.675 ;
     RECT  14.832 20.437 16.212 26.675 ;
     RECT  5.1 25.715 5.592 26.677 ;
     RECT  42.9 23.267 43.212 26.725 ;
     RECT  26.7 18.947 27.012 26.773 ;
     RECT  48.3 26.243 49.416 26.819 ;
     RECT  52.416 25.045 52.44 26.819 ;
     RECT  7.8 26.675 11.064 27.061 ;
     RECT  26.7 26.773 27.528 27.347 ;
     RECT  45.6 25.475 46.776 27.349 ;
     RECT  25.392 26.629 25.416 27.395 ;
     RECT  45.6 27.349 47.064 27.395 ;
     RECT  37.5 24.995 37.812 27.493 ;
     RECT  3.984 26.629 4.008 27.635 ;
     RECT  23.52 21.443 24.312 27.637 ;
     RECT  51 20.723 51.312 27.733 ;
     RECT  29.4 25.187 29.712 27.829 ;
     RECT  32.1 23.603 32.412 27.877 ;
     RECT  6.816 27.061 11.064 27.925 ;
     RECT  5.1 26.677 5.784 28.067 ;
     RECT  42.9 26.725 43.896 28.163 ;
     RECT  15.12 26.675 16.212 28.261 ;
     RECT  18.6 23.555 18.912 28.261 ;
     RECT  18.6 28.261 19.032 28.451 ;
     RECT  39.84 23.317 40.512 28.453 ;
     RECT  48.3 26.819 48.612 28.453 ;
     RECT  13.2 25.907 13.512 28.837 ;
     RECT  28.464 27.829 29.712 28.883 ;
     RECT  38.832 25.525 38.856 28.981 ;
     RECT  39.84 28.453 41.496 28.981 ;
     RECT  26.7 27.347 27.012 29.077 ;
     RECT  36.72 27.493 37.812 29.123 ;
     RECT  48.3 28.453 49.416 29.507 ;
     RECT  26.592 29.077 27.012 29.603 ;
     RECT  34.8 23.171 35.112 29.605 ;
     RECT  38.832 28.981 41.496 30.035 ;
     RECT  23.52 27.637 24.504 30.275 ;
     RECT  13.2 28.837 13.704 30.325 ;
     RECT  15.024 28.261 16.212 30.373 ;
     RECT  42.9 28.163 43.212 30.565 ;
     RECT  13.2 30.325 13.992 30.613 ;
     RECT  42.9 30.565 43.944 30.661 ;
     RECT  50.88 27.733 51.312 30.661 ;
     RECT  38.832 30.035 40.512 30.707 ;
     RECT  6.816 27.925 11.112 30.805 ;
     RECT  5.1 28.067 5.64 30.851 ;
     RECT  6.72 30.805 11.112 30.851 ;
     RECT  34.8 29.605 35.592 30.947 ;
     RECT  42.768 30.661 43.944 31.093 ;
     RECT  48.3 29.507 48.612 31.093 ;
     RECT  12.528 30.613 13.992 31.189 ;
     RECT  15.024 30.373 16.728 31.189 ;
     RECT  31.968 27.877 32.412 31.427 ;
     RECT  50.88 30.661 51.912 31.427 ;
     RECT  7.8 30.851 11.112 31.475 ;
     RECT  6.72 30.851 6.744 31.525 ;
     RECT  12.528 31.189 16.728 31.525 ;
     RECT  42.48 31.093 43.944 31.619 ;
     RECT  6.432 31.525 6.744 31.861 ;
     RECT  7.8 31.475 8.112 31.861 ;
     RECT  33.696 30.325 33.72 31.861 ;
     RECT  34.8 30.947 35.112 31.861 ;
     RECT  47.04 27.395 47.064 31.907 ;
     RECT  12.528 31.525 16.872 31.955 ;
     RECT  38.832 30.707 38.856 31.957 ;
     RECT  40.2 30.707 40.512 31.957 ;
     RECT  48.3 31.093 48.744 32.003 ;
     RECT  38.832 31.957 40.512 32.339 ;
     RECT  33.696 31.861 35.112 32.341 ;
     RECT  26.7 29.603 27.012 32.437 ;
     RECT  33.696 32.341 35.208 32.531 ;
     RECT  12.528 31.955 13.512 32.771 ;
     RECT  37.5 29.123 37.812 32.773 ;
     RECT  6.432 31.861 8.112 32.965 ;
     RECT  42.768 31.619 43.944 33.059 ;
     RECT  20.256 32.437 20.28 33.299 ;
     RECT  26.7 32.437 27.384 33.347 ;
     RECT  15.9 31.955 16.872 33.349 ;
     RECT  5.1 30.851 5.412 33.397 ;
     RECT  6.432 32.965 8.232 33.397 ;
     RECT  26.7 33.347 27.012 33.589 ;
     RECT  5.1 33.397 8.232 33.635 ;
     RECT  15.9 33.349 17.016 33.971 ;
     RECT  18.6 28.451 18.912 34.165 ;
     RECT  59.1 2.151 59.412 34.165 ;
     RECT  15.9 33.971 16.728 34.211 ;
     RECT  36.624 32.773 37.812 34.211 ;
     RECT  13.104 32.771 13.512 34.309 ;
     RECT  53.7 20.339 54.012 34.357 ;
     RECT  39.312 32.339 40.512 34.403 ;
     RECT  9.6 31.475 11.112 34.741 ;
     RECT  5.1 33.635 8.112 34.787 ;
     RECT  6.864 34.787 8.112 34.835 ;
     RECT  12.768 34.309 13.512 35.171 ;
     RECT  51 31.427 51.912 35.219 ;
     RECT  48.3 32.003 48.612 35.269 ;
     RECT  26.208 33.589 27.012 35.363 ;
     RECT  34.8 32.531 35.208 35.363 ;
     RECT  63.264 34.741 63.288 35.363 ;
     RECT  48.3 35.269 49.56 35.413 ;
     RECT  53.04 34.357 54.012 35.459 ;
     RECT  23.616 30.275 24.504 35.509 ;
     RECT  23.376 35.509 24.504 35.555 ;
     RECT  32.1 31.427 32.412 35.845 ;
     RECT  14.736 34.165 14.76 35.939 ;
     RECT  29.4 28.883 29.712 36.085 ;
     RECT  9.6 34.741 11.496 36.515 ;
     RECT  23.376 35.555 24.312 36.515 ;
     RECT  26.592 35.363 27.012 36.515 ;
     RECT  47.904 35.413 49.56 36.515 ;
     RECT  9.6 36.515 10.812 36.517 ;
     RECT  26.7 36.515 27.012 36.661 ;
     RECT  9.12 36.517 10.812 36.707 ;
     RECT  29.4 36.085 30.552 36.755 ;
     RECT  5.1 34.787 5.412 36.805 ;
     RECT  7.68 34.835 8.112 36.997 ;
     RECT  23.424 36.515 24.312 36.997 ;
     RECT  40.2 34.403 40.512 37.429 ;
     RECT  37.5 34.211 37.812 37.477 ;
     RECT  45.6 27.395 45.912 37.477 ;
     RECT  9.6 36.707 10.812 37.667 ;
     RECT  25.632 36.901 25.656 37.667 ;
     RECT  26.7 36.661 27.912 37.667 ;
     RECT  42.768 33.059 43.212 37.861 ;
     RECT  38.928 36.421 38.952 37.907 ;
     RECT  26.7 37.667 27.012 37.909 ;
     RECT  37.248 37.477 37.812 37.957 ;
     RECT  23.424 36.997 24.408 38.003 ;
     RECT  34.8 35.363 35.112 38.005 ;
     RECT  58.944 34.165 59.412 38.005 ;
     RECT  26.16 37.909 27.012 38.051 ;
     RECT  7.248 36.997 8.112 38.101 ;
     RECT  40.2 37.429 40.632 38.101 ;
     RECT  37.248 37.957 38.472 38.147 ;
     RECT  58.944 38.005 59.784 38.197 ;
     RECT  33.696 32.531 33.72 38.243 ;
     RECT  13.2 35.171 13.512 38.341 ;
     RECT  10.224 37.667 10.812 38.387 ;
     RECT  58.272 38.197 59.784 38.533 ;
     RECT  58.272 38.533 59.832 38.675 ;
     RECT  58.272 38.675 59.784 38.723 ;
     RECT  7.248 38.101 9.096 38.725 ;
     RECT  45.6 37.477 46.344 38.771 ;
     RECT  58.944 38.723 59.784 38.771 ;
     RECT  31.968 35.845 32.412 38.773 ;
     RECT  6.816 38.725 9.096 38.819 ;
     RECT  39.552 38.101 40.632 38.819 ;
     RECT  58.944 38.771 59.688 38.819 ;
     RECT  10.368 38.387 10.812 38.867 ;
     RECT  13.2 38.341 13.608 38.963 ;
     RECT  5.1 36.805 5.688 39.059 ;
     RECT  64.5 2.151 64.812 39.061 ;
     RECT  44.448 38.005 44.472 39.107 ;
     RECT  42.768 37.861 43.32 39.109 ;
     RECT  23.424 38.003 24.312 39.205 ;
     RECT  10.5 38.867 10.812 39.301 ;
     RECT  13.2 38.963 13.512 39.301 ;
     RECT  34.8 38.005 35.256 39.301 ;
     RECT  45.6 38.771 45.912 39.637 ;
     RECT  47.904 36.515 48.612 39.683 ;
     RECT  31.2 38.773 32.412 39.731 ;
     RECT  34.8 39.301 35.304 39.781 ;
     RECT  42.48 39.109 43.32 39.827 ;
     RECT  23.232 39.205 24.312 39.877 ;
     RECT  23.232 39.877 24.936 40.019 ;
     RECT  64.5 39.061 64.92 40.067 ;
     RECT  45.12 39.637 45.912 40.163 ;
     RECT  10.5 39.301 11.448 40.165 ;
     RECT  37.5 38.147 38.472 40.213 ;
     RECT  39.552 38.819 40.512 40.213 ;
     RECT  37.5 40.213 40.512 40.355 ;
     RECT  0.384 40.117 0.408 40.403 ;
     RECT  6.816 38.819 8.112 40.499 ;
     RECT  39.552 40.355 40.512 40.499 ;
     RECT  23.424 40.019 24.936 40.595 ;
     RECT  37.5 40.355 38.472 40.595 ;
     RECT  2.4 2.151 2.712 40.597 ;
     RECT  3.936 39.877 3.96 40.691 ;
     RECT  2.4 40.597 2.856 40.883 ;
     RECT  56.4 2.151 56.712 40.885 ;
     RECT  0.336 40.837 0.36 40.979 ;
     RECT  26.7 38.051 27.012 40.981 ;
     RECT  61.8 2.151 62.112 41.029 ;
     RECT  23.424 40.595 24.312 41.075 ;
     RECT  56.304 40.885 56.712 41.269 ;
     RECT  26.208 40.981 27.012 41.365 ;
     RECT  0.288 41.173 0.312 41.411 ;
     RECT  12.912 39.301 13.512 41.411 ;
     RECT  15.9 34.211 16.212 41.461 ;
     RECT  32.1 39.731 32.412 41.461 ;
     RECT  18.48 34.165 18.912 41.507 ;
     RECT  7.8 40.499 8.112 41.509 ;
     RECT  56.304 41.269 56.904 41.509 ;
     RECT  61.68 41.029 62.112 41.653 ;
     RECT  56.304 41.509 57.048 41.699 ;
     RECT  26.208 41.365 27.432 41.795 ;
     RECT  40.2 40.499 40.512 42.133 ;
     RECT  7.8 41.509 8.952 42.227 ;
     RECT  34.8 39.781 35.88 42.227 ;
     RECT  10.032 40.165 11.448 42.275 ;
     RECT  63.12 42.421 63.144 42.563 ;
     RECT  18.6 41.507 18.912 42.709 ;
     RECT  42.768 39.827 43.32 42.755 ;
     RECT  23.568 41.075 24.312 42.803 ;
     RECT  61.008 41.653 62.112 42.803 ;
     RECT  45.6 40.163 45.912 42.901 ;
     RECT  56.4 41.699 56.712 42.901 ;
     RECT  53.7 35.459 54.012 42.997 ;
     RECT  56.4 42.901 56.808 43.043 ;
     RECT  13.2 41.411 13.512 43.285 ;
     RECT  45.6 42.901 46.728 43.285 ;
     RECT  48.048 39.683 48.612 43.285 ;
     RECT  10.5 42.275 11.448 43.379 ;
     RECT  25.68 42.037 25.704 43.379 ;
     RECT  34.8 42.227 35.304 43.765 ;
     RECT  26.7 41.795 27.432 43.861 ;
     RECT  12.432 43.285 13.512 44.051 ;
     RECT  17.952 42.709 18.912 44.051 ;
     RECT  13.2 44.051 13.512 44.101 ;
     RECT  26.7 43.861 28.104 44.579 ;
     RECT  34.8 43.765 36.216 44.963 ;
     RECT  21.3 25.139 21.612 44.965 ;
     RECT  53.7 42.997 54.696 44.965 ;
     RECT  31.968 41.461 32.412 45.059 ;
     RECT  13.2 44.101 14.28 45.395 ;
     RECT  56.4 43.043 56.712 45.445 ;
     RECT  15.36 41.461 16.212 45.539 ;
     RECT  20.448 44.965 21.612 45.541 ;
     RECT  58.944 38.819 59.412 45.541 ;
     RECT  20.208 45.541 21.612 45.587 ;
     RECT  56.4 45.445 57.048 45.587 ;
     RECT  34.8 44.963 35.304 45.635 ;
     RECT  53.7 44.965 54.744 45.635 ;
     RECT  51 35.219 51.312 45.685 ;
     RECT  58.944 45.541 59.544 45.731 ;
     RECT  9.12 43.861 9.144 45.779 ;
     RECT  45.6 43.285 48.612 46.019 ;
     RECT  50.688 45.685 51.312 46.211 ;
     RECT  26.7 44.579 27.432 46.787 ;
     RECT  42.9 42.755 43.32 46.787 ;
     RECT  20.208 45.587 20.232 47.075 ;
     RECT  34.8 45.635 35.256 47.219 ;
     RECT  37.5 40.595 37.812 47.557 ;
     RECT  37.5 47.557 38.76 47.699 ;
     RECT  59.1 45.731 59.544 48.467 ;
     RECT  34.8 47.219 35.208 48.515 ;
     RECT  40.032 42.133 40.512 49.043 ;
     RECT  61.8 42.803 62.112 49.381 ;
     RECT  50.88 46.211 51.312 49.619 ;
     RECT  40.2 49.043 40.512 50.101 ;
     RECT  37.5 47.699 38.424 50.771 ;
     RECT  47.616 46.019 48.612 51.061 ;
     RECT  61.536 49.381 62.112 51.107 ;
     RECT  33.648 47.701 33.672 51.635 ;
     RECT  41.856 50.629 41.88 51.829 ;
     RECT  37.5 50.771 37.944 51.923 ;
     RECT  39.84 50.101 40.512 52.213 ;
     RECT  45.6 46.019 45.912 52.357 ;
     RECT  47.616 51.061 49.08 52.453 ;
     RECT  47.616 52.453 49.608 52.499 ;
     RECT  53.7 45.635 54.012 52.741 ;
     RECT  41.616 51.829 41.88 53.027 ;
     RECT  39.36 52.213 40.512 53.075 ;
     RECT  45.6 52.357 46.104 53.459 ;
     RECT  51 49.619 51.312 53.557 ;
     RECT  41.856 53.027 41.88 53.603 ;
     RECT  53.7 52.741 54.504 53.795 ;
     RECT  49.584 52.499 49.608 54.179 ;
     RECT  51 53.557 51.48 54.179 ;
     RECT  47.616 52.499 48.612 55.715 ;
     RECT  2.4 40.883 2.712 75.609 ;
     RECT  5.1 39.059 5.412 75.609 ;
     RECT  7.8 42.227 8.112 75.609 ;
     RECT  10.5 43.379 10.812 75.609 ;
     RECT  13.2 45.395 13.512 75.609 ;
     RECT  15.9 45.539 16.212 75.609 ;
     RECT  18.6 44.051 18.912 75.609 ;
     RECT  21.3 45.587 21.612 75.609 ;
     RECT  24 42.803 24.312 75.609 ;
     RECT  26.7 46.787 27.012 75.609 ;
     RECT  29.4 36.755 29.712 75.609 ;
     RECT  32.1 45.059 32.412 75.609 ;
     RECT  34.8 48.515 35.112 75.609 ;
     RECT  37.5 51.923 37.812 75.609 ;
     RECT  40.2 53.075 40.512 75.609 ;
     RECT  42.9 46.787 43.212 75.609 ;
     RECT  45.6 53.459 45.912 75.609 ;
     RECT  48.3 55.715 48.612 75.609 ;
     RECT  51 54.179 51.312 75.609 ;
     RECT  53.7 53.795 54.012 75.609 ;
     RECT  56.4 45.587 56.712 75.609 ;
     RECT  59.1 48.467 59.412 75.609 ;
     RECT  61.8 51.107 62.112 75.609 ;
     RECT  64.5 40.067 64.812 75.609 ;
     RECT  67.2 2.151 67.512 75.609 ;
     RECT  69.9 2.151 70.212 75.609 ;
     RECT  72.6 2.151 72.912 75.609 ;
     RECT  75.3 2.151 75.612 75.609 ;
     RECT  78 2.151 78.312 75.609 ;
     RECT  80.7 2.151 81.012 75.609 ;
     RECT  83.4 2.151 83.712 75.609 ;
     RECT  2.4 75.609 2.52 75.623 ;
     RECT  5.1 75.609 5.22 75.623 ;
     RECT  7.8 75.609 7.92 75.623 ;
     RECT  10.5 75.609 10.62 75.623 ;
     RECT  13.2 75.609 13.32 75.623 ;
     RECT  15.9 75.609 16.02 75.623 ;
     RECT  18.6 75.609 18.72 75.623 ;
     RECT  21.3 75.609 21.42 75.623 ;
     RECT  24 75.609 24.12 75.623 ;
     RECT  26.7 75.609 26.82 75.623 ;
     RECT  29.4 75.609 29.52 75.623 ;
     RECT  32.1 75.609 32.22 75.623 ;
     RECT  34.8 75.609 34.92 75.623 ;
     RECT  37.5 75.609 37.62 75.623 ;
     RECT  40.2 75.609 40.32 75.623 ;
     RECT  42.9 75.609 43.176 75.623 ;
     RECT  45.6 75.609 45.72 75.623 ;
     RECT  48.3 75.609 48.42 75.623 ;
     RECT  51 75.609 51.12 75.623 ;
     RECT  53.7 75.609 53.82 75.623 ;
     RECT  56.4 75.609 56.52 75.623 ;
     RECT  59.1 75.609 59.22 75.623 ;
     RECT  61.8 75.609 61.92 75.623 ;
     RECT  64.5 75.609 64.62 75.623 ;
     RECT  67.2 75.609 67.32 75.623 ;
     RECT  69.9 75.609 70.02 75.623 ;
     RECT  72.6 75.609 72.72 75.623 ;
     RECT  75.3 75.609 75.42 75.623 ;
     RECT  78 75.609 78.12 75.623 ;
     RECT  80.7 75.609 80.82 75.623 ;
     RECT  83.4 75.609 83.52 75.623 ;
     RECT  28.032 1.187 28.128 1.235 ;
     RECT  28.032 1.235 28.224 2.137 ;
     RECT  26.82 2.137 28.224 2.151 ;
     RECT  27.012 2.151 28.224 2.915 ;
     RECT  27.012 2.915 28.416 3.443 ;
     RECT  30.744 6.563 31.872 7.475 ;
     RECT  18.912 6.805 20.352 7.379 ;
     RECT  37.812 6.805 39.312 7.715 ;
     RECT  43.212 6.805 44.352 7.859 ;
     RECT  44.376 6.805 45.6 7.859 ;
     RECT  40.512 7.189 41.856 7.667 ;
     RECT  29.712 7.475 30.72 8.579 ;
     RECT  30.744 7.475 32.1 8.579 ;
     RECT  37.344 7.715 37.392 8.965 ;
     RECT  32.52 8.051 33.648 8.099 ;
     RECT  48.612 8.149 49.824 9.061 ;
     RECT  49.848 8.149 51 19.379 ;
     RECT  27.012 8.245 28.416 9.251 ;
     RECT  21.612 8.291 21.72 9.685 ;
     RECT  16.212 8.435 16.344 9.061 ;
     RECT  51.312 8.485 52.416 15.155 ;
     RECT  52.44 8.485 53.7 15.155 ;
     RECT  29.712 8.579 30.024 9.925 ;
     RECT  34.32 8.627 34.8 10.117 ;
     RECT  16.212 9.061 17.664 10.261 ;
     RECT  21.612 9.685 23.04 13.331 ;
     RECT  33.432 10.117 34.8 11.365 ;
     RECT  17.16 10.307 18.6 10.883 ;
     RECT  48.612 10.355 49.824 19.093 ;
     RECT  24.312 10.453 25.632 11.459 ;
     RECT  25.656 10.453 26.7 11.459 ;
     RECT  17.112 10.883 18.6 13.139 ;
     RECT  18.912 11.459 19.032 11.941 ;
     RECT  24.312 11.459 24.408 12.325 ;
     RECT  37.344 11.459 37.392 12.517 ;
     RECT  5.412 11.941 6.576 14.773 ;
     RECT  6.6 11.941 7.8 14.773 ;
     RECT  18.912 11.941 19.92 13.091 ;
     RECT  19.944 11.941 21.3 13.091 ;
     RECT  14.376 12.035 15.9 14.245 ;
     RECT  33.48 12.179 34.8 14.341 ;
     RECT  27.012 13.045 28.512 15.587 ;
     RECT  18.912 13.091 19.176 13.957 ;
     RECT  16.212 13.139 18.6 13.813 ;
     RECT  36.96 13.139 37.392 13.573 ;
     RECT  35.112 13.573 36.24 15.397 ;
     RECT  36.264 13.573 37.392 16.405 ;
     RECT  16.212 13.813 17.424 15.203 ;
     RECT  17.448 13.813 18.6 15.203 ;
     RECT  30.504 13.957 31.536 15.059 ;
     RECT  32.412 14.099 33.456 14.435 ;
     RECT  14.424 14.245 15.9 15.203 ;
     RECT  33.672 14.341 34.8 16.595 ;
     RECT  32.412 14.435 33.648 16.595 ;
     RECT  46.776 14.533 48.192 15.491 ;
     RECT  5.592 14.773 6.576 14.867 ;
     RECT  6.6 14.773 7.68 14.867 ;
     RECT  30.264 15.059 31.536 16.547 ;
     RECT  51.312 15.155 51.912 15.589 ;
     RECT  46.776 15.491 48.3 16.547 ;
     RECT  27.012 15.587 29.4 16.981 ;
     RECT  21.612 15.925 22.8 16.021 ;
     RECT  40.92 15.925 42.144 16.069 ;
     RECT  35.112 16.595 36.24 18.851 ;
     RECT  27.012 16.981 28.512 17.123 ;
     RECT  11.832 17.077 13.2 17.699 ;
     RECT  27.012 17.123 29.4 17.173 ;
     RECT  27.012 17.173 28.176 17.843 ;
     RECT  28.2 17.173 29.4 17.843 ;
     RECT  21.864 17.411 23.328 18.179 ;
     RECT  13.512 17.605 14.64 18.227 ;
     RECT  14.664 17.605 15.9 18.227 ;
     RECT  25.032 17.699 26.112 18.659 ;
     RECT  21.612 18.179 23.328 18.757 ;
     RECT  5.592 18.229 6.912 18.947 ;
     RECT  30.264 18.565 31.44 18.707 ;
     RECT  24.408 18.659 26.112 18.947 ;
     RECT  30.12 18.707 31.44 19.765 ;
     RECT  21.612 18.757 22.752 21.443 ;
     RECT  35.112 18.851 36.576 19.909 ;
     RECT  5.592 18.947 7.44 19.909 ;
     RECT  24.408 18.947 26.7 19.141 ;
     RECT  24.408 19.141 25.68 19.187 ;
     RECT  25.704 19.141 26.7 23.027 ;
     RECT  24.312 19.187 25.68 23.027 ;
     RECT  46.776 19.333 48.3 27.349 ;
     RECT  10.32 19.379 10.5 19.909 ;
     RECT  49.608 19.379 51 19.765 ;
     RECT  40.92 19.427 42 20.339 ;
     RECT  30.408 19.765 31.44 20.003 ;
     RECT  49.608 19.765 50.736 20.723 ;
     RECT  5.592 19.909 6.624 20.149 ;
     RECT  8.856 19.909 10.5 20.389 ;
     RECT  36.024 20.147 37.008 21.445 ;
     RECT  8.856 20.389 10.272 21.541 ;
     RECT  13.512 20.437 14.832 25.093 ;
     RECT  6.648 20.579 7.68 21.637 ;
     RECT  49.608 20.723 51 20.819 ;
     RECT  10.812 20.819 11.4 22.021 ;
     RECT  49.56 20.819 51 21.011 ;
     RECT  35.112 21.683 36.48 22.741 ;
     RECT  5.592 21.731 6.624 22.835 ;
     RECT  16.212 22.165 17.616 23.555 ;
     RECT  30.408 22.165 31.584 22.837 ;
     RECT  35.208 22.741 36.48 23.171 ;
     RECT  51.312 22.741 52.704 23.795 ;
     RECT  52.728 22.741 53.7 23.795 ;
     RECT  5.592 22.835 5.88 23.317 ;
     RECT  9.048 22.835 10.272 26.101 ;
     RECT  4.656 23.027 5.1 24.229 ;
     RECT  35.112 23.171 36.48 23.459 ;
     RECT  10.812 23.267 11.4 24.469 ;
     RECT  30.648 23.603 32.1 23.891 ;
     RECT  51.312 23.795 53.7 25.045 ;
     RECT  38.424 24.181 39.84 24.659 ;
     RECT  37.812 24.659 39.84 25.525 ;
     RECT  18.912 24.901 19.968 26.291 ;
     RECT  51.312 25.045 52.416 26.819 ;
     RECT  52.44 25.045 53.7 26.819 ;
     RECT  13.104 25.091 13.2 25.189 ;
     RECT  13.608 25.093 14.832 25.907 ;
     RECT  19.992 25.139 21.3 26.291 ;
     RECT  11.688 25.189 13.2 26.675 ;
     RECT  37.812 25.525 38.832 32.339 ;
     RECT  38.856 25.525 39.84 28.981 ;
     RECT  49.56 25.621 51 26.243 ;
     RECT  5.592 25.715 5.88 26.677 ;
     RECT  13.512 25.907 14.832 26.675 ;
     RECT  9.144 26.101 10.272 26.629 ;
     RECT  49.416 26.243 51 26.819 ;
     RECT  2.712 26.629 3.984 27.635 ;
     RECT  4.008 26.629 5.1 27.635 ;
     RECT  24.312 26.629 25.392 27.395 ;
     RECT  25.416 26.629 26.7 27.395 ;
     RECT  11.064 26.675 11.112 27.925 ;
     RECT  5.784 26.677 5.88 27.061 ;
     RECT  50.88 26.819 51 27.733 ;
     RECT  5.784 27.061 6.816 28.067 ;
     RECT  27.012 27.347 27.528 27.829 ;
     RECT  47.064 27.349 48.3 31.907 ;
     RECT  24.312 27.395 24.504 27.637 ;
     RECT  45.912 27.395 47.04 31.907 ;
     RECT  27.012 27.829 28.464 28.883 ;
     RECT  5.64 28.067 6.816 30.805 ;
     RECT  13.512 28.261 15.024 28.837 ;
     RECT  41.496 28.453 42.9 30.035 ;
     RECT  49.416 28.453 50.88 29.507 ;
     RECT  13.704 28.837 15.024 30.325 ;
     RECT  42.48 30.035 42.9 30.661 ;
     RECT  13.992 30.325 15.024 31.189 ;
     RECT  32.412 30.325 33.696 38.243 ;
     RECT  33.72 30.325 34.8 31.861 ;
     RECT  11.112 30.613 12.528 32.771 ;
     RECT  42.48 30.661 42.768 31.093 ;
     RECT  38.856 30.707 40.2 31.957 ;
     RECT  5.64 30.805 6.72 30.851 ;
     RECT  5.412 30.851 6.72 31.525 ;
     RECT  6.744 30.851 7.8 31.861 ;
     RECT  35.112 30.947 35.208 32.341 ;
     RECT  8.112 31.475 9.6 32.965 ;
     RECT  5.412 31.525 6.432 33.397 ;
     RECT  37.812 32.339 39.312 34.403 ;
     RECT  18.912 32.437 20.256 33.299 ;
     RECT  20.28 32.437 21.3 33.299 ;
     RECT  33.72 32.531 34.8 38.243 ;
     RECT  35.208 32.773 36.624 34.211 ;
     RECT  8.232 32.965 9.6 33.635 ;
     RECT  8.112 33.635 9.6 36.517 ;
     RECT  13.512 34.165 14.736 35.939 ;
     RECT  14.76 34.165 15.9 35.939 ;
     RECT  51.912 34.357 53.04 35.219 ;
     RECT  11.496 34.741 12.768 35.171 ;
     RECT  62.112 34.741 63.264 35.363 ;
     RECT  63.288 34.741 64.5 35.363 ;
     RECT  5.412 34.787 6.864 34.835 ;
     RECT  49.56 35.269 51 36.515 ;
     RECT  24.312 35.555 24.504 36.901 ;
     RECT  30.552 36.085 31.968 36.755 ;
     RECT  37.812 36.421 38.928 37.907 ;
     RECT  38.952 36.421 40.2 37.907 ;
     RECT  26.592 36.515 26.7 36.901 ;
     RECT  8.112 36.517 9.12 36.707 ;
     RECT  27.912 36.661 29.4 37.667 ;
     RECT  8.112 36.707 9.6 37.667 ;
     RECT  24.312 36.901 25.632 36.997 ;
     RECT  25.656 36.901 26.7 37.667 ;
     RECT  24.408 36.997 25.632 37.667 ;
     RECT  8.112 37.667 10.224 38.101 ;
     RECT  26.16 37.667 26.7 37.909 ;
     RECT  37.812 37.907 40.2 37.957 ;
     RECT  38.472 37.957 40.2 38.101 ;
     RECT  43.32 38.005 44.448 39.107 ;
     RECT  44.472 38.005 45.6 39.107 ;
     RECT  9.096 38.101 10.224 38.387 ;
     RECT  38.472 38.101 39.552 40.213 ;
     RECT  9.096 38.387 10.368 38.819 ;
     RECT  5.688 38.725 6.816 39.059 ;
     RECT  29.712 38.773 31.2 39.731 ;
     RECT  10.032 38.819 10.368 38.867 ;
     RECT  10.032 38.867 10.5 40.165 ;
     RECT  5.412 39.059 6.816 40.499 ;
     RECT  45.12 39.107 45.6 39.637 ;
     RECT  11.448 39.301 12.912 41.411 ;
     RECT  2.712 39.877 3.936 40.597 ;
     RECT  3.96 39.877 5.1 40.691 ;
     RECT  38.472 40.355 39.552 40.499 ;
     RECT  24.312 40.595 24.936 40.981 ;
     RECT  2.856 40.597 3.936 40.691 ;
     RECT  24.312 40.981 26.208 41.795 ;
     RECT  18.48 41.507 18.6 42.709 ;
     RECT  8.952 41.509 10.032 42.227 ;
     RECT  56.712 41.699 56.808 42.901 ;
     RECT  24.312 41.795 26.7 42.037 ;
     RECT  24.312 42.037 25.68 43.379 ;
     RECT  25.704 42.037 26.7 43.379 ;
     RECT  62.112 42.421 63.12 42.563 ;
     RECT  63.144 42.421 64.5 42.563 ;
     RECT  46.728 42.901 48.048 43.285 ;
     RECT  11.448 43.285 12.432 43.379 ;
     RECT  36.216 43.765 37.5 44.963 ;
     RECT  8.112 43.861 9.12 45.779 ;
     RECT  9.144 43.861 10.5 45.779 ;
     RECT  28.104 43.861 29.4 44.579 ;
     RECT  14.28 44.101 15.36 45.395 ;
     RECT  18.912 45.541 20.208 47.075 ;
     RECT  20.232 45.587 21.3 47.075 ;
     RECT  38.76 47.557 40.032 47.699 ;
     RECT  32.412 47.701 33.648 51.635 ;
     RECT  33.672 47.701 34.8 51.635 ;
     RECT  40.032 49.043 40.2 50.101 ;
     RECT  38.424 50.101 39.84 50.771 ;
     RECT  40.512 50.629 41.856 51.829 ;
     RECT  41.88 50.629 42.9 53.603 ;
     RECT  37.944 50.771 39.84 51.923 ;
     RECT  40.512 51.829 41.616 53.027 ;
     RECT  39.36 51.923 39.84 52.213 ;
     RECT  46.104 52.357 47.616 53.459 ;
     RECT  49.608 52.453 51 54.179 ;
     RECT  48.612 52.499 49.584 54.179 ;
     RECT  40.512 53.027 41.856 53.603 ;
  END
END dsfd_node_LLfd
END LIBRARY
